VERSION 5.8 ;
BUSBITCHARS "[]" ;
DIVIDERCHAR "/" ;
UNITS
    DATABASE MICRONS 1000 ;
END UNITS

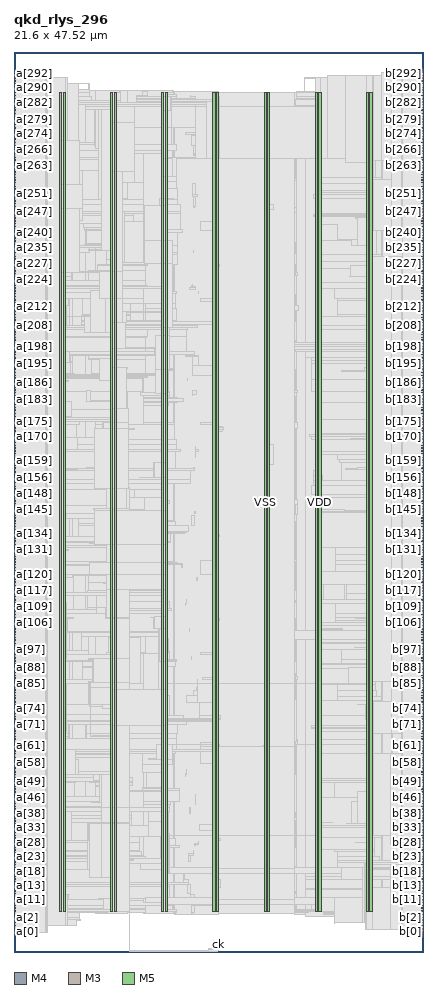
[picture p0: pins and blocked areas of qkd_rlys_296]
MACRO qkd_rlys_296
  FOREIGN qkd_rlys_296 0 0 ;
  CLASS BLOCK ;
  SIZE 21.6 BY 47.52 ;
  PIN a[0]
    DIRECTION INPUT ;
    USE SIGNAL ;
    PORT
      LAYER M4 ;
        RECT  0 1.056 0.084 1.08 ;
    END
  END a[0]
  PIN a[100]
    DIRECTION INPUT ;
    USE SIGNAL ;
    PORT
      LAYER M4 ;
        RECT  0 16.464 0.084 16.488 ;
    END
  END a[100]
  PIN a[101]
    DIRECTION INPUT ;
    USE SIGNAL ;
    PORT
      LAYER M4 ;
        RECT  0 16.608 0.084 16.632 ;
    END
  END a[101]
  PIN a[102]
    DIRECTION INPUT ;
    USE SIGNAL ;
    PORT
      LAYER M4 ;
        RECT  0 16.752 0.084 16.776 ;
    END
  END a[102]
  PIN a[103]
    DIRECTION INPUT ;
    USE SIGNAL ;
    PORT
      LAYER M4 ;
        RECT  0 16.896 0.084 16.92 ;
    END
  END a[103]
  PIN a[104]
    DIRECTION INPUT ;
    USE SIGNAL ;
    PORT
      LAYER M4 ;
        RECT  0 17.04 0.084 17.064 ;
    END
  END a[104]
  PIN a[105]
    DIRECTION INPUT ;
    USE SIGNAL ;
    PORT
      LAYER M4 ;
        RECT  0 17.232 0.084 17.256 ;
    END
  END a[105]
  PIN a[106]
    DIRECTION INPUT ;
    USE SIGNAL ;
    PORT
      LAYER M4 ;
        RECT  0 17.376 0.084 17.4 ;
    END
  END a[106]
  PIN a[107]
    DIRECTION INPUT ;
    USE SIGNAL ;
    PORT
      LAYER M4 ;
        RECT  0 17.52 0.084 17.544 ;
    END
  END a[107]
  PIN a[108]
    DIRECTION INPUT ;
    USE SIGNAL ;
    PORT
      LAYER M4 ;
        RECT  0 17.664 0.084 17.688 ;
    END
  END a[108]
  PIN a[109]
    DIRECTION INPUT ;
    USE SIGNAL ;
    PORT
      LAYER M4 ;
        RECT  0 17.808 0.084 17.832 ;
    END
  END a[109]
  PIN a[10]
    DIRECTION INPUT ;
    USE SIGNAL ;
    PORT
      LAYER M4 ;
        RECT  0 2.592 0.084 2.616 ;
    END
  END a[10]
  PIN a[110]
    DIRECTION INPUT ;
    USE SIGNAL ;
    PORT
      LAYER M4 ;
        RECT  0 18 0.084 18.024 ;
    END
  END a[110]
  PIN a[111]
    DIRECTION INPUT ;
    USE SIGNAL ;
    PORT
      LAYER M4 ;
        RECT  0 18.144 0.084 18.168 ;
    END
  END a[111]
  PIN a[112]
    DIRECTION INPUT ;
    USE SIGNAL ;
    PORT
      LAYER M4 ;
        RECT  0 18.288 0.084 18.312 ;
    END
  END a[112]
  PIN a[113]
    DIRECTION INPUT ;
    USE SIGNAL ;
    PORT
      LAYER M4 ;
        RECT  0 18.432 0.084 18.456 ;
    END
  END a[113]
  PIN a[114]
    DIRECTION INPUT ;
    USE SIGNAL ;
    PORT
      LAYER M4 ;
        RECT  0 18.576 0.084 18.6 ;
    END
  END a[114]
  PIN a[115]
    DIRECTION INPUT ;
    USE SIGNAL ;
    PORT
      LAYER M4 ;
        RECT  0 18.768 0.084 18.792 ;
    END
  END a[115]
  PIN a[116]
    DIRECTION INPUT ;
    USE SIGNAL ;
    PORT
      LAYER M4 ;
        RECT  0 18.912 0.084 18.936 ;
    END
  END a[116]
  PIN a[117]
    DIRECTION INPUT ;
    USE SIGNAL ;
    PORT
      LAYER M4 ;
        RECT  0 19.056 0.084 19.08 ;
    END
  END a[117]
  PIN a[118]
    DIRECTION INPUT ;
    USE SIGNAL ;
    PORT
      LAYER M4 ;
        RECT  0 19.2 0.084 19.224 ;
    END
  END a[118]
  PIN a[119]
    DIRECTION INPUT ;
    USE SIGNAL ;
    PORT
      LAYER M4 ;
        RECT  0 19.344 0.084 19.368 ;
    END
  END a[119]
  PIN a[11]
    DIRECTION INPUT ;
    USE SIGNAL ;
    PORT
      LAYER M4 ;
        RECT  0 2.736 0.084 2.76 ;
    END
  END a[11]
  PIN a[120]
    DIRECTION INPUT ;
    USE SIGNAL ;
    PORT
      LAYER M4 ;
        RECT  0 19.536 0.084 19.56 ;
    END
  END a[120]
  PIN a[121]
    DIRECTION INPUT ;
    USE SIGNAL ;
    PORT
      LAYER M4 ;
        RECT  0 19.68 0.084 19.704 ;
    END
  END a[121]
  PIN a[122]
    DIRECTION INPUT ;
    USE SIGNAL ;
    PORT
      LAYER M4 ;
        RECT  0 19.824 0.084 19.848 ;
    END
  END a[122]
  PIN a[123]
    DIRECTION INPUT ;
    USE SIGNAL ;
    PORT
      LAYER M4 ;
        RECT  0 19.968 0.084 19.992 ;
    END
  END a[123]
  PIN a[124]
    DIRECTION INPUT ;
    USE SIGNAL ;
    PORT
      LAYER M4 ;
        RECT  0 20.112 0.084 20.136 ;
    END
  END a[124]
  PIN a[125]
    DIRECTION INPUT ;
    USE SIGNAL ;
    PORT
      LAYER M4 ;
        RECT  0 20.304 0.084 20.328 ;
    END
  END a[125]
  PIN a[126]
    DIRECTION INPUT ;
    USE SIGNAL ;
    PORT
      LAYER M4 ;
        RECT  0 20.448 0.084 20.472 ;
    END
  END a[126]
  PIN a[127]
    DIRECTION INPUT ;
    USE SIGNAL ;
    PORT
      LAYER M4 ;
        RECT  0 20.592 0.084 20.616 ;
    END
  END a[127]
  PIN a[128]
    DIRECTION INPUT ;
    USE SIGNAL ;
    PORT
      LAYER M4 ;
        RECT  0 20.736 0.084 20.76 ;
    END
  END a[128]
  PIN a[129]
    DIRECTION INPUT ;
    USE SIGNAL ;
    PORT
      LAYER M4 ;
        RECT  0 20.88 0.084 20.904 ;
    END
  END a[129]
  PIN a[12]
    DIRECTION INPUT ;
    USE SIGNAL ;
    PORT
      LAYER M4 ;
        RECT  0 2.928 0.084 2.952 ;
    END
  END a[12]
  PIN a[130]
    DIRECTION INPUT ;
    USE SIGNAL ;
    PORT
      LAYER M4 ;
        RECT  0 21.072 0.084 21.096 ;
    END
  END a[130]
  PIN a[131]
    DIRECTION INPUT ;
    USE SIGNAL ;
    PORT
      LAYER M4 ;
        RECT  0 21.216 0.084 21.24 ;
    END
  END a[131]
  PIN a[132]
    DIRECTION INPUT ;
    USE SIGNAL ;
    PORT
      LAYER M4 ;
        RECT  0 21.36 0.084 21.384 ;
    END
  END a[132]
  PIN a[133]
    DIRECTION INPUT ;
    USE SIGNAL ;
    PORT
      LAYER M4 ;
        RECT  0 21.504 0.084 21.528 ;
    END
  END a[133]
  PIN a[134]
    DIRECTION INPUT ;
    USE SIGNAL ;
    PORT
      LAYER M4 ;
        RECT  0 21.696 0.084 21.72 ;
    END
  END a[134]
  PIN a[135]
    DIRECTION INPUT ;
    USE SIGNAL ;
    PORT
      LAYER M4 ;
        RECT  0 21.84 0.084 21.864 ;
    END
  END a[135]
  PIN a[136]
    DIRECTION INPUT ;
    USE SIGNAL ;
    PORT
      LAYER M4 ;
        RECT  0 21.984 0.084 22.008 ;
    END
  END a[136]
  PIN a[137]
    DIRECTION INPUT ;
    USE SIGNAL ;
    PORT
      LAYER M4 ;
        RECT  0 22.128 0.084 22.152 ;
    END
  END a[137]
  PIN a[138]
    DIRECTION INPUT ;
    USE SIGNAL ;
    PORT
      LAYER M4 ;
        RECT  0 22.272 0.084 22.296 ;
    END
  END a[138]
  PIN a[139]
    DIRECTION INPUT ;
    USE SIGNAL ;
    PORT
      LAYER M4 ;
        RECT  0 22.464 0.084 22.488 ;
    END
  END a[139]
  PIN a[13]
    DIRECTION INPUT ;
    USE SIGNAL ;
    PORT
      LAYER M4 ;
        RECT  0 3.072 0.084 3.096 ;
    END
  END a[13]
  PIN a[140]
    DIRECTION INPUT ;
    USE SIGNAL ;
    PORT
      LAYER M4 ;
        RECT  0 22.608 0.084 22.632 ;
    END
  END a[140]
  PIN a[141]
    DIRECTION INPUT ;
    USE SIGNAL ;
    PORT
      LAYER M4 ;
        RECT  0 22.752 0.084 22.776 ;
    END
  END a[141]
  PIN a[142]
    DIRECTION INPUT ;
    USE SIGNAL ;
    PORT
      LAYER M4 ;
        RECT  0 22.896 0.084 22.92 ;
    END
  END a[142]
  PIN a[143]
    DIRECTION INPUT ;
    USE SIGNAL ;
    PORT
      LAYER M4 ;
        RECT  0 23.04 0.084 23.064 ;
    END
  END a[143]
  PIN a[144]
    DIRECTION INPUT ;
    USE SIGNAL ;
    PORT
      LAYER M4 ;
        RECT  0 23.232 0.084 23.256 ;
    END
  END a[144]
  PIN a[145]
    DIRECTION INPUT ;
    USE SIGNAL ;
    PORT
      LAYER M4 ;
        RECT  0 23.376 0.084 23.4 ;
    END
  END a[145]
  PIN a[146]
    DIRECTION INPUT ;
    USE SIGNAL ;
    PORT
      LAYER M4 ;
        RECT  0 23.52 0.084 23.544 ;
    END
  END a[146]
  PIN a[147]
    DIRECTION INPUT ;
    USE SIGNAL ;
    PORT
      LAYER M4 ;
        RECT  0 23.664 0.084 23.688 ;
    END
  END a[147]
  PIN a[148]
    DIRECTION INPUT ;
    USE SIGNAL ;
    PORT
      LAYER M4 ;
        RECT  0 23.808 0.084 23.832 ;
    END
  END a[148]
  PIN a[149]
    DIRECTION INPUT ;
    USE SIGNAL ;
    PORT
      LAYER M4 ;
        RECT  0 24 0.084 24.024 ;
    END
  END a[149]
  PIN a[14]
    DIRECTION INPUT ;
    USE SIGNAL ;
    PORT
      LAYER M4 ;
        RECT  0 3.216 0.084 3.24 ;
    END
  END a[14]
  PIN a[150]
    DIRECTION INPUT ;
    USE SIGNAL ;
    PORT
      LAYER M4 ;
        RECT  0 24.144 0.084 24.168 ;
    END
  END a[150]
  PIN a[151]
    DIRECTION INPUT ;
    USE SIGNAL ;
    PORT
      LAYER M4 ;
        RECT  0 24.288 0.084 24.312 ;
    END
  END a[151]
  PIN a[152]
    DIRECTION INPUT ;
    USE SIGNAL ;
    PORT
      LAYER M4 ;
        RECT  0 24.432 0.084 24.456 ;
    END
  END a[152]
  PIN a[153]
    DIRECTION INPUT ;
    USE SIGNAL ;
    PORT
      LAYER M4 ;
        RECT  0 24.576 0.084 24.6 ;
    END
  END a[153]
  PIN a[154]
    DIRECTION INPUT ;
    USE SIGNAL ;
    PORT
      LAYER M4 ;
        RECT  0 24.768 0.084 24.792 ;
    END
  END a[154]
  PIN a[155]
    DIRECTION INPUT ;
    USE SIGNAL ;
    PORT
      LAYER M4 ;
        RECT  0 24.912 0.084 24.936 ;
    END
  END a[155]
  PIN a[156]
    DIRECTION INPUT ;
    USE SIGNAL ;
    PORT
      LAYER M4 ;
        RECT  0 25.056 0.084 25.08 ;
    END
  END a[156]
  PIN a[157]
    DIRECTION INPUT ;
    USE SIGNAL ;
    PORT
      LAYER M4 ;
        RECT  0 25.2 0.084 25.224 ;
    END
  END a[157]
  PIN a[158]
    DIRECTION INPUT ;
    USE SIGNAL ;
    PORT
      LAYER M4 ;
        RECT  0 25.344 0.084 25.368 ;
    END
  END a[158]
  PIN a[159]
    DIRECTION INPUT ;
    USE SIGNAL ;
    PORT
      LAYER M4 ;
        RECT  0 25.536 0.084 25.56 ;
    END
  END a[159]
  PIN a[15]
    DIRECTION INPUT ;
    USE SIGNAL ;
    PORT
      LAYER M4 ;
        RECT  0 3.36 0.084 3.384 ;
    END
  END a[15]
  PIN a[160]
    DIRECTION INPUT ;
    USE SIGNAL ;
    PORT
      LAYER M4 ;
        RECT  0 25.68 0.084 25.704 ;
    END
  END a[160]
  PIN a[161]
    DIRECTION INPUT ;
    USE SIGNAL ;
    PORT
      LAYER M4 ;
        RECT  0 25.824 0.084 25.848 ;
    END
  END a[161]
  PIN a[162]
    DIRECTION INPUT ;
    USE SIGNAL ;
    PORT
      LAYER M4 ;
        RECT  0 25.968 0.084 25.992 ;
    END
  END a[162]
  PIN a[163]
    DIRECTION INPUT ;
    USE SIGNAL ;
    PORT
      LAYER M4 ;
        RECT  0 26.112 0.084 26.136 ;
    END
  END a[163]
  PIN a[164]
    DIRECTION INPUT ;
    USE SIGNAL ;
    PORT
      LAYER M4 ;
        RECT  0 26.304 0.084 26.328 ;
    END
  END a[164]
  PIN a[165]
    DIRECTION INPUT ;
    USE SIGNAL ;
    PORT
      LAYER M4 ;
        RECT  0 26.448 0.084 26.472 ;
    END
  END a[165]
  PIN a[166]
    DIRECTION INPUT ;
    USE SIGNAL ;
    PORT
      LAYER M4 ;
        RECT  0 26.592 0.084 26.616 ;
    END
  END a[166]
  PIN a[167]
    DIRECTION INPUT ;
    USE SIGNAL ;
    PORT
      LAYER M4 ;
        RECT  0 26.736 0.084 26.76 ;
    END
  END a[167]
  PIN a[168]
    DIRECTION INPUT ;
    USE SIGNAL ;
    PORT
      LAYER M4 ;
        RECT  0 26.88 0.084 26.904 ;
    END
  END a[168]
  PIN a[169]
    DIRECTION INPUT ;
    USE SIGNAL ;
    PORT
      LAYER M4 ;
        RECT  0 27.072 0.084 27.096 ;
    END
  END a[169]
  PIN a[16]
    DIRECTION INPUT ;
    USE SIGNAL ;
    PORT
      LAYER M4 ;
        RECT  0 3.504 0.084 3.528 ;
    END
  END a[16]
  PIN a[170]
    DIRECTION INPUT ;
    USE SIGNAL ;
    PORT
      LAYER M4 ;
        RECT  0 27.216 0.084 27.24 ;
    END
  END a[170]
  PIN a[171]
    DIRECTION INPUT ;
    USE SIGNAL ;
    PORT
      LAYER M4 ;
        RECT  0 27.36 0.084 27.384 ;
    END
  END a[171]
  PIN a[172]
    DIRECTION INPUT ;
    USE SIGNAL ;
    PORT
      LAYER M4 ;
        RECT  0 27.504 0.084 27.528 ;
    END
  END a[172]
  PIN a[173]
    DIRECTION INPUT ;
    USE SIGNAL ;
    PORT
      LAYER M4 ;
        RECT  0 27.648 0.084 27.672 ;
    END
  END a[173]
  PIN a[174]
    DIRECTION INPUT ;
    USE SIGNAL ;
    PORT
      LAYER M4 ;
        RECT  0 27.84 0.084 27.864 ;
    END
  END a[174]
  PIN a[175]
    DIRECTION INPUT ;
    USE SIGNAL ;
    PORT
      LAYER M4 ;
        RECT  0 27.984 0.084 28.008 ;
    END
  END a[175]
  PIN a[176]
    DIRECTION INPUT ;
    USE SIGNAL ;
    PORT
      LAYER M4 ;
        RECT  0 28.128 0.084 28.152 ;
    END
  END a[176]
  PIN a[177]
    DIRECTION INPUT ;
    USE SIGNAL ;
    PORT
      LAYER M4 ;
        RECT  0 28.272 0.084 28.296 ;
    END
  END a[177]
  PIN a[178]
    DIRECTION INPUT ;
    USE SIGNAL ;
    PORT
      LAYER M4 ;
        RECT  0 28.416 0.084 28.44 ;
    END
  END a[178]
  PIN a[179]
    DIRECTION INPUT ;
    USE SIGNAL ;
    PORT
      LAYER M4 ;
        RECT  0 28.608 0.084 28.632 ;
    END
  END a[179]
  PIN a[17]
    DIRECTION INPUT ;
    USE SIGNAL ;
    PORT
      LAYER M4 ;
        RECT  0 3.696 0.084 3.72 ;
    END
  END a[17]
  PIN a[180]
    DIRECTION INPUT ;
    USE SIGNAL ;
    PORT
      LAYER M4 ;
        RECT  0 28.752 0.084 28.776 ;
    END
  END a[180]
  PIN a[181]
    DIRECTION INPUT ;
    USE SIGNAL ;
    PORT
      LAYER M4 ;
        RECT  0 28.896 0.084 28.92 ;
    END
  END a[181]
  PIN a[182]
    DIRECTION INPUT ;
    USE SIGNAL ;
    PORT
      LAYER M4 ;
        RECT  0 29.04 0.084 29.064 ;
    END
  END a[182]
  PIN a[183]
    DIRECTION INPUT ;
    USE SIGNAL ;
    PORT
      LAYER M4 ;
        RECT  0 29.184 0.084 29.208 ;
    END
  END a[183]
  PIN a[184]
    DIRECTION INPUT ;
    USE SIGNAL ;
    PORT
      LAYER M4 ;
        RECT  0 29.376 0.084 29.4 ;
    END
  END a[184]
  PIN a[185]
    DIRECTION INPUT ;
    USE SIGNAL ;
    PORT
      LAYER M4 ;
        RECT  0 29.52 0.084 29.544 ;
    END
  END a[185]
  PIN a[186]
    DIRECTION INPUT ;
    USE SIGNAL ;
    PORT
      LAYER M4 ;
        RECT  0 29.664 0.084 29.688 ;
    END
  END a[186]
  PIN a[187]
    DIRECTION INPUT ;
    USE SIGNAL ;
    PORT
      LAYER M4 ;
        RECT  0 29.808 0.084 29.832 ;
    END
  END a[187]
  PIN a[188]
    DIRECTION INPUT ;
    USE SIGNAL ;
    PORT
      LAYER M4 ;
        RECT  0 30 0.084 30.024 ;
    END
  END a[188]
  PIN a[189]
    DIRECTION INPUT ;
    USE SIGNAL ;
    PORT
      LAYER M4 ;
        RECT  0 30.144 0.084 30.168 ;
    END
  END a[189]
  PIN a[18]
    DIRECTION INPUT ;
    USE SIGNAL ;
    PORT
      LAYER M4 ;
        RECT  0 3.84 0.084 3.864 ;
    END
  END a[18]
  PIN a[190]
    DIRECTION INPUT ;
    USE SIGNAL ;
    PORT
      LAYER M4 ;
        RECT  0 30.288 0.084 30.312 ;
    END
  END a[190]
  PIN a[191]
    DIRECTION INPUT ;
    USE SIGNAL ;
    PORT
      LAYER M4 ;
        RECT  0 30.432 0.084 30.456 ;
    END
  END a[191]
  PIN a[192]
    DIRECTION INPUT ;
    USE SIGNAL ;
    PORT
      LAYER M4 ;
        RECT  0 30.576 0.084 30.6 ;
    END
  END a[192]
  PIN a[193]
    DIRECTION INPUT ;
    USE SIGNAL ;
    PORT
      LAYER M4 ;
        RECT  0 30.768 0.084 30.792 ;
    END
  END a[193]
  PIN a[194]
    DIRECTION INPUT ;
    USE SIGNAL ;
    PORT
      LAYER M4 ;
        RECT  0 30.912 0.084 30.936 ;
    END
  END a[194]
  PIN a[195]
    DIRECTION INPUT ;
    USE SIGNAL ;
    PORT
      LAYER M4 ;
        RECT  0 31.056 0.084 31.08 ;
    END
  END a[195]
  PIN a[196]
    DIRECTION INPUT ;
    USE SIGNAL ;
    PORT
      LAYER M4 ;
        RECT  0 31.2 0.084 31.224 ;
    END
  END a[196]
  PIN a[197]
    DIRECTION INPUT ;
    USE SIGNAL ;
    PORT
      LAYER M4 ;
        RECT  0 31.344 0.084 31.368 ;
    END
  END a[197]
  PIN a[198]
    DIRECTION INPUT ;
    USE SIGNAL ;
    PORT
      LAYER M4 ;
        RECT  0 31.536 0.084 31.56 ;
    END
  END a[198]
  PIN a[199]
    DIRECTION INPUT ;
    USE SIGNAL ;
    PORT
      LAYER M4 ;
        RECT  0 31.68 0.084 31.704 ;
    END
  END a[199]
  PIN a[19]
    DIRECTION INPUT ;
    USE SIGNAL ;
    PORT
      LAYER M4 ;
        RECT  0 3.984 0.084 4.008 ;
    END
  END a[19]
  PIN a[1]
    DIRECTION INPUT ;
    USE SIGNAL ;
    PORT
      LAYER M4 ;
        RECT  0 1.2 0.084 1.224 ;
    END
  END a[1]
  PIN a[200]
    DIRECTION INPUT ;
    USE SIGNAL ;
    PORT
      LAYER M4 ;
        RECT  0 31.824 0.084 31.848 ;
    END
  END a[200]
  PIN a[201]
    DIRECTION INPUT ;
    USE SIGNAL ;
    PORT
      LAYER M4 ;
        RECT  0 31.968 0.084 31.992 ;
    END
  END a[201]
  PIN a[202]
    DIRECTION INPUT ;
    USE SIGNAL ;
    PORT
      LAYER M4 ;
        RECT  0 32.112 0.084 32.136 ;
    END
  END a[202]
  PIN a[203]
    DIRECTION INPUT ;
    USE SIGNAL ;
    PORT
      LAYER M4 ;
        RECT  0 32.304 0.084 32.328 ;
    END
  END a[203]
  PIN a[204]
    DIRECTION INPUT ;
    USE SIGNAL ;
    PORT
      LAYER M4 ;
        RECT  0 32.448 0.084 32.472 ;
    END
  END a[204]
  PIN a[205]
    DIRECTION INPUT ;
    USE SIGNAL ;
    PORT
      LAYER M4 ;
        RECT  0 32.592 0.084 32.616 ;
    END
  END a[205]
  PIN a[206]
    DIRECTION INPUT ;
    USE SIGNAL ;
    PORT
      LAYER M4 ;
        RECT  0 32.736 0.084 32.76 ;
    END
  END a[206]
  PIN a[207]
    DIRECTION INPUT ;
    USE SIGNAL ;
    PORT
      LAYER M4 ;
        RECT  0 32.88 0.084 32.904 ;
    END
  END a[207]
  PIN a[208]
    DIRECTION INPUT ;
    USE SIGNAL ;
    PORT
      LAYER M4 ;
        RECT  0 33.072 0.084 33.096 ;
    END
  END a[208]
  PIN a[209]
    DIRECTION INPUT ;
    USE SIGNAL ;
    PORT
      LAYER M4 ;
        RECT  0 33.216 0.084 33.24 ;
    END
  END a[209]
  PIN a[20]
    DIRECTION INPUT ;
    USE SIGNAL ;
    PORT
      LAYER M4 ;
        RECT  0 4.128 0.084 4.152 ;
    END
  END a[20]
  PIN a[210]
    DIRECTION INPUT ;
    USE SIGNAL ;
    PORT
      LAYER M4 ;
        RECT  0 33.36 0.084 33.384 ;
    END
  END a[210]
  PIN a[211]
    DIRECTION INPUT ;
    USE SIGNAL ;
    PORT
      LAYER M4 ;
        RECT  0 33.504 0.084 33.528 ;
    END
  END a[211]
  PIN a[212]
    DIRECTION INPUT ;
    USE SIGNAL ;
    PORT
      LAYER M4 ;
        RECT  0 33.648 0.084 33.672 ;
    END
  END a[212]
  PIN a[213]
    DIRECTION INPUT ;
    USE SIGNAL ;
    PORT
      LAYER M4 ;
        RECT  0 33.84 0.084 33.864 ;
    END
  END a[213]
  PIN a[214]
    DIRECTION INPUT ;
    USE SIGNAL ;
    PORT
      LAYER M4 ;
        RECT  0 33.984 0.084 34.008 ;
    END
  END a[214]
  PIN a[215]
    DIRECTION INPUT ;
    USE SIGNAL ;
    PORT
      LAYER M4 ;
        RECT  0 34.128 0.084 34.152 ;
    END
  END a[215]
  PIN a[216]
    DIRECTION INPUT ;
    USE SIGNAL ;
    PORT
      LAYER M4 ;
        RECT  0 34.272 0.084 34.296 ;
    END
  END a[216]
  PIN a[217]
    DIRECTION INPUT ;
    USE SIGNAL ;
    PORT
      LAYER M4 ;
        RECT  0 34.416 0.084 34.44 ;
    END
  END a[217]
  PIN a[218]
    DIRECTION INPUT ;
    USE SIGNAL ;
    PORT
      LAYER M4 ;
        RECT  0 34.608 0.084 34.632 ;
    END
  END a[218]
  PIN a[219]
    DIRECTION INPUT ;
    USE SIGNAL ;
    PORT
      LAYER M4 ;
        RECT  0 34.752 0.084 34.776 ;
    END
  END a[219]
  PIN a[21]
    DIRECTION INPUT ;
    USE SIGNAL ;
    PORT
      LAYER M4 ;
        RECT  0 4.272 0.084 4.296 ;
    END
  END a[21]
  PIN a[220]
    DIRECTION INPUT ;
    USE SIGNAL ;
    PORT
      LAYER M4 ;
        RECT  0 34.896 0.084 34.92 ;
    END
  END a[220]
  PIN a[221]
    DIRECTION INPUT ;
    USE SIGNAL ;
    PORT
      LAYER M4 ;
        RECT  0 35.04 0.084 35.064 ;
    END
  END a[221]
  PIN a[222]
    DIRECTION INPUT ;
    USE SIGNAL ;
    PORT
      LAYER M4 ;
        RECT  0 35.184 0.084 35.208 ;
    END
  END a[222]
  PIN a[223]
    DIRECTION INPUT ;
    USE SIGNAL ;
    PORT
      LAYER M4 ;
        RECT  0 35.376 0.084 35.4 ;
    END
  END a[223]
  PIN a[224]
    DIRECTION INPUT ;
    USE SIGNAL ;
    PORT
      LAYER M4 ;
        RECT  0 35.52 0.084 35.544 ;
    END
  END a[224]
  PIN a[225]
    DIRECTION INPUT ;
    USE SIGNAL ;
    PORT
      LAYER M4 ;
        RECT  0 35.664 0.084 35.688 ;
    END
  END a[225]
  PIN a[226]
    DIRECTION INPUT ;
    USE SIGNAL ;
    PORT
      LAYER M4 ;
        RECT  0 35.808 0.084 35.832 ;
    END
  END a[226]
  PIN a[227]
    DIRECTION INPUT ;
    USE SIGNAL ;
    PORT
      LAYER M4 ;
        RECT  0 35.952 0.084 35.976 ;
    END
  END a[227]
  PIN a[228]
    DIRECTION INPUT ;
    USE SIGNAL ;
    PORT
      LAYER M4 ;
        RECT  0 36.144 0.084 36.168 ;
    END
  END a[228]
  PIN a[229]
    DIRECTION INPUT ;
    USE SIGNAL ;
    PORT
      LAYER M4 ;
        RECT  0 36.288 0.084 36.312 ;
    END
  END a[229]
  PIN a[22]
    DIRECTION INPUT ;
    USE SIGNAL ;
    PORT
      LAYER M4 ;
        RECT  0 4.464 0.084 4.488 ;
    END
  END a[22]
  PIN a[230]
    DIRECTION INPUT ;
    USE SIGNAL ;
    PORT
      LAYER M4 ;
        RECT  0 36.432 0.084 36.456 ;
    END
  END a[230]
  PIN a[231]
    DIRECTION INPUT ;
    USE SIGNAL ;
    PORT
      LAYER M4 ;
        RECT  0 36.576 0.084 36.6 ;
    END
  END a[231]
  PIN a[232]
    DIRECTION INPUT ;
    USE SIGNAL ;
    PORT
      LAYER M4 ;
        RECT  0 36.72 0.084 36.744 ;
    END
  END a[232]
  PIN a[233]
    DIRECTION INPUT ;
    USE SIGNAL ;
    PORT
      LAYER M4 ;
        RECT  0 36.912 0.084 36.936 ;
    END
  END a[233]
  PIN a[234]
    DIRECTION INPUT ;
    USE SIGNAL ;
    PORT
      LAYER M4 ;
        RECT  0 37.056 0.084 37.08 ;
    END
  END a[234]
  PIN a[235]
    DIRECTION INPUT ;
    USE SIGNAL ;
    PORT
      LAYER M4 ;
        RECT  0 37.2 0.084 37.224 ;
    END
  END a[235]
  PIN a[236]
    DIRECTION INPUT ;
    USE SIGNAL ;
    PORT
      LAYER M4 ;
        RECT  0 37.344 0.084 37.368 ;
    END
  END a[236]
  PIN a[237]
    DIRECTION INPUT ;
    USE SIGNAL ;
    PORT
      LAYER M4 ;
        RECT  0 37.536 0.084 37.56 ;
    END
  END a[237]
  PIN a[238]
    DIRECTION INPUT ;
    USE SIGNAL ;
    PORT
      LAYER M4 ;
        RECT  0 37.68 0.084 37.704 ;
    END
  END a[238]
  PIN a[239]
    DIRECTION INPUT ;
    USE SIGNAL ;
    PORT
      LAYER M4 ;
        RECT  0 37.824 0.084 37.848 ;
    END
  END a[239]
  PIN a[23]
    DIRECTION INPUT ;
    USE SIGNAL ;
    PORT
      LAYER M4 ;
        RECT  0 4.608 0.084 4.632 ;
    END
  END a[23]
  PIN a[240]
    DIRECTION INPUT ;
    USE SIGNAL ;
    PORT
      LAYER M4 ;
        RECT  0 37.968 0.084 37.992 ;
    END
  END a[240]
  PIN a[241]
    DIRECTION INPUT ;
    USE SIGNAL ;
    PORT
      LAYER M4 ;
        RECT  0 38.112 0.084 38.136 ;
    END
  END a[241]
  PIN a[242]
    DIRECTION INPUT ;
    USE SIGNAL ;
    PORT
      LAYER M4 ;
        RECT  0 38.304 0.084 38.328 ;
    END
  END a[242]
  PIN a[243]
    DIRECTION INPUT ;
    USE SIGNAL ;
    PORT
      LAYER M4 ;
        RECT  0 38.448 0.084 38.472 ;
    END
  END a[243]
  PIN a[244]
    DIRECTION INPUT ;
    USE SIGNAL ;
    PORT
      LAYER M4 ;
        RECT  0 38.592 0.084 38.616 ;
    END
  END a[244]
  PIN a[245]
    DIRECTION INPUT ;
    USE SIGNAL ;
    PORT
      LAYER M4 ;
        RECT  0 38.736 0.084 38.76 ;
    END
  END a[245]
  PIN a[246]
    DIRECTION INPUT ;
    USE SIGNAL ;
    PORT
      LAYER M4 ;
        RECT  0 38.88 0.084 38.904 ;
    END
  END a[246]
  PIN a[247]
    DIRECTION INPUT ;
    USE SIGNAL ;
    PORT
      LAYER M4 ;
        RECT  0 39.072 0.084 39.096 ;
    END
  END a[247]
  PIN a[248]
    DIRECTION INPUT ;
    USE SIGNAL ;
    PORT
      LAYER M4 ;
        RECT  0 39.216 0.084 39.24 ;
    END
  END a[248]
  PIN a[249]
    DIRECTION INPUT ;
    USE SIGNAL ;
    PORT
      LAYER M4 ;
        RECT  0 39.36 0.084 39.384 ;
    END
  END a[249]
  PIN a[24]
    DIRECTION INPUT ;
    USE SIGNAL ;
    PORT
      LAYER M4 ;
        RECT  0 4.752 0.084 4.776 ;
    END
  END a[24]
  PIN a[250]
    DIRECTION INPUT ;
    USE SIGNAL ;
    PORT
      LAYER M4 ;
        RECT  0 39.504 0.084 39.528 ;
    END
  END a[250]
  PIN a[251]
    DIRECTION INPUT ;
    USE SIGNAL ;
    PORT
      LAYER M4 ;
        RECT  0 39.648 0.084 39.672 ;
    END
  END a[251]
  PIN a[252]
    DIRECTION INPUT ;
    USE SIGNAL ;
    PORT
      LAYER M4 ;
        RECT  0 39.84 0.084 39.864 ;
    END
  END a[252]
  PIN a[253]
    DIRECTION INPUT ;
    USE SIGNAL ;
    PORT
      LAYER M4 ;
        RECT  0 39.984 0.084 40.008 ;
    END
  END a[253]
  PIN a[254]
    DIRECTION INPUT ;
    USE SIGNAL ;
    PORT
      LAYER M4 ;
        RECT  0 40.128 0.084 40.152 ;
    END
  END a[254]
  PIN a[255]
    DIRECTION INPUT ;
    USE SIGNAL ;
    PORT
      LAYER M4 ;
        RECT  0 40.272 0.084 40.296 ;
    END
  END a[255]
  PIN a[256]
    DIRECTION INPUT ;
    USE SIGNAL ;
    PORT
      LAYER M4 ;
        RECT  0 40.416 0.084 40.44 ;
    END
  END a[256]
  PIN a[257]
    DIRECTION INPUT ;
    USE SIGNAL ;
    PORT
      LAYER M4 ;
        RECT  0 40.608 0.084 40.632 ;
    END
  END a[257]
  PIN a[258]
    DIRECTION INPUT ;
    USE SIGNAL ;
    PORT
      LAYER M4 ;
        RECT  0 40.752 0.084 40.776 ;
    END
  END a[258]
  PIN a[259]
    DIRECTION INPUT ;
    USE SIGNAL ;
    PORT
      LAYER M4 ;
        RECT  0 40.896 0.084 40.92 ;
    END
  END a[259]
  PIN a[25]
    DIRECTION INPUT ;
    USE SIGNAL ;
    PORT
      LAYER M4 ;
        RECT  0 4.896 0.084 4.92 ;
    END
  END a[25]
  PIN a[260]
    DIRECTION INPUT ;
    USE SIGNAL ;
    PORT
      LAYER M4 ;
        RECT  0 41.04 0.084 41.064 ;
    END
  END a[260]
  PIN a[261]
    DIRECTION INPUT ;
    USE SIGNAL ;
    PORT
      LAYER M4 ;
        RECT  0 41.184 0.084 41.208 ;
    END
  END a[261]
  PIN a[262]
    DIRECTION INPUT ;
    USE SIGNAL ;
    PORT
      LAYER M4 ;
        RECT  0 41.376 0.084 41.4 ;
    END
  END a[262]
  PIN a[263]
    DIRECTION INPUT ;
    USE SIGNAL ;
    PORT
      LAYER M4 ;
        RECT  0 41.52 0.084 41.544 ;
    END
  END a[263]
  PIN a[264]
    DIRECTION INPUT ;
    USE SIGNAL ;
    PORT
      LAYER M4 ;
        RECT  0 41.664 0.084 41.688 ;
    END
  END a[264]
  PIN a[265]
    DIRECTION INPUT ;
    USE SIGNAL ;
    PORT
      LAYER M4 ;
        RECT  0 41.808 0.084 41.832 ;
    END
  END a[265]
  PIN a[266]
    DIRECTION INPUT ;
    USE SIGNAL ;
    PORT
      LAYER M4 ;
        RECT  0 41.952 0.084 41.976 ;
    END
  END a[266]
  PIN a[267]
    DIRECTION INPUT ;
    USE SIGNAL ;
    PORT
      LAYER M4 ;
        RECT  0 42.144 0.084 42.168 ;
    END
  END a[267]
  PIN a[268]
    DIRECTION INPUT ;
    USE SIGNAL ;
    PORT
      LAYER M4 ;
        RECT  0 42.288 0.084 42.312 ;
    END
  END a[268]
  PIN a[269]
    DIRECTION INPUT ;
    USE SIGNAL ;
    PORT
      LAYER M4 ;
        RECT  0 42.432 0.084 42.456 ;
    END
  END a[269]
  PIN a[26]
    DIRECTION INPUT ;
    USE SIGNAL ;
    PORT
      LAYER M4 ;
        RECT  0 5.04 0.084 5.064 ;
    END
  END a[26]
  PIN a[270]
    DIRECTION INPUT ;
    USE SIGNAL ;
    PORT
      LAYER M4 ;
        RECT  0 42.576 0.084 42.6 ;
    END
  END a[270]
  PIN a[271]
    DIRECTION INPUT ;
    USE SIGNAL ;
    PORT
      LAYER M4 ;
        RECT  0 42.72 0.084 42.744 ;
    END
  END a[271]
  PIN a[272]
    DIRECTION INPUT ;
    USE SIGNAL ;
    PORT
      LAYER M4 ;
        RECT  0 42.912 0.084 42.936 ;
    END
  END a[272]
  PIN a[273]
    DIRECTION INPUT ;
    USE SIGNAL ;
    PORT
      LAYER M4 ;
        RECT  0 43.056 0.084 43.08 ;
    END
  END a[273]
  PIN a[274]
    DIRECTION INPUT ;
    USE SIGNAL ;
    PORT
      LAYER M4 ;
        RECT  0 43.2 0.084 43.224 ;
    END
  END a[274]
  PIN a[275]
    DIRECTION INPUT ;
    USE SIGNAL ;
    PORT
      LAYER M4 ;
        RECT  0 43.344 0.084 43.368 ;
    END
  END a[275]
  PIN a[276]
    DIRECTION INPUT ;
    USE SIGNAL ;
    PORT
      LAYER M4 ;
        RECT  0 43.488 0.084 43.512 ;
    END
  END a[276]
  PIN a[277]
    DIRECTION INPUT ;
    USE SIGNAL ;
    PORT
      LAYER M4 ;
        RECT  0 43.68 0.084 43.704 ;
    END
  END a[277]
  PIN a[278]
    DIRECTION INPUT ;
    USE SIGNAL ;
    PORT
      LAYER M4 ;
        RECT  0 43.824 0.084 43.848 ;
    END
  END a[278]
  PIN a[279]
    DIRECTION INPUT ;
    USE SIGNAL ;
    PORT
      LAYER M4 ;
        RECT  0 43.968 0.084 43.992 ;
    END
  END a[279]
  PIN a[27]
    DIRECTION INPUT ;
    USE SIGNAL ;
    PORT
      LAYER M4 ;
        RECT  0 5.232 0.084 5.256 ;
    END
  END a[27]
  PIN a[280]
    DIRECTION INPUT ;
    USE SIGNAL ;
    PORT
      LAYER M4 ;
        RECT  0 44.112 0.084 44.136 ;
    END
  END a[280]
  PIN a[281]
    DIRECTION INPUT ;
    USE SIGNAL ;
    PORT
      LAYER M4 ;
        RECT  0 44.256 0.084 44.28 ;
    END
  END a[281]
  PIN a[282]
    DIRECTION INPUT ;
    USE SIGNAL ;
    PORT
      LAYER M4 ;
        RECT  0 44.448 0.084 44.472 ;
    END
  END a[282]
  PIN a[283]
    DIRECTION INPUT ;
    USE SIGNAL ;
    PORT
      LAYER M4 ;
        RECT  0 44.592 0.084 44.616 ;
    END
  END a[283]
  PIN a[284]
    DIRECTION INPUT ;
    USE SIGNAL ;
    PORT
      LAYER M4 ;
        RECT  0 44.736 0.084 44.76 ;
    END
  END a[284]
  PIN a[285]
    DIRECTION INPUT ;
    USE SIGNAL ;
    PORT
      LAYER M4 ;
        RECT  0 44.88 0.084 44.904 ;
    END
  END a[285]
  PIN a[286]
    DIRECTION INPUT ;
    USE SIGNAL ;
    PORT
      LAYER M4 ;
        RECT  0 45.024 0.084 45.048 ;
    END
  END a[286]
  PIN a[287]
    DIRECTION INPUT ;
    USE SIGNAL ;
    PORT
      LAYER M4 ;
        RECT  0 45.216 0.084 45.24 ;
    END
  END a[287]
  PIN a[288]
    DIRECTION INPUT ;
    USE SIGNAL ;
    PORT
      LAYER M4 ;
        RECT  0 45.36 0.084 45.384 ;
    END
  END a[288]
  PIN a[289]
    DIRECTION INPUT ;
    USE SIGNAL ;
    PORT
      LAYER M4 ;
        RECT  0 45.504 0.084 45.528 ;
    END
  END a[289]
  PIN a[28]
    DIRECTION INPUT ;
    USE SIGNAL ;
    PORT
      LAYER M4 ;
        RECT  0 5.376 0.084 5.4 ;
    END
  END a[28]
  PIN a[290]
    DIRECTION INPUT ;
    USE SIGNAL ;
    PORT
      LAYER M4 ;
        RECT  0 45.648 0.084 45.672 ;
    END
  END a[290]
  PIN a[291]
    DIRECTION INPUT ;
    USE SIGNAL ;
    PORT
      LAYER M4 ;
        RECT  0 45.84 0.084 45.864 ;
    END
  END a[291]
  PIN a[292]
    DIRECTION INPUT ;
    USE SIGNAL ;
    PORT
      LAYER M4 ;
        RECT  0 45.984 0.084 46.008 ;
    END
  END a[292]
  PIN a[293]
    DIRECTION INPUT ;
    USE SIGNAL ;
    PORT
      LAYER M4 ;
        RECT  0 46.128 0.084 46.152 ;
    END
  END a[293]
  PIN a[294]
    DIRECTION INPUT ;
    USE SIGNAL ;
    PORT
      LAYER M4 ;
        RECT  0 46.272 0.084 46.296 ;
    END
  END a[294]
  PIN a[295]
    DIRECTION INPUT ;
    USE SIGNAL ;
    PORT
      LAYER M4 ;
        RECT  0 46.416 0.084 46.44 ;
    END
  END a[295]
  PIN a[29]
    DIRECTION INPUT ;
    USE SIGNAL ;
    PORT
      LAYER M4 ;
        RECT  0 5.52 0.084 5.544 ;
    END
  END a[29]
  PIN a[2]
    DIRECTION INPUT ;
    USE SIGNAL ;
    PORT
      LAYER M4 ;
        RECT  0 1.392 0.084 1.416 ;
    END
  END a[2]
  PIN a[30]
    DIRECTION INPUT ;
    USE SIGNAL ;
    PORT
      LAYER M4 ;
        RECT  0 5.664 0.084 5.688 ;
    END
  END a[30]
  PIN a[31]
    DIRECTION INPUT ;
    USE SIGNAL ;
    PORT
      LAYER M4 ;
        RECT  0 5.856 0.084 5.88 ;
    END
  END a[31]
  PIN a[32]
    DIRECTION INPUT ;
    USE SIGNAL ;
    PORT
      LAYER M4 ;
        RECT  0 6 0.084 6.024 ;
    END
  END a[32]
  PIN a[33]
    DIRECTION INPUT ;
    USE SIGNAL ;
    PORT
      LAYER M4 ;
        RECT  0 6.144 0.084 6.168 ;
    END
  END a[33]
  PIN a[34]
    DIRECTION INPUT ;
    USE SIGNAL ;
    PORT
      LAYER M4 ;
        RECT  0 6.288 0.084 6.312 ;
    END
  END a[34]
  PIN a[35]
    DIRECTION INPUT ;
    USE SIGNAL ;
    PORT
      LAYER M4 ;
        RECT  0 6.432 0.084 6.456 ;
    END
  END a[35]
  PIN a[36]
    DIRECTION INPUT ;
    USE SIGNAL ;
    PORT
      LAYER M4 ;
        RECT  0 6.624 0.084 6.648 ;
    END
  END a[36]
  PIN a[37]
    DIRECTION INPUT ;
    USE SIGNAL ;
    PORT
      LAYER M4 ;
        RECT  0 6.768 0.084 6.792 ;
    END
  END a[37]
  PIN a[38]
    DIRECTION INPUT ;
    USE SIGNAL ;
    PORT
      LAYER M4 ;
        RECT  0 6.912 0.084 6.936 ;
    END
  END a[38]
  PIN a[39]
    DIRECTION INPUT ;
    USE SIGNAL ;
    PORT
      LAYER M4 ;
        RECT  0 7.056 0.084 7.08 ;
    END
  END a[39]
  PIN a[3]
    DIRECTION INPUT ;
    USE SIGNAL ;
    PORT
      LAYER M4 ;
        RECT  0 1.536 0.084 1.56 ;
    END
  END a[3]
  PIN a[40]
    DIRECTION INPUT ;
    USE SIGNAL ;
    PORT
      LAYER M4 ;
        RECT  0 7.2 0.084 7.224 ;
    END
  END a[40]
  PIN a[41]
    DIRECTION INPUT ;
    USE SIGNAL ;
    PORT
      LAYER M4 ;
        RECT  0 7.392 0.084 7.416 ;
    END
  END a[41]
  PIN a[42]
    DIRECTION INPUT ;
    USE SIGNAL ;
    PORT
      LAYER M4 ;
        RECT  0 7.536 0.084 7.56 ;
    END
  END a[42]
  PIN a[43]
    DIRECTION INPUT ;
    USE SIGNAL ;
    PORT
      LAYER M4 ;
        RECT  0 7.68 0.084 7.704 ;
    END
  END a[43]
  PIN a[44]
    DIRECTION INPUT ;
    USE SIGNAL ;
    PORT
      LAYER M4 ;
        RECT  0 7.824 0.084 7.848 ;
    END
  END a[44]
  PIN a[45]
    DIRECTION INPUT ;
    USE SIGNAL ;
    PORT
      LAYER M4 ;
        RECT  0 7.968 0.084 7.992 ;
    END
  END a[45]
  PIN a[46]
    DIRECTION INPUT ;
    USE SIGNAL ;
    PORT
      LAYER M4 ;
        RECT  0 8.16 0.084 8.184 ;
    END
  END a[46]
  PIN a[47]
    DIRECTION INPUT ;
    USE SIGNAL ;
    PORT
      LAYER M4 ;
        RECT  0 8.304 0.084 8.328 ;
    END
  END a[47]
  PIN a[48]
    DIRECTION INPUT ;
    USE SIGNAL ;
    PORT
      LAYER M4 ;
        RECT  0 8.448 0.084 8.472 ;
    END
  END a[48]
  PIN a[49]
    DIRECTION INPUT ;
    USE SIGNAL ;
    PORT
      LAYER M4 ;
        RECT  0 8.592 0.084 8.616 ;
    END
  END a[49]
  PIN a[4]
    DIRECTION INPUT ;
    USE SIGNAL ;
    PORT
      LAYER M4 ;
        RECT  0 1.68 0.084 1.704 ;
    END
  END a[4]
  PIN a[50]
    DIRECTION INPUT ;
    USE SIGNAL ;
    PORT
      LAYER M4 ;
        RECT  0 8.736 0.084 8.76 ;
    END
  END a[50]
  PIN a[51]
    DIRECTION INPUT ;
    USE SIGNAL ;
    PORT
      LAYER M4 ;
        RECT  0 8.928 0.084 8.952 ;
    END
  END a[51]
  PIN a[52]
    DIRECTION INPUT ;
    USE SIGNAL ;
    PORT
      LAYER M4 ;
        RECT  0 9.072 0.084 9.096 ;
    END
  END a[52]
  PIN a[53]
    DIRECTION INPUT ;
    USE SIGNAL ;
    PORT
      LAYER M4 ;
        RECT  0 9.216 0.084 9.24 ;
    END
  END a[53]
  PIN a[54]
    DIRECTION INPUT ;
    USE SIGNAL ;
    PORT
      LAYER M4 ;
        RECT  0 9.36 0.084 9.384 ;
    END
  END a[54]
  PIN a[55]
    DIRECTION INPUT ;
    USE SIGNAL ;
    PORT
      LAYER M4 ;
        RECT  0 9.504 0.084 9.528 ;
    END
  END a[55]
  PIN a[56]
    DIRECTION INPUT ;
    USE SIGNAL ;
    PORT
      LAYER M4 ;
        RECT  0 9.696 0.084 9.72 ;
    END
  END a[56]
  PIN a[57]
    DIRECTION INPUT ;
    USE SIGNAL ;
    PORT
      LAYER M4 ;
        RECT  0 9.84 0.084 9.864 ;
    END
  END a[57]
  PIN a[58]
    DIRECTION INPUT ;
    USE SIGNAL ;
    PORT
      LAYER M4 ;
        RECT  0 9.984 0.084 10.008 ;
    END
  END a[58]
  PIN a[59]
    DIRECTION INPUT ;
    USE SIGNAL ;
    PORT
      LAYER M4 ;
        RECT  0 10.128 0.084 10.152 ;
    END
  END a[59]
  PIN a[5]
    DIRECTION INPUT ;
    USE SIGNAL ;
    PORT
      LAYER M4 ;
        RECT  0 1.824 0.084 1.848 ;
    END
  END a[5]
  PIN a[60]
    DIRECTION INPUT ;
    USE SIGNAL ;
    PORT
      LAYER M4 ;
        RECT  0 10.272 0.084 10.296 ;
    END
  END a[60]
  PIN a[61]
    DIRECTION INPUT ;
    USE SIGNAL ;
    PORT
      LAYER M4 ;
        RECT  0 10.464 0.084 10.488 ;
    END
  END a[61]
  PIN a[62]
    DIRECTION INPUT ;
    USE SIGNAL ;
    PORT
      LAYER M4 ;
        RECT  0 10.608 0.084 10.632 ;
    END
  END a[62]
  PIN a[63]
    DIRECTION INPUT ;
    USE SIGNAL ;
    PORT
      LAYER M4 ;
        RECT  0 10.752 0.084 10.776 ;
    END
  END a[63]
  PIN a[64]
    DIRECTION INPUT ;
    USE SIGNAL ;
    PORT
      LAYER M4 ;
        RECT  0 10.896 0.084 10.92 ;
    END
  END a[64]
  PIN a[65]
    DIRECTION INPUT ;
    USE SIGNAL ;
    PORT
      LAYER M4 ;
        RECT  0 11.04 0.084 11.064 ;
    END
  END a[65]
  PIN a[66]
    DIRECTION INPUT ;
    USE SIGNAL ;
    PORT
      LAYER M4 ;
        RECT  0 11.232 0.084 11.256 ;
    END
  END a[66]
  PIN a[67]
    DIRECTION INPUT ;
    USE SIGNAL ;
    PORT
      LAYER M4 ;
        RECT  0 11.376 0.084 11.4 ;
    END
  END a[67]
  PIN a[68]
    DIRECTION INPUT ;
    USE SIGNAL ;
    PORT
      LAYER M4 ;
        RECT  0 11.52 0.084 11.544 ;
    END
  END a[68]
  PIN a[69]
    DIRECTION INPUT ;
    USE SIGNAL ;
    PORT
      LAYER M4 ;
        RECT  0 11.664 0.084 11.688 ;
    END
  END a[69]
  PIN a[6]
    DIRECTION INPUT ;
    USE SIGNAL ;
    PORT
      LAYER M4 ;
        RECT  0 1.968 0.084 1.992 ;
    END
  END a[6]
  PIN a[70]
    DIRECTION INPUT ;
    USE SIGNAL ;
    PORT
      LAYER M4 ;
        RECT  0 11.808 0.084 11.832 ;
    END
  END a[70]
  PIN a[71]
    DIRECTION INPUT ;
    USE SIGNAL ;
    PORT
      LAYER M4 ;
        RECT  0 12 0.084 12.024 ;
    END
  END a[71]
  PIN a[72]
    DIRECTION INPUT ;
    USE SIGNAL ;
    PORT
      LAYER M4 ;
        RECT  0 12.144 0.084 12.168 ;
    END
  END a[72]
  PIN a[73]
    DIRECTION INPUT ;
    USE SIGNAL ;
    PORT
      LAYER M4 ;
        RECT  0 12.288 0.084 12.312 ;
    END
  END a[73]
  PIN a[74]
    DIRECTION INPUT ;
    USE SIGNAL ;
    PORT
      LAYER M4 ;
        RECT  0 12.432 0.084 12.456 ;
    END
  END a[74]
  PIN a[75]
    DIRECTION INPUT ;
    USE SIGNAL ;
    PORT
      LAYER M4 ;
        RECT  0 12.576 0.084 12.6 ;
    END
  END a[75]
  PIN a[76]
    DIRECTION INPUT ;
    USE SIGNAL ;
    PORT
      LAYER M4 ;
        RECT  0 12.768 0.084 12.792 ;
    END
  END a[76]
  PIN a[77]
    DIRECTION INPUT ;
    USE SIGNAL ;
    PORT
      LAYER M4 ;
        RECT  0 12.912 0.084 12.936 ;
    END
  END a[77]
  PIN a[78]
    DIRECTION INPUT ;
    USE SIGNAL ;
    PORT
      LAYER M4 ;
        RECT  0 13.056 0.084 13.08 ;
    END
  END a[78]
  PIN a[79]
    DIRECTION INPUT ;
    USE SIGNAL ;
    PORT
      LAYER M4 ;
        RECT  0 13.2 0.084 13.224 ;
    END
  END a[79]
  PIN a[7]
    DIRECTION INPUT ;
    USE SIGNAL ;
    PORT
      LAYER M4 ;
        RECT  0 2.16 0.084 2.184 ;
    END
  END a[7]
  PIN a[80]
    DIRECTION INPUT ;
    USE SIGNAL ;
    PORT
      LAYER M4 ;
        RECT  0 13.392 0.084 13.416 ;
    END
  END a[80]
  PIN a[81]
    DIRECTION INPUT ;
    USE SIGNAL ;
    PORT
      LAYER M4 ;
        RECT  0 13.536 0.084 13.56 ;
    END
  END a[81]
  PIN a[82]
    DIRECTION INPUT ;
    USE SIGNAL ;
    PORT
      LAYER M4 ;
        RECT  0 13.68 0.084 13.704 ;
    END
  END a[82]
  PIN a[83]
    DIRECTION INPUT ;
    USE SIGNAL ;
    PORT
      LAYER M4 ;
        RECT  0 13.824 0.084 13.848 ;
    END
  END a[83]
  PIN a[84]
    DIRECTION INPUT ;
    USE SIGNAL ;
    PORT
      LAYER M4 ;
        RECT  0 13.968 0.084 13.992 ;
    END
  END a[84]
  PIN a[85]
    DIRECTION INPUT ;
    USE SIGNAL ;
    PORT
      LAYER M4 ;
        RECT  0 14.16 0.084 14.184 ;
    END
  END a[85]
  PIN a[86]
    DIRECTION INPUT ;
    USE SIGNAL ;
    PORT
      LAYER M4 ;
        RECT  0 14.304 0.084 14.328 ;
    END
  END a[86]
  PIN a[87]
    DIRECTION INPUT ;
    USE SIGNAL ;
    PORT
      LAYER M4 ;
        RECT  0 14.448 0.084 14.472 ;
    END
  END a[87]
  PIN a[88]
    DIRECTION INPUT ;
    USE SIGNAL ;
    PORT
      LAYER M4 ;
        RECT  0 14.592 0.084 14.616 ;
    END
  END a[88]
  PIN a[89]
    DIRECTION INPUT ;
    USE SIGNAL ;
    PORT
      LAYER M4 ;
        RECT  0 14.736 0.084 14.76 ;
    END
  END a[89]
  PIN a[8]
    DIRECTION INPUT ;
    USE SIGNAL ;
    PORT
      LAYER M4 ;
        RECT  0 2.304 0.084 2.328 ;
    END
  END a[8]
  PIN a[90]
    DIRECTION INPUT ;
    USE SIGNAL ;
    PORT
      LAYER M4 ;
        RECT  0 14.928 0.084 14.952 ;
    END
  END a[90]
  PIN a[91]
    DIRECTION INPUT ;
    USE SIGNAL ;
    PORT
      LAYER M4 ;
        RECT  0 15.072 0.084 15.096 ;
    END
  END a[91]
  PIN a[92]
    DIRECTION INPUT ;
    USE SIGNAL ;
    PORT
      LAYER M4 ;
        RECT  0 15.216 0.084 15.24 ;
    END
  END a[92]
  PIN a[93]
    DIRECTION INPUT ;
    USE SIGNAL ;
    PORT
      LAYER M4 ;
        RECT  0 15.36 0.084 15.384 ;
    END
  END a[93]
  PIN a[94]
    DIRECTION INPUT ;
    USE SIGNAL ;
    PORT
      LAYER M4 ;
        RECT  0 15.504 0.084 15.528 ;
    END
  END a[94]
  PIN a[95]
    DIRECTION INPUT ;
    USE SIGNAL ;
    PORT
      LAYER M4 ;
        RECT  0 15.696 0.084 15.72 ;
    END
  END a[95]
  PIN a[96]
    DIRECTION INPUT ;
    USE SIGNAL ;
    PORT
      LAYER M4 ;
        RECT  0 15.84 0.084 15.864 ;
    END
  END a[96]
  PIN a[97]
    DIRECTION INPUT ;
    USE SIGNAL ;
    PORT
      LAYER M4 ;
        RECT  0 15.984 0.084 16.008 ;
    END
  END a[97]
  PIN a[98]
    DIRECTION INPUT ;
    USE SIGNAL ;
    PORT
      LAYER M4 ;
        RECT  0 16.128 0.084 16.152 ;
    END
  END a[98]
  PIN a[99]
    DIRECTION INPUT ;
    USE SIGNAL ;
    PORT
      LAYER M4 ;
        RECT  0 16.272 0.084 16.296 ;
    END
  END a[99]
  PIN a[9]
    DIRECTION INPUT ;
    USE SIGNAL ;
    PORT
      LAYER M4 ;
        RECT  0 2.448 0.084 2.472 ;
    END
  END a[9]
  PIN b[0]
    DIRECTION OUTPUT ;
    USE SIGNAL ;
    PORT
      LAYER M4 ;
        RECT  21.516 1.056 21.6 1.08 ;
    END
  END b[0]
  PIN b[100]
    DIRECTION OUTPUT ;
    USE SIGNAL ;
    PORT
      LAYER M4 ;
        RECT  21.516 16.464 21.6 16.488 ;
    END
  END b[100]
  PIN b[101]
    DIRECTION OUTPUT ;
    USE SIGNAL ;
    PORT
      LAYER M4 ;
        RECT  21.516 16.608 21.6 16.632 ;
    END
  END b[101]
  PIN b[102]
    DIRECTION OUTPUT ;
    USE SIGNAL ;
    PORT
      LAYER M4 ;
        RECT  21.516 16.752 21.6 16.776 ;
    END
  END b[102]
  PIN b[103]
    DIRECTION OUTPUT ;
    USE SIGNAL ;
    PORT
      LAYER M4 ;
        RECT  21.516 16.896 21.6 16.92 ;
    END
  END b[103]
  PIN b[104]
    DIRECTION OUTPUT ;
    USE SIGNAL ;
    PORT
      LAYER M4 ;
        RECT  21.516 17.04 21.6 17.064 ;
    END
  END b[104]
  PIN b[105]
    DIRECTION OUTPUT ;
    USE SIGNAL ;
    PORT
      LAYER M4 ;
        RECT  21.516 17.232 21.6 17.256 ;
    END
  END b[105]
  PIN b[106]
    DIRECTION OUTPUT ;
    USE SIGNAL ;
    PORT
      LAYER M4 ;
        RECT  21.516 17.376 21.6 17.4 ;
    END
  END b[106]
  PIN b[107]
    DIRECTION OUTPUT ;
    USE SIGNAL ;
    PORT
      LAYER M4 ;
        RECT  21.516 17.52 21.6 17.544 ;
    END
  END b[107]
  PIN b[108]
    DIRECTION OUTPUT ;
    USE SIGNAL ;
    PORT
      LAYER M4 ;
        RECT  21.516 17.664 21.6 17.688 ;
    END
  END b[108]
  PIN b[109]
    DIRECTION OUTPUT ;
    USE SIGNAL ;
    PORT
      LAYER M4 ;
        RECT  21.516 17.808 21.6 17.832 ;
    END
  END b[109]
  PIN b[10]
    DIRECTION OUTPUT ;
    USE SIGNAL ;
    PORT
      LAYER M4 ;
        RECT  21.516 2.592 21.6 2.616 ;
    END
  END b[10]
  PIN b[110]
    DIRECTION OUTPUT ;
    USE SIGNAL ;
    PORT
      LAYER M4 ;
        RECT  21.516 18 21.6 18.024 ;
    END
  END b[110]
  PIN b[111]
    DIRECTION OUTPUT ;
    USE SIGNAL ;
    PORT
      LAYER M4 ;
        RECT  21.516 18.144 21.6 18.168 ;
    END
  END b[111]
  PIN b[112]
    DIRECTION OUTPUT ;
    USE SIGNAL ;
    PORT
      LAYER M4 ;
        RECT  21.516 18.288 21.6 18.312 ;
    END
  END b[112]
  PIN b[113]
    DIRECTION OUTPUT ;
    USE SIGNAL ;
    PORT
      LAYER M4 ;
        RECT  21.516 18.432 21.6 18.456 ;
    END
  END b[113]
  PIN b[114]
    DIRECTION OUTPUT ;
    USE SIGNAL ;
    PORT
      LAYER M4 ;
        RECT  21.516 18.576 21.6 18.6 ;
    END
  END b[114]
  PIN b[115]
    DIRECTION OUTPUT ;
    USE SIGNAL ;
    PORT
      LAYER M4 ;
        RECT  21.516 18.768 21.6 18.792 ;
    END
  END b[115]
  PIN b[116]
    DIRECTION OUTPUT ;
    USE SIGNAL ;
    PORT
      LAYER M4 ;
        RECT  21.516 18.912 21.6 18.936 ;
    END
  END b[116]
  PIN b[117]
    DIRECTION OUTPUT ;
    USE SIGNAL ;
    PORT
      LAYER M4 ;
        RECT  21.516 19.056 21.6 19.08 ;
    END
  END b[117]
  PIN b[118]
    DIRECTION OUTPUT ;
    USE SIGNAL ;
    PORT
      LAYER M4 ;
        RECT  21.516 19.2 21.6 19.224 ;
    END
  END b[118]
  PIN b[119]
    DIRECTION OUTPUT ;
    USE SIGNAL ;
    PORT
      LAYER M4 ;
        RECT  21.516 19.344 21.6 19.368 ;
    END
  END b[119]
  PIN b[11]
    DIRECTION OUTPUT ;
    USE SIGNAL ;
    PORT
      LAYER M4 ;
        RECT  21.516 2.736 21.6 2.76 ;
    END
  END b[11]
  PIN b[120]
    DIRECTION OUTPUT ;
    USE SIGNAL ;
    PORT
      LAYER M4 ;
        RECT  21.516 19.536 21.6 19.56 ;
    END
  END b[120]
  PIN b[121]
    DIRECTION OUTPUT ;
    USE SIGNAL ;
    PORT
      LAYER M4 ;
        RECT  21.516 19.68 21.6 19.704 ;
    END
  END b[121]
  PIN b[122]
    DIRECTION OUTPUT ;
    USE SIGNAL ;
    PORT
      LAYER M4 ;
        RECT  21.516 19.824 21.6 19.848 ;
    END
  END b[122]
  PIN b[123]
    DIRECTION OUTPUT ;
    USE SIGNAL ;
    PORT
      LAYER M4 ;
        RECT  21.516 19.968 21.6 19.992 ;
    END
  END b[123]
  PIN b[124]
    DIRECTION OUTPUT ;
    USE SIGNAL ;
    PORT
      LAYER M4 ;
        RECT  21.516 20.112 21.6 20.136 ;
    END
  END b[124]
  PIN b[125]
    DIRECTION OUTPUT ;
    USE SIGNAL ;
    PORT
      LAYER M4 ;
        RECT  21.516 20.304 21.6 20.328 ;
    END
  END b[125]
  PIN b[126]
    DIRECTION OUTPUT ;
    USE SIGNAL ;
    PORT
      LAYER M4 ;
        RECT  21.516 20.448 21.6 20.472 ;
    END
  END b[126]
  PIN b[127]
    DIRECTION OUTPUT ;
    USE SIGNAL ;
    PORT
      LAYER M4 ;
        RECT  21.516 20.592 21.6 20.616 ;
    END
  END b[127]
  PIN b[128]
    DIRECTION OUTPUT ;
    USE SIGNAL ;
    PORT
      LAYER M4 ;
        RECT  21.516 20.736 21.6 20.76 ;
    END
  END b[128]
  PIN b[129]
    DIRECTION OUTPUT ;
    USE SIGNAL ;
    PORT
      LAYER M4 ;
        RECT  21.516 20.88 21.6 20.904 ;
    END
  END b[129]
  PIN b[12]
    DIRECTION OUTPUT ;
    USE SIGNAL ;
    PORT
      LAYER M4 ;
        RECT  21.516 2.928 21.6 2.952 ;
    END
  END b[12]
  PIN b[130]
    DIRECTION OUTPUT ;
    USE SIGNAL ;
    PORT
      LAYER M4 ;
        RECT  21.516 21.072 21.6 21.096 ;
    END
  END b[130]
  PIN b[131]
    DIRECTION OUTPUT ;
    USE SIGNAL ;
    PORT
      LAYER M4 ;
        RECT  21.516 21.216 21.6 21.24 ;
    END
  END b[131]
  PIN b[132]
    DIRECTION OUTPUT ;
    USE SIGNAL ;
    PORT
      LAYER M4 ;
        RECT  21.516 21.36 21.6 21.384 ;
    END
  END b[132]
  PIN b[133]
    DIRECTION OUTPUT ;
    USE SIGNAL ;
    PORT
      LAYER M4 ;
        RECT  21.516 21.504 21.6 21.528 ;
    END
  END b[133]
  PIN b[134]
    DIRECTION OUTPUT ;
    USE SIGNAL ;
    PORT
      LAYER M4 ;
        RECT  21.516 21.696 21.6 21.72 ;
    END
  END b[134]
  PIN b[135]
    DIRECTION OUTPUT ;
    USE SIGNAL ;
    PORT
      LAYER M4 ;
        RECT  21.516 21.84 21.6 21.864 ;
    END
  END b[135]
  PIN b[136]
    DIRECTION OUTPUT ;
    USE SIGNAL ;
    PORT
      LAYER M4 ;
        RECT  21.516 21.984 21.6 22.008 ;
    END
  END b[136]
  PIN b[137]
    DIRECTION OUTPUT ;
    USE SIGNAL ;
    PORT
      LAYER M4 ;
        RECT  21.516 22.128 21.6 22.152 ;
    END
  END b[137]
  PIN b[138]
    DIRECTION OUTPUT ;
    USE SIGNAL ;
    PORT
      LAYER M4 ;
        RECT  21.516 22.272 21.6 22.296 ;
    END
  END b[138]
  PIN b[139]
    DIRECTION OUTPUT ;
    USE SIGNAL ;
    PORT
      LAYER M4 ;
        RECT  21.516 22.464 21.6 22.488 ;
    END
  END b[139]
  PIN b[13]
    DIRECTION OUTPUT ;
    USE SIGNAL ;
    PORT
      LAYER M4 ;
        RECT  21.516 3.072 21.6 3.096 ;
    END
  END b[13]
  PIN b[140]
    DIRECTION OUTPUT ;
    USE SIGNAL ;
    PORT
      LAYER M4 ;
        RECT  21.516 22.608 21.6 22.632 ;
    END
  END b[140]
  PIN b[141]
    DIRECTION OUTPUT ;
    USE SIGNAL ;
    PORT
      LAYER M4 ;
        RECT  21.516 22.752 21.6 22.776 ;
    END
  END b[141]
  PIN b[142]
    DIRECTION OUTPUT ;
    USE SIGNAL ;
    PORT
      LAYER M4 ;
        RECT  21.516 22.896 21.6 22.92 ;
    END
  END b[142]
  PIN b[143]
    DIRECTION OUTPUT ;
    USE SIGNAL ;
    PORT
      LAYER M4 ;
        RECT  21.516 23.04 21.6 23.064 ;
    END
  END b[143]
  PIN b[144]
    DIRECTION OUTPUT ;
    USE SIGNAL ;
    PORT
      LAYER M4 ;
        RECT  21.516 23.232 21.6 23.256 ;
    END
  END b[144]
  PIN b[145]
    DIRECTION OUTPUT ;
    USE SIGNAL ;
    PORT
      LAYER M4 ;
        RECT  21.516 23.376 21.6 23.4 ;
    END
  END b[145]
  PIN b[146]
    DIRECTION OUTPUT ;
    USE SIGNAL ;
    PORT
      LAYER M4 ;
        RECT  21.516 23.52 21.6 23.544 ;
    END
  END b[146]
  PIN b[147]
    DIRECTION OUTPUT ;
    USE SIGNAL ;
    PORT
      LAYER M4 ;
        RECT  21.516 23.664 21.6 23.688 ;
    END
  END b[147]
  PIN b[148]
    DIRECTION OUTPUT ;
    USE SIGNAL ;
    PORT
      LAYER M4 ;
        RECT  21.516 23.808 21.6 23.832 ;
    END
  END b[148]
  PIN b[149]
    DIRECTION OUTPUT ;
    USE SIGNAL ;
    PORT
      LAYER M4 ;
        RECT  21.516 24 21.6 24.024 ;
    END
  END b[149]
  PIN b[14]
    DIRECTION OUTPUT ;
    USE SIGNAL ;
    PORT
      LAYER M4 ;
        RECT  21.516 3.216 21.6 3.24 ;
    END
  END b[14]
  PIN b[150]
    DIRECTION OUTPUT ;
    USE SIGNAL ;
    PORT
      LAYER M4 ;
        RECT  21.516 24.144 21.6 24.168 ;
    END
  END b[150]
  PIN b[151]
    DIRECTION OUTPUT ;
    USE SIGNAL ;
    PORT
      LAYER M4 ;
        RECT  21.516 24.288 21.6 24.312 ;
    END
  END b[151]
  PIN b[152]
    DIRECTION OUTPUT ;
    USE SIGNAL ;
    PORT
      LAYER M4 ;
        RECT  21.516 24.432 21.6 24.456 ;
    END
  END b[152]
  PIN b[153]
    DIRECTION OUTPUT ;
    USE SIGNAL ;
    PORT
      LAYER M4 ;
        RECT  21.516 24.576 21.6 24.6 ;
    END
  END b[153]
  PIN b[154]
    DIRECTION OUTPUT ;
    USE SIGNAL ;
    PORT
      LAYER M4 ;
        RECT  21.516 24.768 21.6 24.792 ;
    END
  END b[154]
  PIN b[155]
    DIRECTION OUTPUT ;
    USE SIGNAL ;
    PORT
      LAYER M4 ;
        RECT  21.516 24.912 21.6 24.936 ;
    END
  END b[155]
  PIN b[156]
    DIRECTION OUTPUT ;
    USE SIGNAL ;
    PORT
      LAYER M4 ;
        RECT  21.516 25.056 21.6 25.08 ;
    END
  END b[156]
  PIN b[157]
    DIRECTION OUTPUT ;
    USE SIGNAL ;
    PORT
      LAYER M4 ;
        RECT  21.516 25.2 21.6 25.224 ;
    END
  END b[157]
  PIN b[158]
    DIRECTION OUTPUT ;
    USE SIGNAL ;
    PORT
      LAYER M4 ;
        RECT  21.516 25.344 21.6 25.368 ;
    END
  END b[158]
  PIN b[159]
    DIRECTION OUTPUT ;
    USE SIGNAL ;
    PORT
      LAYER M4 ;
        RECT  21.516 25.536 21.6 25.56 ;
    END
  END b[159]
  PIN b[15]
    DIRECTION OUTPUT ;
    USE SIGNAL ;
    PORT
      LAYER M4 ;
        RECT  21.516 3.36 21.6 3.384 ;
    END
  END b[15]
  PIN b[160]
    DIRECTION OUTPUT ;
    USE SIGNAL ;
    PORT
      LAYER M4 ;
        RECT  21.516 25.68 21.6 25.704 ;
    END
  END b[160]
  PIN b[161]
    DIRECTION OUTPUT ;
    USE SIGNAL ;
    PORT
      LAYER M4 ;
        RECT  21.516 25.824 21.6 25.848 ;
    END
  END b[161]
  PIN b[162]
    DIRECTION OUTPUT ;
    USE SIGNAL ;
    PORT
      LAYER M4 ;
        RECT  21.516 25.968 21.6 25.992 ;
    END
  END b[162]
  PIN b[163]
    DIRECTION OUTPUT ;
    USE SIGNAL ;
    PORT
      LAYER M4 ;
        RECT  21.516 26.112 21.6 26.136 ;
    END
  END b[163]
  PIN b[164]
    DIRECTION OUTPUT ;
    USE SIGNAL ;
    PORT
      LAYER M4 ;
        RECT  21.516 26.304 21.6 26.328 ;
    END
  END b[164]
  PIN b[165]
    DIRECTION OUTPUT ;
    USE SIGNAL ;
    PORT
      LAYER M4 ;
        RECT  21.516 26.448 21.6 26.472 ;
    END
  END b[165]
  PIN b[166]
    DIRECTION OUTPUT ;
    USE SIGNAL ;
    PORT
      LAYER M4 ;
        RECT  21.516 26.592 21.6 26.616 ;
    END
  END b[166]
  PIN b[167]
    DIRECTION OUTPUT ;
    USE SIGNAL ;
    PORT
      LAYER M4 ;
        RECT  21.516 26.736 21.6 26.76 ;
    END
  END b[167]
  PIN b[168]
    DIRECTION OUTPUT ;
    USE SIGNAL ;
    PORT
      LAYER M4 ;
        RECT  21.516 26.88 21.6 26.904 ;
    END
  END b[168]
  PIN b[169]
    DIRECTION OUTPUT ;
    USE SIGNAL ;
    PORT
      LAYER M4 ;
        RECT  21.516 27.072 21.6 27.096 ;
    END
  END b[169]
  PIN b[16]
    DIRECTION OUTPUT ;
    USE SIGNAL ;
    PORT
      LAYER M4 ;
        RECT  21.516 3.504 21.6 3.528 ;
    END
  END b[16]
  PIN b[170]
    DIRECTION OUTPUT ;
    USE SIGNAL ;
    PORT
      LAYER M4 ;
        RECT  21.516 27.216 21.6 27.24 ;
    END
  END b[170]
  PIN b[171]
    DIRECTION OUTPUT ;
    USE SIGNAL ;
    PORT
      LAYER M4 ;
        RECT  21.516 27.36 21.6 27.384 ;
    END
  END b[171]
  PIN b[172]
    DIRECTION OUTPUT ;
    USE SIGNAL ;
    PORT
      LAYER M4 ;
        RECT  21.516 27.504 21.6 27.528 ;
    END
  END b[172]
  PIN b[173]
    DIRECTION OUTPUT ;
    USE SIGNAL ;
    PORT
      LAYER M4 ;
        RECT  21.516 27.648 21.6 27.672 ;
    END
  END b[173]
  PIN b[174]
    DIRECTION OUTPUT ;
    USE SIGNAL ;
    PORT
      LAYER M4 ;
        RECT  21.516 27.84 21.6 27.864 ;
    END
  END b[174]
  PIN b[175]
    DIRECTION OUTPUT ;
    USE SIGNAL ;
    PORT
      LAYER M4 ;
        RECT  21.516 27.984 21.6 28.008 ;
    END
  END b[175]
  PIN b[176]
    DIRECTION OUTPUT ;
    USE SIGNAL ;
    PORT
      LAYER M4 ;
        RECT  21.516 28.128 21.6 28.152 ;
    END
  END b[176]
  PIN b[177]
    DIRECTION OUTPUT ;
    USE SIGNAL ;
    PORT
      LAYER M4 ;
        RECT  21.516 28.272 21.6 28.296 ;
    END
  END b[177]
  PIN b[178]
    DIRECTION OUTPUT ;
    USE SIGNAL ;
    PORT
      LAYER M4 ;
        RECT  21.516 28.416 21.6 28.44 ;
    END
  END b[178]
  PIN b[179]
    DIRECTION OUTPUT ;
    USE SIGNAL ;
    PORT
      LAYER M4 ;
        RECT  21.516 28.608 21.6 28.632 ;
    END
  END b[179]
  PIN b[17]
    DIRECTION OUTPUT ;
    USE SIGNAL ;
    PORT
      LAYER M4 ;
        RECT  21.516 3.696 21.6 3.72 ;
    END
  END b[17]
  PIN b[180]
    DIRECTION OUTPUT ;
    USE SIGNAL ;
    PORT
      LAYER M4 ;
        RECT  21.516 28.752 21.6 28.776 ;
    END
  END b[180]
  PIN b[181]
    DIRECTION OUTPUT ;
    USE SIGNAL ;
    PORT
      LAYER M4 ;
        RECT  21.516 28.896 21.6 28.92 ;
    END
  END b[181]
  PIN b[182]
    DIRECTION OUTPUT ;
    USE SIGNAL ;
    PORT
      LAYER M4 ;
        RECT  21.516 29.04 21.6 29.064 ;
    END
  END b[182]
  PIN b[183]
    DIRECTION OUTPUT ;
    USE SIGNAL ;
    PORT
      LAYER M4 ;
        RECT  21.516 29.184 21.6 29.208 ;
    END
  END b[183]
  PIN b[184]
    DIRECTION OUTPUT ;
    USE SIGNAL ;
    PORT
      LAYER M4 ;
        RECT  21.516 29.376 21.6 29.4 ;
    END
  END b[184]
  PIN b[185]
    DIRECTION OUTPUT ;
    USE SIGNAL ;
    PORT
      LAYER M4 ;
        RECT  21.516 29.52 21.6 29.544 ;
    END
  END b[185]
  PIN b[186]
    DIRECTION OUTPUT ;
    USE SIGNAL ;
    PORT
      LAYER M4 ;
        RECT  21.516 29.664 21.6 29.688 ;
    END
  END b[186]
  PIN b[187]
    DIRECTION OUTPUT ;
    USE SIGNAL ;
    PORT
      LAYER M4 ;
        RECT  21.516 29.808 21.6 29.832 ;
    END
  END b[187]
  PIN b[188]
    DIRECTION OUTPUT ;
    USE SIGNAL ;
    PORT
      LAYER M4 ;
        RECT  21.516 30 21.6 30.024 ;
    END
  END b[188]
  PIN b[189]
    DIRECTION OUTPUT ;
    USE SIGNAL ;
    PORT
      LAYER M4 ;
        RECT  21.516 30.144 21.6 30.168 ;
    END
  END b[189]
  PIN b[18]
    DIRECTION OUTPUT ;
    USE SIGNAL ;
    PORT
      LAYER M4 ;
        RECT  21.516 3.84 21.6 3.864 ;
    END
  END b[18]
  PIN b[190]
    DIRECTION OUTPUT ;
    USE SIGNAL ;
    PORT
      LAYER M4 ;
        RECT  21.516 30.288 21.6 30.312 ;
    END
  END b[190]
  PIN b[191]
    DIRECTION OUTPUT ;
    USE SIGNAL ;
    PORT
      LAYER M4 ;
        RECT  21.516 30.432 21.6 30.456 ;
    END
  END b[191]
  PIN b[192]
    DIRECTION OUTPUT ;
    USE SIGNAL ;
    PORT
      LAYER M4 ;
        RECT  21.516 30.576 21.6 30.6 ;
    END
  END b[192]
  PIN b[193]
    DIRECTION OUTPUT ;
    USE SIGNAL ;
    PORT
      LAYER M4 ;
        RECT  21.516 30.768 21.6 30.792 ;
    END
  END b[193]
  PIN b[194]
    DIRECTION OUTPUT ;
    USE SIGNAL ;
    PORT
      LAYER M4 ;
        RECT  21.516 30.912 21.6 30.936 ;
    END
  END b[194]
  PIN b[195]
    DIRECTION OUTPUT ;
    USE SIGNAL ;
    PORT
      LAYER M4 ;
        RECT  21.516 31.056 21.6 31.08 ;
    END
  END b[195]
  PIN b[196]
    DIRECTION OUTPUT ;
    USE SIGNAL ;
    PORT
      LAYER M4 ;
        RECT  21.516 31.2 21.6 31.224 ;
    END
  END b[196]
  PIN b[197]
    DIRECTION OUTPUT ;
    USE SIGNAL ;
    PORT
      LAYER M4 ;
        RECT  21.516 31.344 21.6 31.368 ;
    END
  END b[197]
  PIN b[198]
    DIRECTION OUTPUT ;
    USE SIGNAL ;
    PORT
      LAYER M4 ;
        RECT  21.516 31.536 21.6 31.56 ;
    END
  END b[198]
  PIN b[199]
    DIRECTION OUTPUT ;
    USE SIGNAL ;
    PORT
      LAYER M4 ;
        RECT  21.516 31.68 21.6 31.704 ;
    END
  END b[199]
  PIN b[19]
    DIRECTION OUTPUT ;
    USE SIGNAL ;
    PORT
      LAYER M4 ;
        RECT  21.516 3.984 21.6 4.008 ;
    END
  END b[19]
  PIN b[1]
    DIRECTION OUTPUT ;
    USE SIGNAL ;
    PORT
      LAYER M4 ;
        RECT  21.516 1.2 21.6 1.224 ;
    END
  END b[1]
  PIN b[200]
    DIRECTION OUTPUT ;
    USE SIGNAL ;
    PORT
      LAYER M4 ;
        RECT  21.516 31.824 21.6 31.848 ;
    END
  END b[200]
  PIN b[201]
    DIRECTION OUTPUT ;
    USE SIGNAL ;
    PORT
      LAYER M4 ;
        RECT  21.516 31.968 21.6 31.992 ;
    END
  END b[201]
  PIN b[202]
    DIRECTION OUTPUT ;
    USE SIGNAL ;
    PORT
      LAYER M4 ;
        RECT  21.516 32.112 21.6 32.136 ;
    END
  END b[202]
  PIN b[203]
    DIRECTION OUTPUT ;
    USE SIGNAL ;
    PORT
      LAYER M4 ;
        RECT  21.516 32.304 21.6 32.328 ;
    END
  END b[203]
  PIN b[204]
    DIRECTION OUTPUT ;
    USE SIGNAL ;
    PORT
      LAYER M4 ;
        RECT  21.516 32.448 21.6 32.472 ;
    END
  END b[204]
  PIN b[205]
    DIRECTION OUTPUT ;
    USE SIGNAL ;
    PORT
      LAYER M4 ;
        RECT  21.516 32.592 21.6 32.616 ;
    END
  END b[205]
  PIN b[206]
    DIRECTION OUTPUT ;
    USE SIGNAL ;
    PORT
      LAYER M4 ;
        RECT  21.516 32.736 21.6 32.76 ;
    END
  END b[206]
  PIN b[207]
    DIRECTION OUTPUT ;
    USE SIGNAL ;
    PORT
      LAYER M4 ;
        RECT  21.516 32.88 21.6 32.904 ;
    END
  END b[207]
  PIN b[208]
    DIRECTION OUTPUT ;
    USE SIGNAL ;
    PORT
      LAYER M4 ;
        RECT  21.516 33.072 21.6 33.096 ;
    END
  END b[208]
  PIN b[209]
    DIRECTION OUTPUT ;
    USE SIGNAL ;
    PORT
      LAYER M4 ;
        RECT  21.516 33.216 21.6 33.24 ;
    END
  END b[209]
  PIN b[20]
    DIRECTION OUTPUT ;
    USE SIGNAL ;
    PORT
      LAYER M4 ;
        RECT  21.516 4.128 21.6 4.152 ;
    END
  END b[20]
  PIN b[210]
    DIRECTION OUTPUT ;
    USE SIGNAL ;
    PORT
      LAYER M4 ;
        RECT  21.516 33.36 21.6 33.384 ;
    END
  END b[210]
  PIN b[211]
    DIRECTION OUTPUT ;
    USE SIGNAL ;
    PORT
      LAYER M4 ;
        RECT  21.516 33.504 21.6 33.528 ;
    END
  END b[211]
  PIN b[212]
    DIRECTION OUTPUT ;
    USE SIGNAL ;
    PORT
      LAYER M4 ;
        RECT  21.516 33.648 21.6 33.672 ;
    END
  END b[212]
  PIN b[213]
    DIRECTION OUTPUT ;
    USE SIGNAL ;
    PORT
      LAYER M4 ;
        RECT  21.516 33.84 21.6 33.864 ;
    END
  END b[213]
  PIN b[214]
    DIRECTION OUTPUT ;
    USE SIGNAL ;
    PORT
      LAYER M4 ;
        RECT  21.516 33.984 21.6 34.008 ;
    END
  END b[214]
  PIN b[215]
    DIRECTION OUTPUT ;
    USE SIGNAL ;
    PORT
      LAYER M4 ;
        RECT  21.516 34.128 21.6 34.152 ;
    END
  END b[215]
  PIN b[216]
    DIRECTION OUTPUT ;
    USE SIGNAL ;
    PORT
      LAYER M4 ;
        RECT  21.516 34.272 21.6 34.296 ;
    END
  END b[216]
  PIN b[217]
    DIRECTION OUTPUT ;
    USE SIGNAL ;
    PORT
      LAYER M4 ;
        RECT  21.516 34.416 21.6 34.44 ;
    END
  END b[217]
  PIN b[218]
    DIRECTION OUTPUT ;
    USE SIGNAL ;
    PORT
      LAYER M4 ;
        RECT  21.516 34.608 21.6 34.632 ;
    END
  END b[218]
  PIN b[219]
    DIRECTION OUTPUT ;
    USE SIGNAL ;
    PORT
      LAYER M4 ;
        RECT  21.516 34.752 21.6 34.776 ;
    END
  END b[219]
  PIN b[21]
    DIRECTION OUTPUT ;
    USE SIGNAL ;
    PORT
      LAYER M4 ;
        RECT  21.516 4.272 21.6 4.296 ;
    END
  END b[21]
  PIN b[220]
    DIRECTION OUTPUT ;
    USE SIGNAL ;
    PORT
      LAYER M4 ;
        RECT  21.516 34.896 21.6 34.92 ;
    END
  END b[220]
  PIN b[221]
    DIRECTION OUTPUT ;
    USE SIGNAL ;
    PORT
      LAYER M4 ;
        RECT  21.516 35.04 21.6 35.064 ;
    END
  END b[221]
  PIN b[222]
    DIRECTION OUTPUT ;
    USE SIGNAL ;
    PORT
      LAYER M4 ;
        RECT  21.516 35.184 21.6 35.208 ;
    END
  END b[222]
  PIN b[223]
    DIRECTION OUTPUT ;
    USE SIGNAL ;
    PORT
      LAYER M4 ;
        RECT  21.516 35.376 21.6 35.4 ;
    END
  END b[223]
  PIN b[224]
    DIRECTION OUTPUT ;
    USE SIGNAL ;
    PORT
      LAYER M4 ;
        RECT  21.516 35.52 21.6 35.544 ;
    END
  END b[224]
  PIN b[225]
    DIRECTION OUTPUT ;
    USE SIGNAL ;
    PORT
      LAYER M4 ;
        RECT  21.516 35.664 21.6 35.688 ;
    END
  END b[225]
  PIN b[226]
    DIRECTION OUTPUT ;
    USE SIGNAL ;
    PORT
      LAYER M4 ;
        RECT  21.516 35.808 21.6 35.832 ;
    END
  END b[226]
  PIN b[227]
    DIRECTION OUTPUT ;
    USE SIGNAL ;
    PORT
      LAYER M4 ;
        RECT  21.516 35.952 21.6 35.976 ;
    END
  END b[227]
  PIN b[228]
    DIRECTION OUTPUT ;
    USE SIGNAL ;
    PORT
      LAYER M4 ;
        RECT  21.516 36.144 21.6 36.168 ;
    END
  END b[228]
  PIN b[229]
    DIRECTION OUTPUT ;
    USE SIGNAL ;
    PORT
      LAYER M4 ;
        RECT  21.516 36.288 21.6 36.312 ;
    END
  END b[229]
  PIN b[22]
    DIRECTION OUTPUT ;
    USE SIGNAL ;
    PORT
      LAYER M4 ;
        RECT  21.516 4.464 21.6 4.488 ;
    END
  END b[22]
  PIN b[230]
    DIRECTION OUTPUT ;
    USE SIGNAL ;
    PORT
      LAYER M4 ;
        RECT  21.516 36.432 21.6 36.456 ;
    END
  END b[230]
  PIN b[231]
    DIRECTION OUTPUT ;
    USE SIGNAL ;
    PORT
      LAYER M4 ;
        RECT  21.516 36.576 21.6 36.6 ;
    END
  END b[231]
  PIN b[232]
    DIRECTION OUTPUT ;
    USE SIGNAL ;
    PORT
      LAYER M4 ;
        RECT  21.516 36.72 21.6 36.744 ;
    END
  END b[232]
  PIN b[233]
    DIRECTION OUTPUT ;
    USE SIGNAL ;
    PORT
      LAYER M4 ;
        RECT  21.516 36.912 21.6 36.936 ;
    END
  END b[233]
  PIN b[234]
    DIRECTION OUTPUT ;
    USE SIGNAL ;
    PORT
      LAYER M4 ;
        RECT  21.516 37.056 21.6 37.08 ;
    END
  END b[234]
  PIN b[235]
    DIRECTION OUTPUT ;
    USE SIGNAL ;
    PORT
      LAYER M4 ;
        RECT  21.516 37.2 21.6 37.224 ;
    END
  END b[235]
  PIN b[236]
    DIRECTION OUTPUT ;
    USE SIGNAL ;
    PORT
      LAYER M4 ;
        RECT  21.516 37.344 21.6 37.368 ;
    END
  END b[236]
  PIN b[237]
    DIRECTION OUTPUT ;
    USE SIGNAL ;
    PORT
      LAYER M4 ;
        RECT  21.516 37.536 21.6 37.56 ;
    END
  END b[237]
  PIN b[238]
    DIRECTION OUTPUT ;
    USE SIGNAL ;
    PORT
      LAYER M4 ;
        RECT  21.516 37.68 21.6 37.704 ;
    END
  END b[238]
  PIN b[239]
    DIRECTION OUTPUT ;
    USE SIGNAL ;
    PORT
      LAYER M4 ;
        RECT  21.516 37.824 21.6 37.848 ;
    END
  END b[239]
  PIN b[23]
    DIRECTION OUTPUT ;
    USE SIGNAL ;
    PORT
      LAYER M4 ;
        RECT  21.516 4.608 21.6 4.632 ;
    END
  END b[23]
  PIN b[240]
    DIRECTION OUTPUT ;
    USE SIGNAL ;
    PORT
      LAYER M4 ;
        RECT  21.516 37.968 21.6 37.992 ;
    END
  END b[240]
  PIN b[241]
    DIRECTION OUTPUT ;
    USE SIGNAL ;
    PORT
      LAYER M4 ;
        RECT  21.516 38.112 21.6 38.136 ;
    END
  END b[241]
  PIN b[242]
    DIRECTION OUTPUT ;
    USE SIGNAL ;
    PORT
      LAYER M4 ;
        RECT  21.516 38.304 21.6 38.328 ;
    END
  END b[242]
  PIN b[243]
    DIRECTION OUTPUT ;
    USE SIGNAL ;
    PORT
      LAYER M4 ;
        RECT  21.516 38.448 21.6 38.472 ;
    END
  END b[243]
  PIN b[244]
    DIRECTION OUTPUT ;
    USE SIGNAL ;
    PORT
      LAYER M4 ;
        RECT  21.516 38.592 21.6 38.616 ;
    END
  END b[244]
  PIN b[245]
    DIRECTION OUTPUT ;
    USE SIGNAL ;
    PORT
      LAYER M4 ;
        RECT  21.516 38.736 21.6 38.76 ;
    END
  END b[245]
  PIN b[246]
    DIRECTION OUTPUT ;
    USE SIGNAL ;
    PORT
      LAYER M4 ;
        RECT  21.516 38.88 21.6 38.904 ;
    END
  END b[246]
  PIN b[247]
    DIRECTION OUTPUT ;
    USE SIGNAL ;
    PORT
      LAYER M4 ;
        RECT  21.516 39.072 21.6 39.096 ;
    END
  END b[247]
  PIN b[248]
    DIRECTION OUTPUT ;
    USE SIGNAL ;
    PORT
      LAYER M4 ;
        RECT  21.516 39.216 21.6 39.24 ;
    END
  END b[248]
  PIN b[249]
    DIRECTION OUTPUT ;
    USE SIGNAL ;
    PORT
      LAYER M4 ;
        RECT  21.516 39.36 21.6 39.384 ;
    END
  END b[249]
  PIN b[24]
    DIRECTION OUTPUT ;
    USE SIGNAL ;
    PORT
      LAYER M4 ;
        RECT  21.516 4.752 21.6 4.776 ;
    END
  END b[24]
  PIN b[250]
    DIRECTION OUTPUT ;
    USE SIGNAL ;
    PORT
      LAYER M4 ;
        RECT  21.516 39.504 21.6 39.528 ;
    END
  END b[250]
  PIN b[251]
    DIRECTION OUTPUT ;
    USE SIGNAL ;
    PORT
      LAYER M4 ;
        RECT  21.516 39.648 21.6 39.672 ;
    END
  END b[251]
  PIN b[252]
    DIRECTION OUTPUT ;
    USE SIGNAL ;
    PORT
      LAYER M4 ;
        RECT  21.516 39.84 21.6 39.864 ;
    END
  END b[252]
  PIN b[253]
    DIRECTION OUTPUT ;
    USE SIGNAL ;
    PORT
      LAYER M4 ;
        RECT  21.516 39.984 21.6 40.008 ;
    END
  END b[253]
  PIN b[254]
    DIRECTION OUTPUT ;
    USE SIGNAL ;
    PORT
      LAYER M4 ;
        RECT  21.516 40.128 21.6 40.152 ;
    END
  END b[254]
  PIN b[255]
    DIRECTION OUTPUT ;
    USE SIGNAL ;
    PORT
      LAYER M4 ;
        RECT  21.516 40.272 21.6 40.296 ;
    END
  END b[255]
  PIN b[256]
    DIRECTION OUTPUT ;
    USE SIGNAL ;
    PORT
      LAYER M4 ;
        RECT  21.516 40.416 21.6 40.44 ;
    END
  END b[256]
  PIN b[257]
    DIRECTION OUTPUT ;
    USE SIGNAL ;
    PORT
      LAYER M4 ;
        RECT  21.516 40.608 21.6 40.632 ;
    END
  END b[257]
  PIN b[258]
    DIRECTION OUTPUT ;
    USE SIGNAL ;
    PORT
      LAYER M4 ;
        RECT  21.516 40.752 21.6 40.776 ;
    END
  END b[258]
  PIN b[259]
    DIRECTION OUTPUT ;
    USE SIGNAL ;
    PORT
      LAYER M4 ;
        RECT  21.516 40.896 21.6 40.92 ;
    END
  END b[259]
  PIN b[25]
    DIRECTION OUTPUT ;
    USE SIGNAL ;
    PORT
      LAYER M4 ;
        RECT  21.516 4.896 21.6 4.92 ;
    END
  END b[25]
  PIN b[260]
    DIRECTION OUTPUT ;
    USE SIGNAL ;
    PORT
      LAYER M4 ;
        RECT  21.516 41.04 21.6 41.064 ;
    END
  END b[260]
  PIN b[261]
    DIRECTION OUTPUT ;
    USE SIGNAL ;
    PORT
      LAYER M4 ;
        RECT  21.516 41.184 21.6 41.208 ;
    END
  END b[261]
  PIN b[262]
    DIRECTION OUTPUT ;
    USE SIGNAL ;
    PORT
      LAYER M4 ;
        RECT  21.516 41.376 21.6 41.4 ;
    END
  END b[262]
  PIN b[263]
    DIRECTION OUTPUT ;
    USE SIGNAL ;
    PORT
      LAYER M4 ;
        RECT  21.516 41.52 21.6 41.544 ;
    END
  END b[263]
  PIN b[264]
    DIRECTION OUTPUT ;
    USE SIGNAL ;
    PORT
      LAYER M4 ;
        RECT  21.516 41.664 21.6 41.688 ;
    END
  END b[264]
  PIN b[265]
    DIRECTION OUTPUT ;
    USE SIGNAL ;
    PORT
      LAYER M4 ;
        RECT  21.516 41.808 21.6 41.832 ;
    END
  END b[265]
  PIN b[266]
    DIRECTION OUTPUT ;
    USE SIGNAL ;
    PORT
      LAYER M4 ;
        RECT  21.516 41.952 21.6 41.976 ;
    END
  END b[266]
  PIN b[267]
    DIRECTION OUTPUT ;
    USE SIGNAL ;
    PORT
      LAYER M4 ;
        RECT  21.516 42.144 21.6 42.168 ;
    END
  END b[267]
  PIN b[268]
    DIRECTION OUTPUT ;
    USE SIGNAL ;
    PORT
      LAYER M4 ;
        RECT  21.516 42.288 21.6 42.312 ;
    END
  END b[268]
  PIN b[269]
    DIRECTION OUTPUT ;
    USE SIGNAL ;
    PORT
      LAYER M4 ;
        RECT  21.516 42.432 21.6 42.456 ;
    END
  END b[269]
  PIN b[26]
    DIRECTION OUTPUT ;
    USE SIGNAL ;
    PORT
      LAYER M4 ;
        RECT  21.516 5.04 21.6 5.064 ;
    END
  END b[26]
  PIN b[270]
    DIRECTION OUTPUT ;
    USE SIGNAL ;
    PORT
      LAYER M4 ;
        RECT  21.516 42.576 21.6 42.6 ;
    END
  END b[270]
  PIN b[271]
    DIRECTION OUTPUT ;
    USE SIGNAL ;
    PORT
      LAYER M4 ;
        RECT  21.516 42.72 21.6 42.744 ;
    END
  END b[271]
  PIN b[272]
    DIRECTION OUTPUT ;
    USE SIGNAL ;
    PORT
      LAYER M4 ;
        RECT  21.516 42.912 21.6 42.936 ;
    END
  END b[272]
  PIN b[273]
    DIRECTION OUTPUT ;
    USE SIGNAL ;
    PORT
      LAYER M4 ;
        RECT  21.516 43.056 21.6 43.08 ;
    END
  END b[273]
  PIN b[274]
    DIRECTION OUTPUT ;
    USE SIGNAL ;
    PORT
      LAYER M4 ;
        RECT  21.516 43.2 21.6 43.224 ;
    END
  END b[274]
  PIN b[275]
    DIRECTION OUTPUT ;
    USE SIGNAL ;
    PORT
      LAYER M4 ;
        RECT  21.516 43.344 21.6 43.368 ;
    END
  END b[275]
  PIN b[276]
    DIRECTION OUTPUT ;
    USE SIGNAL ;
    PORT
      LAYER M4 ;
        RECT  21.516 43.488 21.6 43.512 ;
    END
  END b[276]
  PIN b[277]
    DIRECTION OUTPUT ;
    USE SIGNAL ;
    PORT
      LAYER M4 ;
        RECT  21.516 43.68 21.6 43.704 ;
    END
  END b[277]
  PIN b[278]
    DIRECTION OUTPUT ;
    USE SIGNAL ;
    PORT
      LAYER M4 ;
        RECT  21.516 43.824 21.6 43.848 ;
    END
  END b[278]
  PIN b[279]
    DIRECTION OUTPUT ;
    USE SIGNAL ;
    PORT
      LAYER M4 ;
        RECT  21.516 43.968 21.6 43.992 ;
    END
  END b[279]
  PIN b[27]
    DIRECTION OUTPUT ;
    USE SIGNAL ;
    PORT
      LAYER M4 ;
        RECT  21.516 5.232 21.6 5.256 ;
    END
  END b[27]
  PIN b[280]
    DIRECTION OUTPUT ;
    USE SIGNAL ;
    PORT
      LAYER M4 ;
        RECT  21.516 44.112 21.6 44.136 ;
    END
  END b[280]
  PIN b[281]
    DIRECTION OUTPUT ;
    USE SIGNAL ;
    PORT
      LAYER M4 ;
        RECT  21.516 44.256 21.6 44.28 ;
    END
  END b[281]
  PIN b[282]
    DIRECTION OUTPUT ;
    USE SIGNAL ;
    PORT
      LAYER M4 ;
        RECT  21.516 44.448 21.6 44.472 ;
    END
  END b[282]
  PIN b[283]
    DIRECTION OUTPUT ;
    USE SIGNAL ;
    PORT
      LAYER M4 ;
        RECT  21.516 44.592 21.6 44.616 ;
    END
  END b[283]
  PIN b[284]
    DIRECTION OUTPUT ;
    USE SIGNAL ;
    PORT
      LAYER M4 ;
        RECT  21.516 44.736 21.6 44.76 ;
    END
  END b[284]
  PIN b[285]
    DIRECTION OUTPUT ;
    USE SIGNAL ;
    PORT
      LAYER M4 ;
        RECT  21.516 44.88 21.6 44.904 ;
    END
  END b[285]
  PIN b[286]
    DIRECTION OUTPUT ;
    USE SIGNAL ;
    PORT
      LAYER M4 ;
        RECT  21.516 45.024 21.6 45.048 ;
    END
  END b[286]
  PIN b[287]
    DIRECTION OUTPUT ;
    USE SIGNAL ;
    PORT
      LAYER M4 ;
        RECT  21.516 45.216 21.6 45.24 ;
    END
  END b[287]
  PIN b[288]
    DIRECTION OUTPUT ;
    USE SIGNAL ;
    PORT
      LAYER M4 ;
        RECT  21.516 45.36 21.6 45.384 ;
    END
  END b[288]
  PIN b[289]
    DIRECTION OUTPUT ;
    USE SIGNAL ;
    PORT
      LAYER M4 ;
        RECT  21.516 45.504 21.6 45.528 ;
    END
  END b[289]
  PIN b[28]
    DIRECTION OUTPUT ;
    USE SIGNAL ;
    PORT
      LAYER M4 ;
        RECT  21.516 5.376 21.6 5.4 ;
    END
  END b[28]
  PIN b[290]
    DIRECTION OUTPUT ;
    USE SIGNAL ;
    PORT
      LAYER M4 ;
        RECT  21.516 45.648 21.6 45.672 ;
    END
  END b[290]
  PIN b[291]
    DIRECTION OUTPUT ;
    USE SIGNAL ;
    PORT
      LAYER M4 ;
        RECT  21.516 45.84 21.6 45.864 ;
    END
  END b[291]
  PIN b[292]
    DIRECTION OUTPUT ;
    USE SIGNAL ;
    PORT
      LAYER M4 ;
        RECT  21.516 45.984 21.6 46.008 ;
    END
  END b[292]
  PIN b[293]
    DIRECTION OUTPUT ;
    USE SIGNAL ;
    PORT
      LAYER M4 ;
        RECT  21.516 46.128 21.6 46.152 ;
    END
  END b[293]
  PIN b[294]
    DIRECTION OUTPUT ;
    USE SIGNAL ;
    PORT
      LAYER M4 ;
        RECT  21.516 46.272 21.6 46.296 ;
    END
  END b[294]
  PIN b[295]
    DIRECTION OUTPUT ;
    USE SIGNAL ;
    PORT
      LAYER M4 ;
        RECT  21.516 46.416 21.6 46.44 ;
    END
  END b[295]
  PIN b[29]
    DIRECTION OUTPUT ;
    USE SIGNAL ;
    PORT
      LAYER M4 ;
        RECT  21.516 5.52 21.6 5.544 ;
    END
  END b[29]
  PIN b[2]
    DIRECTION OUTPUT ;
    USE SIGNAL ;
    PORT
      LAYER M4 ;
        RECT  21.516 1.392 21.6 1.416 ;
    END
  END b[2]
  PIN b[30]
    DIRECTION OUTPUT ;
    USE SIGNAL ;
    PORT
      LAYER M4 ;
        RECT  21.516 5.664 21.6 5.688 ;
    END
  END b[30]
  PIN b[31]
    DIRECTION OUTPUT ;
    USE SIGNAL ;
    PORT
      LAYER M4 ;
        RECT  21.516 5.856 21.6 5.88 ;
    END
  END b[31]
  PIN b[32]
    DIRECTION OUTPUT ;
    USE SIGNAL ;
    PORT
      LAYER M4 ;
        RECT  21.516 6 21.6 6.024 ;
    END
  END b[32]
  PIN b[33]
    DIRECTION OUTPUT ;
    USE SIGNAL ;
    PORT
      LAYER M4 ;
        RECT  21.516 6.144 21.6 6.168 ;
    END
  END b[33]
  PIN b[34]
    DIRECTION OUTPUT ;
    USE SIGNAL ;
    PORT
      LAYER M4 ;
        RECT  21.516 6.288 21.6 6.312 ;
    END
  END b[34]
  PIN b[35]
    DIRECTION OUTPUT ;
    USE SIGNAL ;
    PORT
      LAYER M4 ;
        RECT  21.516 6.432 21.6 6.456 ;
    END
  END b[35]
  PIN b[36]
    DIRECTION OUTPUT ;
    USE SIGNAL ;
    PORT
      LAYER M4 ;
        RECT  21.516 6.624 21.6 6.648 ;
    END
  END b[36]
  PIN b[37]
    DIRECTION OUTPUT ;
    USE SIGNAL ;
    PORT
      LAYER M4 ;
        RECT  21.516 6.768 21.6 6.792 ;
    END
  END b[37]
  PIN b[38]
    DIRECTION OUTPUT ;
    USE SIGNAL ;
    PORT
      LAYER M4 ;
        RECT  21.516 6.912 21.6 6.936 ;
    END
  END b[38]
  PIN b[39]
    DIRECTION OUTPUT ;
    USE SIGNAL ;
    PORT
      LAYER M4 ;
        RECT  21.516 7.056 21.6 7.08 ;
    END
  END b[39]
  PIN b[3]
    DIRECTION OUTPUT ;
    USE SIGNAL ;
    PORT
      LAYER M4 ;
        RECT  21.516 1.536 21.6 1.56 ;
    END
  END b[3]
  PIN b[40]
    DIRECTION OUTPUT ;
    USE SIGNAL ;
    PORT
      LAYER M4 ;
        RECT  21.516 7.2 21.6 7.224 ;
    END
  END b[40]
  PIN b[41]
    DIRECTION OUTPUT ;
    USE SIGNAL ;
    PORT
      LAYER M4 ;
        RECT  21.516 7.392 21.6 7.416 ;
    END
  END b[41]
  PIN b[42]
    DIRECTION OUTPUT ;
    USE SIGNAL ;
    PORT
      LAYER M4 ;
        RECT  21.516 7.536 21.6 7.56 ;
    END
  END b[42]
  PIN b[43]
    DIRECTION OUTPUT ;
    USE SIGNAL ;
    PORT
      LAYER M4 ;
        RECT  21.516 7.68 21.6 7.704 ;
    END
  END b[43]
  PIN b[44]
    DIRECTION OUTPUT ;
    USE SIGNAL ;
    PORT
      LAYER M4 ;
        RECT  21.516 7.824 21.6 7.848 ;
    END
  END b[44]
  PIN b[45]
    DIRECTION OUTPUT ;
    USE SIGNAL ;
    PORT
      LAYER M4 ;
        RECT  21.516 7.968 21.6 7.992 ;
    END
  END b[45]
  PIN b[46]
    DIRECTION OUTPUT ;
    USE SIGNAL ;
    PORT
      LAYER M4 ;
        RECT  21.516 8.16 21.6 8.184 ;
    END
  END b[46]
  PIN b[47]
    DIRECTION OUTPUT ;
    USE SIGNAL ;
    PORT
      LAYER M4 ;
        RECT  21.516 8.304 21.6 8.328 ;
    END
  END b[47]
  PIN b[48]
    DIRECTION OUTPUT ;
    USE SIGNAL ;
    PORT
      LAYER M4 ;
        RECT  21.516 8.448 21.6 8.472 ;
    END
  END b[48]
  PIN b[49]
    DIRECTION OUTPUT ;
    USE SIGNAL ;
    PORT
      LAYER M4 ;
        RECT  21.516 8.592 21.6 8.616 ;
    END
  END b[49]
  PIN b[4]
    DIRECTION OUTPUT ;
    USE SIGNAL ;
    PORT
      LAYER M4 ;
        RECT  21.516 1.68 21.6 1.704 ;
    END
  END b[4]
  PIN b[50]
    DIRECTION OUTPUT ;
    USE SIGNAL ;
    PORT
      LAYER M4 ;
        RECT  21.516 8.736 21.6 8.76 ;
    END
  END b[50]
  PIN b[51]
    DIRECTION OUTPUT ;
    USE SIGNAL ;
    PORT
      LAYER M4 ;
        RECT  21.516 8.928 21.6 8.952 ;
    END
  END b[51]
  PIN b[52]
    DIRECTION OUTPUT ;
    USE SIGNAL ;
    PORT
      LAYER M4 ;
        RECT  21.516 9.072 21.6 9.096 ;
    END
  END b[52]
  PIN b[53]
    DIRECTION OUTPUT ;
    USE SIGNAL ;
    PORT
      LAYER M4 ;
        RECT  21.516 9.216 21.6 9.24 ;
    END
  END b[53]
  PIN b[54]
    DIRECTION OUTPUT ;
    USE SIGNAL ;
    PORT
      LAYER M4 ;
        RECT  21.516 9.36 21.6 9.384 ;
    END
  END b[54]
  PIN b[55]
    DIRECTION OUTPUT ;
    USE SIGNAL ;
    PORT
      LAYER M4 ;
        RECT  21.516 9.504 21.6 9.528 ;
    END
  END b[55]
  PIN b[56]
    DIRECTION OUTPUT ;
    USE SIGNAL ;
    PORT
      LAYER M4 ;
        RECT  21.516 9.696 21.6 9.72 ;
    END
  END b[56]
  PIN b[57]
    DIRECTION OUTPUT ;
    USE SIGNAL ;
    PORT
      LAYER M4 ;
        RECT  21.516 9.84 21.6 9.864 ;
    END
  END b[57]
  PIN b[58]
    DIRECTION OUTPUT ;
    USE SIGNAL ;
    PORT
      LAYER M4 ;
        RECT  21.516 9.984 21.6 10.008 ;
    END
  END b[58]
  PIN b[59]
    DIRECTION OUTPUT ;
    USE SIGNAL ;
    PORT
      LAYER M4 ;
        RECT  21.516 10.128 21.6 10.152 ;
    END
  END b[59]
  PIN b[5]
    DIRECTION OUTPUT ;
    USE SIGNAL ;
    PORT
      LAYER M4 ;
        RECT  21.516 1.824 21.6 1.848 ;
    END
  END b[5]
  PIN b[60]
    DIRECTION OUTPUT ;
    USE SIGNAL ;
    PORT
      LAYER M4 ;
        RECT  21.516 10.272 21.6 10.296 ;
    END
  END b[60]
  PIN b[61]
    DIRECTION OUTPUT ;
    USE SIGNAL ;
    PORT
      LAYER M4 ;
        RECT  21.516 10.464 21.6 10.488 ;
    END
  END b[61]
  PIN b[62]
    DIRECTION OUTPUT ;
    USE SIGNAL ;
    PORT
      LAYER M4 ;
        RECT  21.516 10.608 21.6 10.632 ;
    END
  END b[62]
  PIN b[63]
    DIRECTION OUTPUT ;
    USE SIGNAL ;
    PORT
      LAYER M4 ;
        RECT  21.516 10.752 21.6 10.776 ;
    END
  END b[63]
  PIN b[64]
    DIRECTION OUTPUT ;
    USE SIGNAL ;
    PORT
      LAYER M4 ;
        RECT  21.516 10.896 21.6 10.92 ;
    END
  END b[64]
  PIN b[65]
    DIRECTION OUTPUT ;
    USE SIGNAL ;
    PORT
      LAYER M4 ;
        RECT  21.516 11.04 21.6 11.064 ;
    END
  END b[65]
  PIN b[66]
    DIRECTION OUTPUT ;
    USE SIGNAL ;
    PORT
      LAYER M4 ;
        RECT  21.516 11.232 21.6 11.256 ;
    END
  END b[66]
  PIN b[67]
    DIRECTION OUTPUT ;
    USE SIGNAL ;
    PORT
      LAYER M4 ;
        RECT  21.516 11.376 21.6 11.4 ;
    END
  END b[67]
  PIN b[68]
    DIRECTION OUTPUT ;
    USE SIGNAL ;
    PORT
      LAYER M4 ;
        RECT  21.516 11.52 21.6 11.544 ;
    END
  END b[68]
  PIN b[69]
    DIRECTION OUTPUT ;
    USE SIGNAL ;
    PORT
      LAYER M4 ;
        RECT  21.516 11.664 21.6 11.688 ;
    END
  END b[69]
  PIN b[6]
    DIRECTION OUTPUT ;
    USE SIGNAL ;
    PORT
      LAYER M4 ;
        RECT  21.516 1.968 21.6 1.992 ;
    END
  END b[6]
  PIN b[70]
    DIRECTION OUTPUT ;
    USE SIGNAL ;
    PORT
      LAYER M4 ;
        RECT  21.516 11.808 21.6 11.832 ;
    END
  END b[70]
  PIN b[71]
    DIRECTION OUTPUT ;
    USE SIGNAL ;
    PORT
      LAYER M4 ;
        RECT  21.516 12 21.6 12.024 ;
    END
  END b[71]
  PIN b[72]
    DIRECTION OUTPUT ;
    USE SIGNAL ;
    PORT
      LAYER M4 ;
        RECT  21.516 12.144 21.6 12.168 ;
    END
  END b[72]
  PIN b[73]
    DIRECTION OUTPUT ;
    USE SIGNAL ;
    PORT
      LAYER M4 ;
        RECT  21.516 12.288 21.6 12.312 ;
    END
  END b[73]
  PIN b[74]
    DIRECTION OUTPUT ;
    USE SIGNAL ;
    PORT
      LAYER M4 ;
        RECT  21.516 12.432 21.6 12.456 ;
    END
  END b[74]
  PIN b[75]
    DIRECTION OUTPUT ;
    USE SIGNAL ;
    PORT
      LAYER M4 ;
        RECT  21.516 12.576 21.6 12.6 ;
    END
  END b[75]
  PIN b[76]
    DIRECTION OUTPUT ;
    USE SIGNAL ;
    PORT
      LAYER M4 ;
        RECT  21.516 12.768 21.6 12.792 ;
    END
  END b[76]
  PIN b[77]
    DIRECTION OUTPUT ;
    USE SIGNAL ;
    PORT
      LAYER M4 ;
        RECT  21.516 12.912 21.6 12.936 ;
    END
  END b[77]
  PIN b[78]
    DIRECTION OUTPUT ;
    USE SIGNAL ;
    PORT
      LAYER M4 ;
        RECT  21.516 13.056 21.6 13.08 ;
    END
  END b[78]
  PIN b[79]
    DIRECTION OUTPUT ;
    USE SIGNAL ;
    PORT
      LAYER M4 ;
        RECT  21.516 13.2 21.6 13.224 ;
    END
  END b[79]
  PIN b[7]
    DIRECTION OUTPUT ;
    USE SIGNAL ;
    PORT
      LAYER M4 ;
        RECT  21.516 2.16 21.6 2.184 ;
    END
  END b[7]
  PIN b[80]
    DIRECTION OUTPUT ;
    USE SIGNAL ;
    PORT
      LAYER M4 ;
        RECT  21.516 13.392 21.6 13.416 ;
    END
  END b[80]
  PIN b[81]
    DIRECTION OUTPUT ;
    USE SIGNAL ;
    PORT
      LAYER M4 ;
        RECT  21.516 13.536 21.6 13.56 ;
    END
  END b[81]
  PIN b[82]
    DIRECTION OUTPUT ;
    USE SIGNAL ;
    PORT
      LAYER M4 ;
        RECT  21.516 13.68 21.6 13.704 ;
    END
  END b[82]
  PIN b[83]
    DIRECTION OUTPUT ;
    USE SIGNAL ;
    PORT
      LAYER M4 ;
        RECT  21.516 13.824 21.6 13.848 ;
    END
  END b[83]
  PIN b[84]
    DIRECTION OUTPUT ;
    USE SIGNAL ;
    PORT
      LAYER M4 ;
        RECT  21.516 13.968 21.6 13.992 ;
    END
  END b[84]
  PIN b[85]
    DIRECTION OUTPUT ;
    USE SIGNAL ;
    PORT
      LAYER M4 ;
        RECT  21.516 14.16 21.6 14.184 ;
    END
  END b[85]
  PIN b[86]
    DIRECTION OUTPUT ;
    USE SIGNAL ;
    PORT
      LAYER M4 ;
        RECT  21.516 14.304 21.6 14.328 ;
    END
  END b[86]
  PIN b[87]
    DIRECTION OUTPUT ;
    USE SIGNAL ;
    PORT
      LAYER M4 ;
        RECT  21.516 14.448 21.6 14.472 ;
    END
  END b[87]
  PIN b[88]
    DIRECTION OUTPUT ;
    USE SIGNAL ;
    PORT
      LAYER M4 ;
        RECT  21.516 14.592 21.6 14.616 ;
    END
  END b[88]
  PIN b[89]
    DIRECTION OUTPUT ;
    USE SIGNAL ;
    PORT
      LAYER M4 ;
        RECT  21.516 14.736 21.6 14.76 ;
    END
  END b[89]
  PIN b[8]
    DIRECTION OUTPUT ;
    USE SIGNAL ;
    PORT
      LAYER M4 ;
        RECT  21.516 2.304 21.6 2.328 ;
    END
  END b[8]
  PIN b[90]
    DIRECTION OUTPUT ;
    USE SIGNAL ;
    PORT
      LAYER M4 ;
        RECT  21.516 14.928 21.6 14.952 ;
    END
  END b[90]
  PIN b[91]
    DIRECTION OUTPUT ;
    USE SIGNAL ;
    PORT
      LAYER M4 ;
        RECT  21.516 15.072 21.6 15.096 ;
    END
  END b[91]
  PIN b[92]
    DIRECTION OUTPUT ;
    USE SIGNAL ;
    PORT
      LAYER M4 ;
        RECT  21.516 15.216 21.6 15.24 ;
    END
  END b[92]
  PIN b[93]
    DIRECTION OUTPUT ;
    USE SIGNAL ;
    PORT
      LAYER M4 ;
        RECT  21.516 15.36 21.6 15.384 ;
    END
  END b[93]
  PIN b[94]
    DIRECTION OUTPUT ;
    USE SIGNAL ;
    PORT
      LAYER M4 ;
        RECT  21.516 15.504 21.6 15.528 ;
    END
  END b[94]
  PIN b[95]
    DIRECTION OUTPUT ;
    USE SIGNAL ;
    PORT
      LAYER M4 ;
        RECT  21.516 15.696 21.6 15.72 ;
    END
  END b[95]
  PIN b[96]
    DIRECTION OUTPUT ;
    USE SIGNAL ;
    PORT
      LAYER M4 ;
        RECT  21.516 15.84 21.6 15.864 ;
    END
  END b[96]
  PIN b[97]
    DIRECTION OUTPUT ;
    USE SIGNAL ;
    PORT
      LAYER M4 ;
        RECT  21.516 15.984 21.6 16.008 ;
    END
  END b[97]
  PIN b[98]
    DIRECTION OUTPUT ;
    USE SIGNAL ;
    PORT
      LAYER M4 ;
        RECT  21.516 16.128 21.6 16.152 ;
    END
  END b[98]
  PIN b[99]
    DIRECTION OUTPUT ;
    USE SIGNAL ;
    PORT
      LAYER M4 ;
        RECT  21.516 16.272 21.6 16.296 ;
    END
  END b[99]
  PIN b[9]
    DIRECTION OUTPUT ;
    USE SIGNAL ;
    PORT
      LAYER M4 ;
        RECT  21.516 2.448 21.6 2.472 ;
    END
  END b[9]
  PIN ck
    DIRECTION INPUT ;
    USE SIGNAL ;
    PORT
      LAYER M3 ;
        RECT  10.8 0 10.818 0.038 ;
    END
  END ck
  PIN VDD
    DIRECTION INOUT ;
    USE POWER ;
    PORT
      LAYER M5 ;
        RECT  18.792 2.151 18.912 45.369 ;
        RECT  16.092 2.151 16.212 45.369 ;
        RECT  13.392 2.151 13.512 45.369 ;
        RECT  10.692 2.151 10.812 45.369 ;
        RECT  7.992 2.151 8.112 45.369 ;
        RECT  5.292 2.151 5.412 45.369 ;
        RECT  2.592 2.151 2.712 45.369 ;
    END
  END VDD
  PIN VSS
    DIRECTION INOUT ;
    USE GROUND ;
    PORT
      LAYER M5 ;
        RECT  18.6 2.137 18.72 45.383 ;
        RECT  15.9 2.137 16.02 45.383 ;
        RECT  13.2 2.137 13.32 45.383 ;
        RECT  10.5 2.137 10.62 45.383 ;
        RECT  7.8 2.137 7.92 45.383 ;
        RECT  5.1 2.137 5.22 45.383 ;
        RECT  2.4 2.137 2.52 45.383 ;
    END
  END VSS
  OBS
    LAYER RVTN ;
     RECT  2.16 2.16 19.44 2.295 ;
     RECT  2.16 2.565 19.44 2.835 ;
     RECT  2.16 3.105 19.44 3.375 ;
     RECT  2.16 3.645 19.44 3.915 ;
     RECT  2.16 4.185 19.44 4.455 ;
     RECT  2.16 4.725 19.44 4.995 ;
     RECT  2.16 5.265 19.44 5.535 ;
     RECT  2.16 5.805 19.44 6.075 ;
     RECT  2.16 6.345 19.44 6.615 ;
     RECT  2.16 6.885 19.44 7.155 ;
     RECT  2.16 7.425 19.44 7.695 ;
     RECT  2.16 7.965 19.44 8.235 ;
     RECT  2.16 8.505 19.44 8.775 ;
     RECT  2.16 9.045 19.44 9.315 ;
     RECT  2.16 9.585 19.44 9.855 ;
     RECT  2.16 10.125 19.44 10.395 ;
     RECT  2.16 10.665 19.44 10.935 ;
     RECT  2.16 11.205 19.44 11.475 ;
     RECT  2.16 11.745 19.44 12.015 ;
     RECT  2.16 12.285 19.44 12.555 ;
     RECT  2.16 12.825 19.44 13.095 ;
     RECT  2.16 13.365 19.44 13.635 ;
     RECT  2.16 13.905 19.44 14.175 ;
     RECT  2.16 14.445 19.44 14.715 ;
     RECT  2.16 14.985 19.44 15.255 ;
     RECT  2.16 15.525 19.44 15.795 ;
     RECT  2.16 16.065 19.44 16.335 ;
     RECT  2.16 16.605 19.44 16.875 ;
     RECT  2.16 17.145 19.44 17.415 ;
     RECT  2.16 17.685 19.44 17.955 ;
     RECT  2.16 18.225 19.44 18.495 ;
     RECT  2.16 18.765 19.44 19.035 ;
     RECT  2.16 19.305 19.44 19.575 ;
     RECT  2.16 19.845 19.44 20.115 ;
     RECT  2.16 20.385 19.44 20.655 ;
     RECT  2.16 20.925 19.44 21.195 ;
     RECT  2.16 21.465 19.44 21.735 ;
     RECT  2.16 22.005 19.44 22.275 ;
     RECT  2.16 22.545 19.44 22.815 ;
     RECT  2.16 23.085 19.44 23.355 ;
     RECT  2.16 23.625 19.44 23.895 ;
     RECT  2.16 24.165 19.44 24.435 ;
     RECT  2.16 24.705 19.44 24.975 ;
     RECT  2.16 25.245 19.44 25.515 ;
     RECT  2.16 25.785 19.44 26.055 ;
     RECT  2.16 26.325 19.44 26.595 ;
     RECT  2.16 26.865 19.44 27.135 ;
     RECT  2.16 27.405 19.44 27.675 ;
     RECT  2.16 27.945 19.44 28.215 ;
     RECT  2.16 28.485 19.44 28.755 ;
     RECT  2.16 29.025 19.44 29.295 ;
     RECT  2.16 29.565 19.44 29.835 ;
     RECT  2.16 30.105 19.44 30.375 ;
     RECT  2.16 30.645 19.44 30.915 ;
     RECT  2.16 31.185 19.44 31.455 ;
     RECT  2.16 31.725 19.44 31.995 ;
     RECT  2.16 32.265 19.44 32.535 ;
     RECT  2.16 32.805 19.44 33.075 ;
     RECT  2.16 33.345 19.44 33.615 ;
     RECT  2.16 33.885 19.44 34.155 ;
     RECT  2.16 34.425 19.44 34.695 ;
     RECT  2.16 34.965 19.44 35.235 ;
     RECT  2.16 35.505 19.44 35.775 ;
     RECT  2.16 36.045 19.44 36.315 ;
     RECT  2.16 36.585 19.44 36.855 ;
     RECT  2.16 37.125 19.44 37.395 ;
     RECT  2.16 37.665 19.44 37.935 ;
     RECT  2.16 38.205 19.44 38.475 ;
     RECT  2.16 38.745 19.44 39.015 ;
     RECT  2.16 39.285 19.44 39.555 ;
     RECT  2.16 39.825 19.44 40.095 ;
     RECT  2.16 40.365 19.44 40.635 ;
     RECT  2.16 40.905 19.44 41.175 ;
     RECT  2.16 41.445 19.44 41.715 ;
     RECT  2.16 41.985 19.44 42.255 ;
     RECT  2.16 42.525 19.44 42.795 ;
     RECT  2.16 43.065 19.44 43.335 ;
     RECT  2.16 43.605 19.44 43.875 ;
     RECT  2.16 44.145 19.44 44.415 ;
     RECT  2.16 44.685 19.44 44.955 ;
     RECT  2.16 45.225 19.44 45.36 ;
    LAYER RVTP ;
     RECT  2.16 2.295 19.44 2.565 ;
     RECT  2.16 2.835 19.44 3.105 ;
     RECT  2.16 3.375 19.44 3.645 ;
     RECT  2.16 3.915 19.44 4.185 ;
     RECT  2.16 4.455 19.44 4.725 ;
     RECT  2.16 4.995 19.44 5.265 ;
     RECT  2.16 5.535 19.44 5.805 ;
     RECT  2.16 6.075 19.44 6.345 ;
     RECT  2.16 6.615 19.44 6.885 ;
     RECT  2.16 7.155 19.44 7.425 ;
     RECT  2.16 7.695 19.44 7.965 ;
     RECT  2.16 8.235 19.44 8.505 ;
     RECT  2.16 8.775 19.44 9.045 ;
     RECT  2.16 9.315 19.44 9.585 ;
     RECT  2.16 9.855 19.44 10.125 ;
     RECT  2.16 10.395 19.44 10.665 ;
     RECT  2.16 10.935 19.44 11.205 ;
     RECT  2.16 11.475 19.44 11.745 ;
     RECT  2.16 12.015 19.44 12.285 ;
     RECT  2.16 12.555 19.44 12.825 ;
     RECT  2.16 13.095 19.44 13.365 ;
     RECT  2.16 13.635 19.44 13.905 ;
     RECT  2.16 14.175 19.44 14.445 ;
     RECT  2.16 14.715 19.44 14.985 ;
     RECT  2.16 15.255 19.44 15.525 ;
     RECT  2.16 15.795 19.44 16.065 ;
     RECT  2.16 16.335 19.44 16.605 ;
     RECT  2.16 16.875 19.44 17.145 ;
     RECT  2.16 17.415 19.44 17.685 ;
     RECT  2.16 17.955 19.44 18.225 ;
     RECT  2.16 18.495 19.44 18.765 ;
     RECT  2.16 19.035 19.44 19.305 ;
     RECT  2.16 19.575 19.44 19.845 ;
     RECT  2.16 20.115 19.44 20.385 ;
     RECT  2.16 20.655 19.44 20.925 ;
     RECT  2.16 21.195 19.44 21.465 ;
     RECT  2.16 21.735 19.44 22.005 ;
     RECT  2.16 22.275 19.44 22.545 ;
     RECT  2.16 22.815 19.44 23.085 ;
     RECT  2.16 23.355 19.44 23.625 ;
     RECT  2.16 23.895 19.44 24.165 ;
     RECT  2.16 24.435 19.44 24.705 ;
     RECT  2.16 24.975 19.44 25.245 ;
     RECT  2.16 25.515 19.44 25.785 ;
     RECT  2.16 26.055 19.44 26.325 ;
     RECT  2.16 26.595 19.44 26.865 ;
     RECT  2.16 27.135 19.44 27.405 ;
     RECT  2.16 27.675 19.44 27.945 ;
     RECT  2.16 28.215 19.44 28.485 ;
     RECT  2.16 28.755 19.44 29.025 ;
     RECT  2.16 29.295 19.44 29.565 ;
     RECT  2.16 29.835 19.44 30.105 ;
     RECT  2.16 30.375 19.44 30.645 ;
     RECT  2.16 30.915 19.44 31.185 ;
     RECT  2.16 31.455 19.44 31.725 ;
     RECT  2.16 31.995 19.44 32.265 ;
     RECT  2.16 32.535 19.44 32.805 ;
     RECT  2.16 33.075 19.44 33.345 ;
     RECT  2.16 33.615 19.44 33.885 ;
     RECT  2.16 34.155 19.44 34.425 ;
     RECT  2.16 34.695 19.44 34.965 ;
     RECT  2.16 35.235 19.44 35.505 ;
     RECT  2.16 35.775 19.44 36.045 ;
     RECT  2.16 36.315 19.44 36.585 ;
     RECT  2.16 36.855 19.44 37.125 ;
     RECT  2.16 37.395 19.44 37.665 ;
     RECT  2.16 37.935 19.44 38.205 ;
     RECT  2.16 38.475 19.44 38.745 ;
     RECT  2.16 39.015 19.44 39.285 ;
     RECT  2.16 39.555 19.44 39.825 ;
     RECT  2.16 40.095 19.44 40.365 ;
     RECT  2.16 40.635 19.44 40.905 ;
     RECT  2.16 41.175 19.44 41.445 ;
     RECT  2.16 41.715 19.44 41.985 ;
     RECT  2.16 42.255 19.44 42.525 ;
     RECT  2.16 42.795 19.44 43.065 ;
     RECT  2.16 43.335 19.44 43.605 ;
     RECT  2.16 43.875 19.44 44.145 ;
     RECT  2.16 44.415 19.44 44.685 ;
     RECT  2.16 44.955 19.44 45.225 ;
    LAYER M1 ;
     RECT  2.16 2.151 19.44 45.369 ;
    LAYER M2 ;
     RECT  1.651 44.658 1.687 44.676 ;
     RECT  1.723 2.232 1.759 2.25 ;
     RECT  1.759 2.232 2.16 2.286 ;
     RECT  0.103 11.952 2.16 11.97 ;
     RECT  0.103 27.342 2.16 27.36 ;
     RECT  0.535 42.03 2.16 42.048 ;
     RECT  1.687 44.658 2.16 44.946 ;
     RECT  2.16 2.151 2.947 45.369 ;
     RECT  2.947 2.151 3.091 45.414 ;
     RECT  3.091 2.151 3.775 45.486 ;
     RECT  3.775 2.106 4.315 45.486 ;
     RECT  4.315 2.034 5.999 45.486 ;
     RECT  5.999 2.106 6.835 45.486 ;
     RECT  6.835 2.034 8.411 45.486 ;
     RECT  8.411 2.034 8.491 45.414 ;
     RECT  8.491 1.962 10.823 45.414 ;
     RECT  10.823 2.034 14.827 45.369 ;
     RECT  14.827 1.998 14.899 45.369 ;
     RECT  14.899 1.998 15.367 45.414 ;
     RECT  15.367 1.881 17.447 45.414 ;
     RECT  17.447 1.962 18.851 45.414 ;
     RECT  18.851 1.962 19.427 45.369 ;
     RECT  19.427 2.07 19.44 45.369 ;
     RECT  19.44 8.856 19.931 31.824 ;
     RECT  19.931 8.856 19.967 27.774 ;
     RECT  19.931 29.466 19.967 31.716 ;
     RECT  19.44 7.668 20.471 7.884 ;
     RECT  19.44 2.07 20.507 6.804 ;
     RECT  19.967 8.856 20.507 17.478 ;
     RECT  19.967 18.27 20.507 27.774 ;
     RECT  19.931 28.566 20.507 28.674 ;
     RECT  19.967 29.466 20.507 31.518 ;
     RECT  19.44 32.706 20.507 45.144 ;
     RECT  20.507 3.69 20.543 6.444 ;
     RECT  20.507 8.856 20.543 11.574 ;
     RECT  20.507 12.636 20.543 14.814 ;
     RECT  20.507 29.844 20.543 31.518 ;
     RECT  20.507 36.666 20.543 44.442 ;
     RECT  20.543 43.686 20.579 44.442 ;
     RECT  20.543 29.844 20.615 31.482 ;
     RECT  20.543 40.986 20.615 42.282 ;
     RECT  20.543 3.69 21.443 6.138 ;
     RECT  20.543 8.856 21.443 11.304 ;
     RECT  20.507 35.55 21.443 35.838 ;
     RECT  20.507 2.07 21.479 2.322 ;
     RECT  21.443 3.924 21.479 5.328 ;
     RECT  21.443 6.084 21.479 6.138 ;
     RECT  20.471 7.668 21.479 7.794 ;
     RECT  21.443 8.856 21.479 11.268 ;
     RECT  20.543 13.914 21.479 14.814 ;
     RECT  20.507 15.606 21.479 17.478 ;
     RECT  20.507 24.516 21.479 25.884 ;
     RECT  20.507 26.64 21.479 27.774 ;
     RECT  20.507 32.886 21.479 34.524 ;
     RECT  21.443 35.55 21.479 35.604 ;
     RECT  20.543 36.666 21.479 39.924 ;
     RECT  21.479 2.07 21.515 2.088 ;
     RECT  21.479 3.924 21.515 4.284 ;
     RECT  21.479 5.238 21.515 5.256 ;
     RECT  21.479 6.084 21.515 6.102 ;
     RECT  21.479 7.668 21.515 7.686 ;
     RECT  21.479 8.856 21.515 8.874 ;
     RECT  21.479 9.864 21.515 10.962 ;
     RECT  20.543 12.636 21.515 12.654 ;
     RECT  21.479 13.914 21.515 13.932 ;
     RECT  21.479 14.796 21.515 14.814 ;
     RECT  21.479 16.074 21.515 17.478 ;
     RECT  20.507 18.27 21.515 18.864 ;
     RECT  20.507 19.62 21.515 22.374 ;
     RECT  20.507 23.4 21.515 23.418 ;
     RECT  21.479 24.516 21.515 24.534 ;
     RECT  21.479 25.29 21.515 25.884 ;
     RECT  21.479 26.64 21.515 27.702 ;
     RECT  20.507 28.566 21.515 28.584 ;
     RECT  20.615 29.844 21.515 31.248 ;
     RECT  21.479 32.886 21.515 32.904 ;
     RECT  21.479 34.164 21.515 34.524 ;
     RECT  21.479 35.586 21.515 35.604 ;
     RECT  21.479 36.666 21.515 38.736 ;
     RECT  21.479 39.6 21.515 39.618 ;
     RECT  20.615 40.986 21.515 41.544 ;
     RECT  20.579 44.424 21.515 44.442 ;
    LAYER M3 ;
     RECT  10.8 0.012 10.818 0.043 ;
     RECT  10.26 0.043 10.818 0.173 ;
     RECT  1.728 1.051 1.746 1.195 ;
     RECT  3.276 1.387 3.294 1.531 ;
     RECT  2.736 1.531 3.294 1.675 ;
     RECT  20.484 1.051 20.502 1.675 ;
     RECT  2.736 1.675 3.474 1.819 ;
     RECT  21.492 1.387 21.51 1.819 ;
     RECT  16.92 1.531 16.938 1.876 ;
     RECT  19.908 1.675 20.502 1.957 ;
     RECT  21.456 1.819 21.51 1.963 ;
     RECT  15.372 1.876 15.39 1.993 ;
     RECT  16.92 1.876 17.442 1.993 ;
     RECT  18.576 1.195 18.594 1.993 ;
     RECT  16.344 1.993 17.442 2.029 ;
     RECT  18.504 1.993 18.594 2.029 ;
     RECT  10.8 1.957 10.818 2.057 ;
     RECT  14.832 1.993 15.39 2.065 ;
     RECT  2.556 1.819 3.474 2.101 ;
     RECT  4.32 2.029 4.338 2.101 ;
     RECT  5.976 2.029 5.994 2.101 ;
     RECT  6.84 2.029 6.858 2.101 ;
     RECT  8.496 1.957 8.514 2.101 ;
     RECT  9.396 2.029 9.414 2.101 ;
     RECT  16.344 2.029 18.594 2.101 ;
     RECT  19.404 1.957 20.502 2.101 ;
     RECT  21.42 1.963 21.51 2.129 ;
     RECT  1.728 1.195 1.782 2.143 ;
     RECT  2.556 2.101 4.914 2.143 ;
     RECT  8.496 2.101 8.586 2.143 ;
     RECT  14.832 2.065 15.57 2.143 ;
     RECT  16.344 2.101 20.502 2.143 ;
     RECT  14.832 2.143 20.502 2.189 ;
     RECT  1.728 2.143 5.205 2.227 ;
     RECT  5.976 2.101 6.93 2.227 ;
     RECT  1.728 2.227 6.93 2.255 ;
     RECT  7.815 2.143 8.586 2.255 ;
     RECT  14.832 2.189 19.134 2.255 ;
     RECT  1.764 2.255 6.93 2.291 ;
     RECT  14.832 2.255 14.922 2.291 ;
     RECT  21.456 2.129 21.51 2.327 ;
     RECT  19.908 2.189 20.502 2.399 ;
     RECT  13.215 2.143 13.305 2.413 ;
     RECT  2.268 2.291 6.93 2.461 ;
     RECT  7.815 2.255 8.37 2.461 ;
     RECT  9.396 2.101 9.522 2.461 ;
     RECT  10.515 2.143 10.797 2.461 ;
     RECT  15.696 2.255 19.134 2.489 ;
     RECT  15.696 2.489 18.954 2.525 ;
     RECT  9.396 2.461 10.797 2.561 ;
     RECT  19.944 2.399 20.502 2.621 ;
     RECT  9.396 2.561 9.666 2.641 ;
     RECT  13.215 2.413 13.497 2.731 ;
     RECT  2.268 2.461 8.37 2.759 ;
     RECT  9.324 2.641 9.666 2.759 ;
     RECT  13.104 2.731 13.497 2.768 ;
     RECT  0.108 2.731 0.126 2.861 ;
     RECT  14.832 2.291 14.85 2.861 ;
     RECT  9.324 2.759 9.522 3.029 ;
     RECT  14.868 3.073 14.886 3.173 ;
     RECT  21.492 2.327 21.51 3.211 ;
     RECT  15.915 2.525 18.954 3.307 ;
     RECT  15.408 3.307 18.954 3.355 ;
     RECT  10.515 2.561 10.797 3.415 ;
     RECT  2.268 2.759 8.226 3.443 ;
     RECT  21.456 3.211 21.51 3.499 ;
     RECT  2.304 3.443 8.226 3.541 ;
     RECT  9.144 3.109 9.306 3.541 ;
     RECT  2.304 3.541 9.306 3.569 ;
     RECT  2.304 3.569 9.198 3.677 ;
     RECT  15.408 3.355 19.386 3.835 ;
     RECT  20.484 2.621 20.502 3.835 ;
     RECT  8.964 3.677 9.198 3.839 ;
     RECT  10.515 3.415 10.926 3.839 ;
     RECT  15.408 3.835 20.502 3.983 ;
     RECT  13.215 2.768 13.497 4.351 ;
     RECT  15.408 3.983 20.466 4.363 ;
     RECT  8.964 3.839 8.982 4.379 ;
     RECT  14.832 4.363 20.466 4.379 ;
     RECT  13.104 4.351 13.497 4.397 ;
     RECT  16.992 4.379 20.466 4.415 ;
     RECT  14.832 4.379 14.85 4.493 ;
     RECT  2.304 3.677 8.097 4.651 ;
     RECT  17.064 4.415 20.466 4.747 ;
     RECT  17.064 4.747 20.502 4.829 ;
     RECT  2.304 4.651 8.19 4.919 ;
     RECT  2.304 4.919 6.93 5.027 ;
     RECT  17.064 4.829 19.314 5.027 ;
     RECT  9.216 4.801 9.342 5.071 ;
     RECT  2.304 5.027 6.858 5.099 ;
     RECT  9.216 5.071 9.486 5.225 ;
     RECT  2.304 5.099 6.75 5.297 ;
     RECT  17.064 5.027 19.026 5.305 ;
     RECT  2.304 5.297 6.642 5.333 ;
     RECT  9.468 5.225 9.486 5.369 ;
     RECT  2.304 5.333 6.606 5.371 ;
     RECT  15.915 4.379 16.197 5.431 ;
     RECT  16.92 5.305 19.026 5.431 ;
     RECT  7.74 4.919 8.19 5.503 ;
     RECT  7.74 5.503 8.73 5.639 ;
     RECT  20.448 4.829 20.502 5.659 ;
     RECT  9.54 5.611 9.558 5.701 ;
     RECT  9.54 5.701 9.738 5.729 ;
     RECT  2.268 5.371 6.606 5.765 ;
     RECT  9.72 5.729 9.738 5.837 ;
     RECT  19.908 5.659 20.502 5.837 ;
     RECT  20.484 5.837 20.502 5.845 ;
     RECT  10.515 3.839 10.797 5.881 ;
     RECT  21.42 3.499 21.51 5.909 ;
     RECT  7.74 5.639 8.514 5.999 ;
     RECT  10.515 5.881 10.926 5.999 ;
     RECT  15.915 5.431 19.026 6.043 ;
     RECT  21.456 5.909 21.51 6.107 ;
     RECT  21.456 6.107 21.474 6.143 ;
     RECT  7.74 5.999 8.19 6.269 ;
     RECT  2.304 5.765 6.606 6.413 ;
     RECT  10.515 5.999 10.797 6.421 ;
     RECT  20.484 5.845 20.538 6.461 ;
     RECT  2.304 6.413 6.354 6.539 ;
     RECT  7.74 6.269 8.154 6.547 ;
     RECT  15.915 6.043 19.422 6.583 ;
     RECT  20.484 6.461 20.502 6.583 ;
     RECT  15.915 6.583 20.502 6.653 ;
     RECT  9.792 6.421 10.797 6.719 ;
     RECT  20.448 6.653 20.502 6.809 ;
     RECT  14.832 5.503 14.85 6.961 ;
     RECT  2.304 6.539 6.21 7.051 ;
     RECT  14.832 6.961 14.922 7.079 ;
     RECT  2.268 7.051 6.21 7.223 ;
     RECT  14.832 7.079 14.85 7.349 ;
     RECT  2.304 7.223 6.21 7.393 ;
     RECT  7.092 6.547 8.154 7.393 ;
     RECT  21.492 7.387 21.51 7.531 ;
     RECT  2.304 7.393 8.226 7.619 ;
     RECT  9.288 7.321 9.306 7.619 ;
     RECT  10.515 6.719 10.797 7.663 ;
     RECT  21.456 7.531 21.51 7.675 ;
     RECT  2.304 7.619 6.066 7.691 ;
     RECT  21.42 7.675 21.51 7.727 ;
     RECT  10.515 7.663 10.818 7.763 ;
     RECT  6.84 7.619 8.226 7.771 ;
     RECT  21.456 7.727 21.51 7.799 ;
     RECT  20.448 6.809 20.466 7.889 ;
     RECT  6.84 7.771 8.262 7.933 ;
     RECT  2.304 7.691 5.922 7.949 ;
     RECT  15.915 6.653 19.386 8.159 ;
     RECT  2.304 7.949 5.742 8.195 ;
     RECT  9.576 7.771 9.594 8.339 ;
     RECT  6.84 7.933 8.73 8.545 ;
     RECT  21.492 7.799 21.51 8.587 ;
     RECT  6.804 8.545 8.73 8.609 ;
     RECT  6.804 8.609 8.097 8.699 ;
     RECT  4.284 8.195 5.742 8.743 ;
     RECT  4.284 8.743 5.958 8.779 ;
     RECT  20.484 8.155 20.502 8.923 ;
     RECT  2.304 8.195 3.186 8.941 ;
     RECT  4.284 8.779 6.246 8.941 ;
     RECT  15.915 8.159 16.197 8.941 ;
     RECT  16.92 8.159 19.386 8.941 ;
     RECT  2.304 8.941 3.258 8.977 ;
     RECT  3.996 8.941 6.246 8.977 ;
     RECT  15.915 8.941 19.386 9.067 ;
     RECT  20.448 8.923 20.502 9.067 ;
     RECT  15.915 9.067 20.502 9.149 ;
     RECT  2.304 8.977 6.246 9.211 ;
     RECT  2.268 9.211 6.246 9.239 ;
     RECT  20.448 9.149 20.502 9.349 ;
     RECT  20.448 9.349 20.538 9.389 ;
     RECT  9.036 9.247 9.054 9.391 ;
     RECT  14.904 9.247 14.922 9.391 ;
     RECT  9.036 9.391 9.126 9.419 ;
     RECT  14.832 9.391 14.922 9.419 ;
     RECT  21.456 8.587 21.51 9.419 ;
     RECT  6.984 8.699 8.097 9.481 ;
     RECT  2.268 9.239 5.85 9.545 ;
     RECT  9.108 9.419 9.126 9.653 ;
     RECT  6.768 9.481 8.097 9.895 ;
     RECT  10.515 7.763 10.797 9.931 ;
     RECT  20.448 9.389 20.502 10.121 ;
     RECT  20.484 10.121 20.502 10.229 ;
     RECT  2.304 9.545 5.85 10.267 ;
     RECT  2.268 10.267 5.85 10.427 ;
     RECT  15.915 9.149 19.386 10.459 ;
     RECT  2.304 10.427 5.85 10.471 ;
     RECT  6.768 9.895 8.37 10.471 ;
     RECT  2.304 10.471 8.55 10.561 ;
     RECT  9.828 9.931 10.797 10.561 ;
     RECT  2.304 10.561 10.797 10.697 ;
     RECT  21.492 9.419 21.51 10.747 ;
     RECT  0.144 10.651 0.162 10.781 ;
     RECT  13.215 4.397 13.497 10.831 ;
     RECT  9.828 10.697 10.797 10.843 ;
     RECT  13.104 10.831 13.497 10.877 ;
     RECT  21.456 10.747 21.51 10.967 ;
     RECT  9.828 10.843 10.818 10.973 ;
     RECT  14.832 9.419 14.886 10.973 ;
     RECT  14.868 10.973 14.886 10.975 ;
     RECT  21.456 10.967 21.474 11.035 ;
     RECT  9.828 10.973 10.797 11.039 ;
     RECT  14.868 10.975 14.994 11.129 ;
     RECT  14.976 11.129 14.994 11.237 ;
     RECT  2.304 10.697 8.586 11.273 ;
     RECT  21.42 11.035 21.474 11.273 ;
     RECT  21.42 11.273 21.438 11.309 ;
     RECT  2.304 11.273 2.898 11.371 ;
     RECT  20.52 11.209 20.538 11.371 ;
     RECT  2.268 11.371 2.898 11.543 ;
     RECT  3.852 11.273 8.586 11.551 ;
     RECT  15.915 10.459 19.422 11.659 ;
     RECT  20.484 11.371 20.538 11.659 ;
     RECT  15.915 11.659 20.538 11.821 ;
     RECT  15.732 11.821 20.538 11.837 ;
     RECT  15.732 11.837 20.502 11.939 ;
     RECT  2.304 11.543 2.898 12.019 ;
     RECT  3.852 11.551 8.658 12.019 ;
     RECT  0.108 11.947 0.126 12.029 ;
     RECT  2.304 12.019 9.126 12.181 ;
     RECT  10.515 11.039 10.797 12.181 ;
     RECT  2.304 12.181 10.797 12.209 ;
     RECT  7.74 12.209 10.797 12.253 ;
     RECT  7.74 12.253 10.926 12.353 ;
     RECT  15.915 11.939 20.502 12.461 ;
     RECT  7.74 12.353 8.946 12.479 ;
     RECT  9.792 12.353 10.926 12.479 ;
     RECT  2.304 12.209 7.002 12.515 ;
     RECT  2.304 12.515 5.922 12.557 ;
     RECT  21.492 12.571 21.51 12.659 ;
     RECT  6.732 12.515 7.002 12.893 ;
     RECT  0.324 12.907 0.342 13.085 ;
     RECT  2.304 12.557 5.85 13.091 ;
     RECT  9.792 12.479 10.797 13.171 ;
     RECT  9.108 13.171 10.797 13.199 ;
     RECT  6.804 12.893 7.002 13.289 ;
     RECT  15.915 12.461 19.386 13.289 ;
     RECT  20.484 12.461 20.502 13.369 ;
     RECT  20.484 13.369 20.538 13.421 ;
     RECT  17.1 13.289 19.386 13.469 ;
     RECT  20.484 13.421 20.502 13.531 ;
     RECT  7.74 12.479 8.226 13.559 ;
     RECT  9.108 13.199 9.702 13.559 ;
     RECT  20.448 13.531 20.502 13.559 ;
     RECT  6.912 13.289 7.002 13.603 ;
     RECT  7.74 13.559 8.097 13.603 ;
     RECT  20.448 13.559 20.466 13.603 ;
     RECT  14.868 13.333 14.886 13.666 ;
     RECT  19.944 13.603 20.466 13.709 ;
     RECT  9.468 13.559 9.702 13.829 ;
     RECT  17.1 13.469 19.134 13.829 ;
     RECT  21.492 13.819 21.51 13.963 ;
     RECT  9.612 13.829 9.702 13.973 ;
     RECT  2.304 13.091 5.814 13.981 ;
     RECT  10.515 13.199 10.797 13.981 ;
     RECT  15.915 13.289 16.197 14.143 ;
     RECT  17.1 13.829 19.098 14.143 ;
     RECT  10.515 13.981 10.818 14.171 ;
     RECT  9.684 13.973 9.702 14.369 ;
     RECT  20.448 13.709 20.466 14.369 ;
     RECT  6.912 13.603 8.097 14.377 ;
     RECT  10.515 14.171 10.797 14.377 ;
     RECT  2.304 13.981 6.03 14.405 ;
     RECT  14.868 13.666 14.922 14.413 ;
     RECT  9.972 14.377 10.797 14.477 ;
     RECT  21.456 13.963 21.51 14.477 ;
     RECT  14.868 14.413 14.958 14.549 ;
     RECT  2.304 14.405 2.697 14.587 ;
     RECT  2.268 14.587 2.697 14.675 ;
     RECT  14.868 14.549 14.922 14.719 ;
     RECT  15.915 14.143 19.098 14.755 ;
     RECT  3.636 14.405 6.03 15.025 ;
     RECT  6.84 14.377 8.097 15.025 ;
     RECT  3.636 15.025 8.097 15.061 ;
     RECT  15.915 14.755 19.314 15.179 ;
     RECT  15.915 15.179 19.134 15.215 ;
     RECT  20.484 15.067 20.502 15.323 ;
     RECT  2.304 14.675 2.697 15.331 ;
     RECT  3.636 15.061 8.55 15.331 ;
     RECT  21.492 14.477 21.51 15.355 ;
     RECT  14.832 14.719 14.922 15.359 ;
     RECT  2.304 15.331 8.586 15.389 ;
     RECT  7.704 15.389 8.586 15.449 ;
     RECT  17.28 15.215 19.026 15.449 ;
     RECT  9.36 15.457 9.378 15.593 ;
     RECT  10.515 14.477 10.797 15.691 ;
     RECT  2.304 15.389 6.966 15.719 ;
     RECT  4.86 15.719 6.966 15.791 ;
     RECT  9.828 15.691 10.797 15.791 ;
     RECT  21.456 15.355 21.51 15.835 ;
     RECT  7.704 15.449 8.19 15.869 ;
     RECT  2.304 15.719 3.942 15.899 ;
     RECT  15.915 15.215 16.197 15.961 ;
     RECT  17.28 15.449 18.954 15.961 ;
     RECT  21.42 15.835 21.51 15.979 ;
     RECT  2.304 15.899 2.754 16.025 ;
     RECT  15.915 15.961 18.954 16.267 ;
     RECT  15.915 16.267 19.386 16.367 ;
     RECT  14.832 15.359 14.85 16.501 ;
     RECT  15.915 16.367 19.098 16.501 ;
     RECT  7.704 15.869 8.154 16.529 ;
     RECT  3.564 15.899 3.942 16.645 ;
     RECT  5.004 15.791 6.966 16.645 ;
     RECT  3.564 16.645 6.966 16.681 ;
     RECT  7.704 16.529 8.097 16.681 ;
     RECT  21.384 15.979 21.51 16.709 ;
     RECT  2.304 16.025 2.697 16.747 ;
     RECT  2.268 16.747 2.697 16.879 ;
     RECT  3.564 16.681 8.097 16.879 ;
     RECT  2.268 16.879 8.097 16.907 ;
     RECT  14.832 16.501 19.098 16.979 ;
     RECT  9.252 16.915 9.27 17.069 ;
     RECT  15.915 16.979 19.098 17.227 ;
     RECT  21.42 16.709 21.51 17.249 ;
     RECT  15.915 17.227 19.386 17.411 ;
     RECT  10.515 15.791 10.797 17.491 ;
     RECT  16.992 17.411 19.386 17.515 ;
     RECT  20.484 16.123 20.502 17.515 ;
     RECT  10.515 17.491 10.854 17.609 ;
     RECT  14.832 16.979 14.85 17.609 ;
     RECT  0.144 17.515 0.162 17.645 ;
     RECT  16.992 17.515 20.502 17.681 ;
     RECT  2.304 16.907 8.097 17.879 ;
     RECT  16.992 17.681 19.206 17.879 ;
     RECT  5.115 17.879 8.097 18.031 ;
     RECT  2.304 17.879 4.338 18.059 ;
     RECT  5.115 18.031 8.298 18.149 ;
     RECT  9.036 18.301 9.054 18.419 ;
     RECT  15.915 17.411 16.197 18.427 ;
     RECT  16.992 17.879 19.134 18.427 ;
     RECT  19.944 17.681 20.502 18.427 ;
     RECT  5.115 18.149 8.226 18.491 ;
     RECT  14.868 18.463 14.886 18.563 ;
     RECT  9.108 18.427 9.126 18.599 ;
     RECT  15.915 18.427 19.134 18.599 ;
     RECT  19.908 18.427 20.502 18.761 ;
     RECT  2.304 18.059 3.15 18.841 ;
     RECT  3.888 18.059 4.338 18.841 ;
     RECT  5.115 18.491 8.097 18.841 ;
     RECT  17.532 18.599 19.134 18.907 ;
     RECT  2.304 18.841 8.097 18.995 ;
     RECT  3.888 18.995 8.097 19.103 ;
     RECT  20.448 18.761 20.502 19.229 ;
     RECT  15.915 18.599 16.326 19.381 ;
     RECT  17.532 18.907 19.386 19.381 ;
     RECT  3.96 19.103 8.097 19.499 ;
     RECT  9.648 19.615 9.666 19.769 ;
     RECT  0.144 19.675 0.162 19.805 ;
     RECT  2.304 18.995 3.15 19.885 ;
     RECT  3.96 19.499 5.562 19.885 ;
     RECT  10.515 17.609 10.797 19.921 ;
     RECT  20.484 19.229 20.502 19.963 ;
     RECT  15.915 19.381 19.386 20.075 ;
     RECT  20.196 19.963 20.502 20.309 ;
     RECT  2.304 19.885 5.562 20.425 ;
     RECT  6.408 19.499 7.074 20.425 ;
     RECT  7.815 19.499 8.097 20.425 ;
     RECT  2.304 20.425 8.097 20.443 ;
     RECT  16.992 20.075 19.386 20.443 ;
     RECT  20.196 20.309 20.466 20.443 ;
     RECT  2.268 20.443 8.097 20.461 ;
     RECT  8.856 20.317 8.874 20.461 ;
     RECT  2.268 20.461 8.874 20.477 ;
     RECT  7.524 20.477 8.874 20.489 ;
     RECT  7.524 20.489 8.622 20.579 ;
     RECT  2.268 20.477 6.534 20.615 ;
     RECT  7.524 20.579 8.406 20.615 ;
     RECT  2.304 20.615 6.534 20.621 ;
     RECT  14.832 19.111 14.85 20.623 ;
     RECT  9.828 19.921 10.797 20.651 ;
     RECT  7.524 20.615 8.118 20.687 ;
     RECT  16.992 20.443 20.466 20.687 ;
     RECT  14.832 20.623 14.922 20.723 ;
     RECT  21.492 17.249 21.51 20.875 ;
     RECT  14.832 20.723 14.886 20.993 ;
     RECT  16.992 20.687 19.386 21.001 ;
     RECT  20.448 20.687 20.466 21.119 ;
     RECT  6.228 20.621 6.534 21.211 ;
     RECT  21.456 20.875 21.51 21.299 ;
     RECT  2.304 20.621 5.454 21.361 ;
     RECT  6.228 21.211 6.75 21.361 ;
     RECT  15.915 20.075 16.197 21.361 ;
     RECT  16.956 21.001 19.386 21.361 ;
     RECT  10.515 20.651 10.797 21.433 ;
     RECT  2.304 21.361 6.75 21.469 ;
     RECT  7.524 20.687 8.097 21.469 ;
     RECT  20.484 21.355 20.502 21.505 ;
     RECT  2.304 21.469 8.097 21.631 ;
     RECT  2.304 21.631 8.262 21.659 ;
     RECT  20.484 21.505 20.538 21.659 ;
     RECT  2.304 21.659 7.038 21.677 ;
     RECT  20.52 21.659 20.538 21.725 ;
     RECT  2.304 21.677 6.858 21.929 ;
     RECT  10.515 21.433 10.818 21.937 ;
     RECT  14.832 20.993 14.85 21.937 ;
     RECT  10.515 21.937 10.854 22.037 ;
     RECT  14.832 21.937 14.886 22.073 ;
     RECT  2.304 21.929 2.697 22.081 ;
     RECT  7.815 21.659 8.262 22.081 ;
     RECT  2.268 22.081 2.697 22.157 ;
     RECT  7.815 22.081 8.982 22.171 ;
     RECT  7.815 22.171 9.126 22.207 ;
     RECT  21.492 21.299 21.51 22.379 ;
     RECT  7.815 22.207 9.198 22.505 ;
     RECT  3.42 21.929 6.858 22.513 ;
     RECT  3.42 22.513 6.894 22.621 ;
     RECT  20.484 22.459 20.502 22.738 ;
     RECT  7.815 22.505 8.55 22.739 ;
     RECT  14.832 22.073 14.85 22.739 ;
     RECT  20.448 22.738 20.502 22.739 ;
     RECT  7.815 22.739 8.478 22.798 ;
     RECT  2.304 22.157 2.697 22.891 ;
     RECT  3.42 22.621 6.966 22.891 ;
     RECT  9.396 22.513 9.522 23.045 ;
     RECT  2.304 22.891 7.038 23.161 ;
     RECT  7.815 22.798 8.097 23.161 ;
     RECT  15.915 21.361 19.386 23.189 ;
     RECT  9.54 23.161 9.558 23.279 ;
     RECT  20.448 22.739 20.466 23.515 ;
     RECT  2.304 23.161 8.097 23.549 ;
     RECT  14.868 23.089 14.958 23.629 ;
     RECT  20.448 23.515 20.502 23.659 ;
     RECT  6.336 23.549 8.097 23.701 ;
     RECT  6.336 23.701 8.19 23.819 ;
     RECT  14.832 23.629 14.958 23.891 ;
     RECT  15.915 23.189 19.17 23.995 ;
     RECT  19.908 23.659 20.502 23.995 ;
     RECT  15.915 23.995 20.502 23.999 ;
     RECT  15.915 23.999 19.386 24.169 ;
     RECT  14.832 23.891 14.886 24.233 ;
     RECT  2.304 23.549 5.598 24.403 ;
     RECT  6.336 23.819 8.097 24.403 ;
     RECT  21.492 23.371 21.51 24.427 ;
     RECT  15.732 24.169 19.386 24.629 ;
     RECT  2.304 24.403 8.097 24.745 ;
     RECT  2.304 24.745 9.306 24.763 ;
     RECT  15.804 24.629 19.386 24.899 ;
     RECT  2.268 24.763 9.306 24.935 ;
     RECT  15.804 24.899 16.29 25.169 ;
     RECT  2.304 24.935 9.306 25.411 ;
     RECT  15.804 25.169 16.254 25.439 ;
     RECT  0.108 25.339 0.126 25.469 ;
     RECT  2.304 25.411 9.522 25.511 ;
     RECT  9.504 25.511 9.522 25.583 ;
     RECT  21.456 24.427 21.51 25.619 ;
     RECT  13.215 10.877 13.497 25.753 ;
     RECT  17.28 24.899 19.386 25.861 ;
     RECT  17.172 25.861 19.386 25.987 ;
     RECT  20.484 23.999 20.502 26.249 ;
     RECT  15.915 25.439 16.254 26.257 ;
     RECT  17.1 25.987 19.386 26.257 ;
     RECT  2.304 25.511 8.514 26.401 ;
     RECT  9.576 26.131 9.594 26.401 ;
     RECT  15.915 26.257 19.386 26.429 ;
     RECT  2.304 26.401 8.766 26.519 ;
     RECT  9.576 26.401 9.738 26.519 ;
     RECT  10.515 22.037 10.797 26.527 ;
     RECT  0.144 26.443 0.162 26.573 ;
     RECT  21.492 25.619 21.51 26.587 ;
     RECT  10.515 26.527 10.818 26.627 ;
     RECT  9.576 26.519 9.594 26.699 ;
     RECT  13.215 25.753 13.698 26.789 ;
     RECT  2.304 26.519 8.586 26.813 ;
     RECT  2.304 26.813 3.366 26.861 ;
     RECT  4.284 26.813 8.586 27.059 ;
     RECT  15.915 26.429 19.134 27.067 ;
     RECT  15.696 27.067 19.134 27.211 ;
     RECT  15.624 27.211 19.134 27.329 ;
     RECT  15.915 27.329 19.134 27.355 ;
     RECT  0.108 27.337 0.126 27.389 ;
     RECT  10.515 26.627 10.797 27.481 ;
     RECT  20.484 27.067 20.502 27.499 ;
     RECT  10.515 27.481 11.034 27.571 ;
     RECT  14.832 24.233 14.85 27.571 ;
     RECT  14.832 27.571 14.886 27.643 ;
     RECT  10.515 27.571 11.07 27.707 ;
     RECT  10.515 27.707 10.998 27.743 ;
     RECT  21.456 26.587 21.51 27.779 ;
     RECT  2.304 26.861 3.294 27.841 ;
     RECT  10.515 27.743 10.797 27.841 ;
     RECT  4.284 27.059 8.478 27.869 ;
     RECT  6.84 27.869 8.478 27.941 ;
     RECT  9.828 27.841 10.797 27.941 ;
     RECT  14.832 27.643 14.958 27.941 ;
     RECT  2.304 27.841 3.438 28.021 ;
     RECT  4.284 27.869 5.706 28.021 ;
     RECT  2.304 28.021 5.706 28.123 ;
     RECT  15.915 27.355 19.386 28.123 ;
     RECT  20.448 27.499 20.502 28.123 ;
     RECT  2.268 28.123 5.706 28.247 ;
     RECT  21.492 27.779 21.51 28.589 ;
     RECT  2.304 28.247 5.706 28.651 ;
     RECT  6.84 27.941 8.097 28.831 ;
     RECT  15.915 28.123 20.502 29.021 ;
     RECT  6.84 28.831 8.154 29.029 ;
     RECT  6.84 29.029 8.622 29.065 ;
     RECT  6.84 29.065 8.946 29.219 ;
     RECT  6.84 29.219 8.622 29.255 ;
     RECT  14.832 27.941 14.85 29.335 ;
     RECT  6.84 29.255 8.226 29.371 ;
     RECT  9.432 29.371 9.45 29.461 ;
     RECT  14.832 29.335 14.922 29.533 ;
     RECT  6.66 29.371 8.226 29.549 ;
     RECT  15.915 29.021 19.386 29.569 ;
     RECT  7.815 29.549 8.226 29.597 ;
     RECT  2.304 28.651 5.886 29.605 ;
     RECT  6.66 29.549 6.786 29.605 ;
     RECT  9.432 29.461 9.63 29.633 ;
     RECT  14.832 29.533 14.994 29.633 ;
     RECT  14.832 29.633 14.886 29.903 ;
     RECT  15.732 29.569 19.386 30.209 ;
     RECT  2.304 29.605 6.786 30.283 ;
     RECT  9.144 30.181 9.162 30.299 ;
     RECT  20.484 29.021 20.502 30.299 ;
     RECT  2.268 30.283 6.786 30.343 ;
     RECT  2.268 30.343 7.074 30.407 ;
     RECT  2.304 30.407 7.074 30.415 ;
     RECT  7.815 29.597 8.154 30.415 ;
     RECT  21.492 29.803 21.51 30.427 ;
     RECT  10.515 27.941 10.797 30.451 ;
     RECT  2.304 30.415 8.154 30.479 ;
     RECT  21.456 30.427 21.51 30.479 ;
     RECT  2.304 30.479 3.186 30.569 ;
     RECT  4.068 30.479 8.154 30.569 ;
     RECT  19.908 30.571 19.926 30.677 ;
     RECT  7.815 30.569 8.154 30.685 ;
     RECT  14.868 29.903 14.886 30.749 ;
     RECT  7.815 30.685 8.37 30.797 ;
     RECT  9.432 30.451 10.797 30.947 ;
     RECT  15.732 30.209 19.134 31.051 ;
     RECT  0.144 30.763 0.162 31.181 ;
     RECT  15.732 31.051 19.386 31.217 ;
     RECT  21.492 30.479 21.51 31.253 ;
     RECT  4.068 30.569 6.966 31.291 ;
     RECT  2.304 30.569 3.006 31.339 ;
     RECT  15.732 31.217 19.062 31.387 ;
     RECT  2.268 31.339 3.006 31.415 ;
     RECT  9.432 30.947 9.738 31.459 ;
     RECT  20.484 31.339 20.502 31.459 ;
     RECT  9.036 31.459 9.738 31.487 ;
     RECT  2.304 31.415 3.006 31.495 ;
     RECT  3.96 31.291 6.966 31.495 ;
     RECT  7.815 30.797 8.097 31.495 ;
     RECT  2.304 31.495 8.097 31.531 ;
     RECT  9.036 31.487 9.522 31.531 ;
     RECT  20.484 31.459 20.61 31.531 ;
     RECT  2.304 31.531 9.522 31.685 ;
     RECT  15.408 31.387 19.062 31.693 ;
     RECT  7.815 31.685 9.522 31.721 ;
     RECT  14.868 31.693 19.062 31.801 ;
     RECT  19.908 31.531 20.61 31.853 ;
     RECT  14.832 31.801 19.062 31.963 ;
     RECT  14.832 31.963 19.386 32.099 ;
     RECT  20.484 31.853 20.61 32.141 ;
     RECT  14.832 32.099 19.062 32.189 ;
     RECT  14.832 32.189 14.85 32.297 ;
     RECT  2.304 31.685 6.966 32.431 ;
     RECT  7.815 31.721 9.126 32.491 ;
     RECT  2.304 32.431 7.002 32.503 ;
     RECT  10.515 30.947 10.797 32.503 ;
     RECT  10.515 32.503 10.818 32.837 ;
     RECT  15.915 32.189 19.062 32.845 ;
     RECT  21.492 32.587 21.51 32.875 ;
     RECT  2.304 32.503 7.038 32.881 ;
     RECT  7.812 32.491 9.126 32.881 ;
     RECT  21.456 32.875 21.51 32.909 ;
     RECT  2.304 32.881 9.162 32.971 ;
     RECT  20.484 32.141 20.502 33.043 ;
     RECT  2.304 32.971 9.666 33.071 ;
     RECT  3.564 33.071 9.666 33.115 ;
     RECT  10.515 32.837 10.797 33.115 ;
     RECT  20.484 33.043 20.538 33.151 ;
     RECT  19.944 33.151 20.538 33.245 ;
     RECT  3.564 33.115 10.797 33.269 ;
     RECT  3.564 33.269 8.586 33.341 ;
     RECT  21.456 32.909 21.474 33.449 ;
     RECT  15.915 32.845 19.134 33.539 ;
     RECT  3.564 33.341 6.174 33.581 ;
     RECT  17.1 33.539 19.134 33.643 ;
     RECT  3.636 33.581 6.174 33.647 ;
     RECT  14.832 33.313 14.85 33.889 ;
     RECT  6.948 33.341 8.586 33.989 ;
     RECT  20.484 33.245 20.538 33.989 ;
     RECT  14.832 33.889 15.03 34.151 ;
     RECT  2.304 33.071 2.754 34.159 ;
     RECT  5.076 33.647 6.174 34.231 ;
     RECT  6.948 33.989 8.514 34.231 ;
     RECT  5.076 34.231 8.514 34.259 ;
     RECT  10.515 33.269 10.797 34.357 ;
     RECT  17.1 33.643 19.386 34.421 ;
     RECT  14.832 34.151 14.886 34.457 ;
     RECT  2.304 34.159 2.862 34.501 ;
     RECT  3.636 33.647 4.086 34.501 ;
     RECT  5.076 34.259 6.858 34.501 ;
     RECT  17.1 34.421 19.35 34.501 ;
     RECT  9.828 34.357 10.797 34.529 ;
     RECT  20.484 33.989 20.502 34.591 ;
     RECT  14.868 34.457 14.886 34.727 ;
     RECT  7.776 34.259 8.514 34.771 ;
     RECT  7.776 34.771 8.586 34.889 ;
     RECT  9.72 34.771 9.738 34.889 ;
     RECT  7.776 34.889 8.406 34.931 ;
     RECT  2.304 34.501 6.858 35.041 ;
     RECT  7.776 34.931 8.097 35.041 ;
     RECT  15.915 33.539 16.197 35.041 ;
     RECT  16.92 34.501 19.35 35.041 ;
     RECT  9.288 34.969 9.558 35.069 ;
     RECT  20.448 34.591 20.502 35.069 ;
     RECT  2.304 35.041 8.097 35.159 ;
     RECT  9.36 35.069 9.558 35.159 ;
     RECT  21.492 34.123 21.51 35.179 ;
     RECT  2.304 35.159 7.038 35.195 ;
     RECT  9.36 35.159 9.45 35.195 ;
     RECT  9.432 35.195 9.45 35.267 ;
     RECT  15.915 35.041 19.35 35.371 ;
     RECT  2.304 35.195 6.93 35.429 ;
     RECT  21.456 35.179 21.51 35.515 ;
     RECT  2.304 35.429 3.042 35.659 ;
     RECT  7.776 35.159 8.097 35.699 ;
     RECT  7.815 35.699 8.097 35.743 ;
     RECT  14.868 35.707 14.886 35.743 ;
     RECT  21.42 35.515 21.51 35.843 ;
     RECT  14.868 35.743 14.958 35.879 ;
     RECT  3.924 35.429 6.93 35.969 ;
     RECT  20.484 35.069 20.502 35.969 ;
     RECT  15.915 35.371 19.386 36.085 ;
     RECT  7.815 35.743 8.154 36.121 ;
     RECT  10.515 34.529 10.797 36.211 ;
     RECT  4.392 35.969 6.93 36.247 ;
     RECT  4.392 36.247 7.074 36.275 ;
     RECT  7.815 36.121 8.19 36.283 ;
     RECT  14.868 35.879 14.922 36.283 ;
     RECT  10.515 36.211 10.854 36.311 ;
     RECT  2.268 35.659 3.042 36.331 ;
     RECT  0.144 36.331 0.162 36.461 ;
     RECT  15.915 36.085 19.962 36.461 ;
     RECT  2.268 36.331 3.438 36.545 ;
     RECT  21.492 35.843 21.51 36.571 ;
     RECT  4.896 36.275 7.074 36.581 ;
     RECT  7.815 36.283 8.658 36.823 ;
     RECT  15.915 36.461 19.386 36.851 ;
     RECT  14.832 36.283 14.922 36.887 ;
     RECT  2.304 36.545 3.438 36.931 ;
     RECT  7.164 36.823 8.658 36.959 ;
     RECT  9.468 36.931 9.486 37.049 ;
     RECT  2.304 36.931 3.978 37.201 ;
     RECT  4.896 36.581 6.282 37.201 ;
     RECT  2.304 37.201 6.282 37.319 ;
     RECT  7.164 36.959 8.622 37.319 ;
     RECT  3.744 37.319 6.282 37.355 ;
     RECT  3.816 37.355 6.282 37.435 ;
     RECT  7.02 37.399 7.038 37.435 ;
     RECT  14.832 36.887 14.85 37.463 ;
     RECT  20.52 37.399 20.538 37.565 ;
     RECT  21.456 36.571 21.51 37.675 ;
     RECT  10.515 36.311 10.797 37.741 ;
     RECT  2.304 37.319 2.862 37.819 ;
     RECT  10.515 37.741 10.818 37.859 ;
     RECT  20.484 37.819 20.502 37.859 ;
     RECT  2.268 37.819 2.862 38.003 ;
     RECT  7.776 37.319 8.622 38.011 ;
     RECT  21.42 37.675 21.51 38.039 ;
     RECT  3.816 37.435 7.038 38.101 ;
     RECT  10.515 37.859 10.797 38.101 ;
     RECT  3.708 38.101 7.038 38.137 ;
     RECT  7.776 38.011 8.874 38.137 ;
     RECT  3.708 38.137 8.874 38.141 ;
     RECT  7.092 38.141 8.874 38.165 ;
     RECT  2.304 38.003 2.862 38.209 ;
     RECT  3.708 38.141 6.318 38.245 ;
     RECT  19.944 38.245 19.962 38.299 ;
     RECT  2.304 38.209 2.934 38.479 ;
     RECT  3.672 38.245 6.318 38.479 ;
     RECT  9.828 38.101 10.797 38.579 ;
     RECT  19.908 38.299 19.962 38.621 ;
     RECT  15.915 36.851 19.134 38.821 ;
     RECT  2.304 38.479 6.318 38.875 ;
     RECT  15.804 38.821 19.134 38.875 ;
     RECT  15.804 38.875 19.386 38.939 ;
     RECT  15.915 38.939 19.386 39.011 ;
     RECT  2.268 38.875 6.318 39.019 ;
     RECT  7.092 38.165 8.766 39.019 ;
     RECT  14.904 38.983 14.922 39.055 ;
     RECT  2.268 39.019 8.766 39.083 ;
     RECT  13.215 26.789 13.497 39.217 ;
     RECT  20.484 39.208 20.502 39.245 ;
     RECT  14.832 39.055 14.922 39.317 ;
     RECT  9.504 39.325 9.522 39.361 ;
     RECT  2.304 39.083 8.766 39.479 ;
     RECT  13.215 39.217 13.698 39.479 ;
     RECT  0.324 39.355 0.342 39.499 ;
     RECT  0.108 39.499 0.342 39.533 ;
     RECT  21.456 38.039 21.51 39.623 ;
     RECT  21.456 39.623 21.474 39.643 ;
     RECT  2.304 39.479 8.622 39.749 ;
     RECT  0.108 39.533 0.126 39.773 ;
     RECT  2.304 39.749 5.994 39.785 ;
     RECT  15.915 39.011 19.134 39.793 ;
     RECT  21.42 39.643 21.474 39.821 ;
     RECT  9.504 39.361 9.558 39.865 ;
     RECT  9.504 39.865 9.702 39.901 ;
     RECT  21.456 39.821 21.474 39.929 ;
     RECT  9.432 39.901 9.702 40.019 ;
     RECT  15.84 39.793 19.134 40.019 ;
     RECT  19.908 39.979 19.926 40.099 ;
     RECT  15.915 40.019 19.134 40.123 ;
     RECT  19.908 40.099 20.538 40.123 ;
     RECT  15.915 40.123 20.538 40.199 ;
     RECT  6.84 39.749 8.622 40.289 ;
     RECT  2.304 39.785 5.742 40.297 ;
     RECT  9.432 40.019 9.558 40.559 ;
     RECT  9.432 40.559 9.45 40.595 ;
     RECT  6.84 40.289 8.586 40.675 ;
     RECT  14.832 40.711 14.922 40.829 ;
     RECT  21.492 40.411 21.51 40.891 ;
     RECT  14.868 40.829 14.922 40.901 ;
     RECT  15.915 40.199 19.386 40.901 ;
     RECT  6.624 40.675 8.586 40.973 ;
     RECT  20.52 40.199 20.538 41.069 ;
     RECT  2.268 40.297 5.742 41.107 ;
     RECT  6.624 40.973 8.097 41.107 ;
     RECT  21.456 40.891 21.51 41.279 ;
     RECT  21.492 41.279 21.51 41.549 ;
     RECT  14.868 40.901 14.886 41.791 ;
     RECT  2.268 41.107 8.097 41.851 ;
     RECT  10.515 38.579 10.797 41.917 ;
     RECT  14.868 41.791 14.922 41.917 ;
     RECT  2.268 41.851 8.37 41.945 ;
     RECT  9.828 41.917 10.797 41.947 ;
     RECT  15.915 40.901 19.062 41.953 ;
     RECT  15.915 41.953 19.206 41.989 ;
     RECT  19.944 41.071 20.502 41.989 ;
     RECT  13.215 39.479 13.497 42.043 ;
     RECT  14.832 41.917 14.922 42.053 ;
     RECT  9.828 41.947 10.818 42.061 ;
     RECT  9.468 42.061 10.818 42.077 ;
     RECT  14.868 42.053 14.922 42.077 ;
     RECT  9.468 42.077 10.797 42.089 ;
     RECT  13.104 42.043 13.497 42.089 ;
     RECT  9.468 42.089 9.666 42.179 ;
     RECT  15.915 41.989 20.502 42.259 ;
     RECT  2.304 41.945 8.37 42.331 ;
     RECT  9.468 42.179 9.594 42.601 ;
     RECT  2.304 42.331 8.586 42.629 ;
     RECT  13.215 42.089 13.497 42.727 ;
     RECT  0.54 42.025 0.558 42.749 ;
     RECT  15.084 42.691 15.102 42.871 ;
     RECT  15.915 42.259 20.61 43.069 ;
     RECT  15.84 43.069 20.61 43.085 ;
     RECT  9.36 42.601 9.594 43.105 ;
     RECT  9.36 43.105 9.63 43.141 ;
     RECT  9.072 43.141 9.63 43.259 ;
     RECT  14.616 42.871 15.102 43.259 ;
     RECT  14.76 43.259 15.102 43.303 ;
     RECT  15.84 43.085 20.574 43.303 ;
     RECT  9.576 43.259 9.63 43.331 ;
     RECT  10.515 42.089 10.797 43.339 ;
     RECT  10.515 43.339 10.854 43.529 ;
     RECT  2.304 42.629 8.298 43.681 ;
     RECT  13.215 42.727 13.698 43.709 ;
     RECT  14.76 43.303 20.574 43.709 ;
     RECT  20.484 43.709 20.574 43.997 ;
     RECT  0.144 43.963 0.162 44.093 ;
     RECT  9.576 43.331 9.594 44.149 ;
     RECT  2.304 43.681 8.622 44.221 ;
     RECT  9.504 44.149 9.594 44.221 ;
     RECT  14.76 43.709 19.422 44.419 ;
     RECT  20.484 43.997 20.538 44.443 ;
     RECT  14.58 44.419 19.422 44.609 ;
     RECT  2.304 44.221 9.594 44.653 ;
     RECT  10.515 43.529 10.797 44.689 ;
     RECT  14.868 44.609 19.422 44.689 ;
     RECT  20.376 44.443 20.538 44.689 ;
     RECT  1.656 44.653 9.594 44.725 ;
     RECT  10.476 44.689 10.797 44.725 ;
     RECT  1.656 44.725 10.797 44.875 ;
     RECT  1.656 44.875 10.818 44.879 ;
     RECT  6.444 44.879 10.818 44.887 ;
     RECT  1.656 44.879 5.598 44.951 ;
     RECT  6.444 44.887 10.854 45.023 ;
     RECT  14.868 44.689 20.538 45.023 ;
     RECT  14.904 45.023 20.538 45.053 ;
     RECT  6.444 45.023 9.594 45.059 ;
     RECT  13.215 43.709 13.497 45.107 ;
     RECT  1.656 44.951 4.086 45.149 ;
     RECT  9.324 45.059 9.594 45.149 ;
     RECT  10.515 45.023 10.854 45.149 ;
     RECT  20.484 45.053 20.538 45.149 ;
     RECT  6.444 45.059 8.586 45.185 ;
     RECT  14.904 45.053 19.422 45.185 ;
     RECT  6.444 45.185 7.038 45.221 ;
     RECT  9.324 45.149 9.342 45.221 ;
     RECT  20.52 45.149 20.538 45.245 ;
     RECT  7.815 45.185 8.586 45.293 ;
     RECT  17.676 45.185 19.422 45.329 ;
     RECT  1.656 45.149 3.978 45.377 ;
     RECT  5.115 44.951 5.598 45.377 ;
     RECT  7.815 45.293 8.406 45.377 ;
     RECT  10.515 45.149 10.818 45.377 ;
     RECT  13.215 45.107 13.305 45.377 ;
     RECT  14.904 45.185 16.83 45.377 ;
     RECT  0.144 45.259 0.162 45.389 ;
     RECT  21.492 44.419 21.51 45.389 ;
     RECT  5.58 45.377 5.598 45.419 ;
     RECT  6.768 45.221 7.038 45.419 ;
     RECT  10.8 45.377 10.818 45.419 ;
     RECT  14.904 45.377 15.354 45.419 ;
     RECT  6.768 45.419 6.858 45.491 ;
     RECT  8.388 45.377 8.406 45.491 ;
     RECT  2.736 45.377 3.978 45.533 ;
     RECT  16.524 45.377 16.83 45.533 ;
     RECT  2.736 45.533 2.826 45.677 ;
     RECT  16.524 45.533 16.578 45.677 ;
     RECT  3.96 45.533 3.978 45.869 ;
     RECT  18.216 45.329 19.422 45.869 ;
     RECT  2.736 45.677 2.79 46.013 ;
     RECT  18.828 45.869 19.422 46.013 ;
     RECT  2.772 46.013 2.79 46.157 ;
     RECT  15.336 45.419 15.354 46.157 ;
     RECT  1.656 45.377 1.71 46.301 ;
     RECT  16.56 45.677 16.578 46.301 ;
     RECT  1.656 46.301 1.674 46.445 ;
     RECT  19.404 46.013 19.422 46.445 ;
    LAYER M4 ;
     RECT  0.06 1.056 1.685 46.44 ;
     RECT  1.685 1.056 1.721 46.296 ;
     RECT  1.721 1.056 1.757 46.152 ;
     RECT  1.757 1.2 1.793 46.152 ;
     RECT  1.793 1.392 2.704 46.152 ;
     RECT  2.704 23.04 2.729 23.688 ;
     RECT  2.704 11.664 2.765 14.184 ;
     RECT  2.704 15.504 2.765 18.456 ;
     RECT  2.729 23.04 2.765 23.064 ;
     RECT  2.704 33.552 2.765 33.672 ;
     RECT  2.704 38.64 2.801 46.152 ;
     RECT  2.704 1.392 2.837 3.048 ;
     RECT  2.765 16.896 2.837 17.64 ;
     RECT  2.837 2.832 2.873 3.048 ;
     RECT  2.704 21.216 2.873 21.24 ;
     RECT  2.704 30.144 2.873 30.168 ;
     RECT  2.873 3.024 2.909 3.048 ;
     RECT  2.704 31.152 2.909 31.704 ;
     RECT  2.704 5.904 3.017 7.416 ;
     RECT  2.704 28.272 3.017 29.064 ;
     RECT  2.909 31.152 3.017 31.176 ;
     RECT  2.704 19.776 3.089 19.944 ;
     RECT  2.837 17.616 3.125 17.64 ;
     RECT  2.704 9.36 3.269 10.68 ;
     RECT  2.837 1.392 3.305 1.704 ;
     RECT  2.704 35.904 3.305 36.36 ;
     RECT  2.704 25.44 3.341 25.464 ;
     RECT  2.704 26.544 3.377 27.192 ;
     RECT  3.269 9.36 3.413 10.152 ;
     RECT  2.801 42.72 3.413 45.864 ;
     RECT  3.305 1.68 3.485 1.704 ;
     RECT  2.801 38.64 3.629 41.256 ;
     RECT  3.629 39.264 3.635 41.256 ;
     RECT  2.765 33.552 3.697 33.576 ;
     RECT  3.413 42.72 3.773 44.76 ;
     RECT  2.704 4.368 3.877 4.776 ;
     RECT  3.017 5.904 3.877 6.84 ;
     RECT  2.765 13.056 3.913 14.184 ;
     RECT  3.089 19.92 3.973 19.944 ;
     RECT  3.913 13.056 3.98 14.28 ;
     RECT  3.877 4.368 3.985 6.84 ;
     RECT  3.413 45.84 3.989 45.864 ;
     RECT  3.973 19.92 4.019 20.568 ;
     RECT  3.697 32.736 4.021 33.576 ;
     RECT  2.704 34.8 4.021 34.824 ;
     RECT  3.98 12.96 4.025 14.28 ;
     RECT  3.805 29.088 4.025 29.64 ;
     RECT  4.021 32.736 4.057 34.824 ;
     RECT  4.021 11.376 4.129 11.4 ;
     RECT  4.025 14.256 4.165 14.28 ;
     RECT  3.913 15.456 4.165 15.48 ;
     RECT  3.413 9.36 4.201 9.384 ;
     RECT  3.377 26.784 4.261 27.192 ;
     RECT  3.773 42.72 4.273 44.472 ;
     RECT  4.273 42.576 4.309 44.472 ;
     RECT  3.635 39.744 4.453 41.256 ;
     RECT  4.309 42.432 4.453 44.472 ;
     RECT  3.985 21.552 4.489 21.576 ;
     RECT  4.201 23.376 4.489 23.4 ;
     RECT  4.093 7.92 4.525 7.944 ;
     RECT  4.201 9.072 4.525 9.384 ;
     RECT  3.949 31.296 4.525 31.32 ;
     RECT  3.985 3.936 4.597 6.84 ;
     RECT  4.525 7.92 4.597 9.384 ;
     RECT  3.949 37.056 4.633 37.08 ;
     RECT  3.805 38.16 4.633 38.232 ;
     RECT  4.453 39.744 4.633 44.472 ;
     RECT  4.025 12.96 4.669 13.08 ;
     RECT  4.261 24.48 4.669 24.504 ;
     RECT  3.805 25.584 4.669 25.608 ;
     RECT  4.261 26.784 4.693 27.624 ;
     RECT  4.453 2.784 4.705 2.808 ;
     RECT  3.949 18.192 4.849 18.216 ;
     RECT  4.057 32.736 4.849 34.92 ;
     RECT  3.305 35.904 4.849 35.928 ;
     RECT  4.489 21.552 4.885 23.4 ;
     RECT  4.669 24.48 4.885 25.608 ;
     RECT  4.705 2.256 5.108 2.808 ;
     RECT  4.597 3.936 5.108 9.384 ;
     RECT  4.129 11.376 5.108 11.448 ;
     RECT  4.669 12.864 5.108 13.08 ;
     RECT  4.165 14.256 5.108 15.48 ;
     RECT  5.065 16.608 5.108 16.632 ;
     RECT  4.849 17.616 5.108 18.216 ;
     RECT  4.741 19.44 5.108 19.464 ;
     RECT  4.019 20.544 5.108 20.568 ;
     RECT  4.885 21.552 5.108 25.608 ;
     RECT  4.693 26.784 5.108 27.96 ;
     RECT  4.025 29.088 5.108 29.112 ;
     RECT  4.525 30.192 5.108 31.32 ;
     RECT  4.849 32.736 5.108 35.928 ;
     RECT  4.633 37.056 5.108 44.472 ;
     RECT  5.108 2.148 5.212 45.372 ;
     RECT  5.212 2.256 5.404 45.102 ;
     RECT  5.404 4.656 5.465 4.872 ;
     RECT  5.404 23.136 5.501 25.032 ;
     RECT  5.404 18.72 5.555 20.616 ;
     RECT  5.501 23.376 5.573 25.032 ;
     RECT  5.404 7.728 5.651 9.768 ;
     RECT  5.404 31.872 5.681 34.92 ;
     RECT  5.651 7.728 5.717 9.096 ;
     RECT  5.681 31.872 5.747 34.488 ;
     RECT  5.747 31.872 5.753 33.816 ;
     RECT  5.555 19.2 5.789 20.616 ;
     RECT  5.404 2.256 5.825 2.808 ;
     RECT  5.404 36.384 5.825 39.096 ;
     RECT  5.404 12.528 5.843 16.632 ;
     RECT  5.404 17.664 5.843 17.688 ;
     RECT  5.404 29.664 5.861 29.688 ;
     RECT  5.753 33.216 5.932 33.816 ;
     RECT  5.717 7.92 5.933 9.096 ;
     RECT  5.404 10.848 5.933 11.448 ;
     RECT  5.404 30.816 5.977 30.84 ;
     RECT  5.933 11.424 6.005 11.448 ;
     RECT  5.404 26.784 6.035 27.624 ;
     RECT  5.404 28.656 6.035 28.68 ;
     RECT  5.933 8.496 6.041 9.096 ;
     RECT  5.573 23.376 6.113 24.504 ;
     RECT  5.465 4.848 6.293 4.872 ;
     RECT  6.035 27.6 6.365 27.624 ;
     RECT  5.404 40.656 6.371 44.664 ;
     RECT  5.843 12.528 6.541 13.08 ;
     RECT  5.789 19.776 6.581 20.616 ;
     RECT  5.843 14.16 6.653 16.632 ;
     RECT  6.469 4.656 6.685 4.68 ;
     RECT  6.581 20.448 6.721 20.616 ;
     RECT  5.404 21.648 6.721 21.672 ;
     RECT  5.825 2.736 6.829 2.808 ;
     RECT  6.371 40.656 6.829 42.168 ;
     RECT  6.541 11.952 6.853 13.08 ;
     RECT  6.653 14.16 6.853 15.768 ;
     RECT  5.825 36.384 6.853 38.568 ;
     RECT  6.829 39.84 6.853 42.168 ;
     RECT  6.113 23.376 6.901 23.976 ;
     RECT  6.829 2.592 6.94 2.808 ;
     RECT  5.404 6.096 7.081 6.696 ;
     RECT  7.189 17.664 7.381 17.688 ;
     RECT  6.613 25.056 7.388 25.08 ;
     RECT  5.753 31.872 7.436 31.896 ;
     RECT  6.937 29.52 7.477 29.544 ;
     RECT  7.436 31.536 7.477 31.896 ;
     RECT  7.117 10.176 7.549 10.2 ;
     RECT  6.853 11.952 7.649 15.768 ;
     RECT  7.381 17.088 7.649 17.688 ;
     RECT  6.94 2.592 7.808 2.856 ;
     RECT  6.685 4.368 7.808 4.68 ;
     RECT  7.081 6.096 7.808 6.888 ;
     RECT  6.041 8.496 7.808 8.52 ;
     RECT  7.549 10.176 7.808 10.968 ;
     RECT  7.649 11.952 7.808 17.688 ;
     RECT  6.86 19.152 7.808 19.176 ;
     RECT  6.721 20.448 7.808 21.672 ;
     RECT  6.901 22.752 7.808 23.976 ;
     RECT  7.388 25.056 7.808 25.848 ;
     RECT  7.477 29.52 7.808 30.168 ;
     RECT  7.477 31.536 7.808 32.52 ;
     RECT  5.932 33.792 7.808 33.816 ;
     RECT  6.853 36.384 7.808 42.168 ;
     RECT  6.371 43.536 7.808 44.664 ;
     RECT  7.808 2.148 7.912 45.372 ;
     RECT  7.912 2.418 8.104 45.144 ;
     RECT  8.104 13.056 8.129 13.08 ;
     RECT  8.104 25.2 8.129 25.224 ;
     RECT  8.104 4.128 8.165 6.888 ;
     RECT  8.104 30.144 8.165 30.792 ;
     RECT  8.165 4.128 8.201 6.168 ;
     RECT  8.104 15.84 8.201 15.864 ;
     RECT  8.104 43.536 8.291 45.144 ;
     RECT  8.104 10.176 8.381 10.968 ;
     RECT  8.165 30.768 8.381 30.792 ;
     RECT  8.104 32.976 8.387 33 ;
     RECT  8.104 34.368 8.387 34.92 ;
     RECT  8.104 37.536 8.387 37.56 ;
     RECT  8.104 39.744 8.417 39.768 ;
     RECT  8.387 34.896 8.428 34.92 ;
     RECT  8.104 22.752 8.489 22.776 ;
     RECT  8.104 40.944 8.597 41.976 ;
     RECT  8.597 41.904 9.565 41.976 ;
     RECT  8.291 43.536 9.565 44.664 ;
     RECT  9.565 41.904 10.141 44.664 ;
     RECT  6.085 0.048 10.249 0.072 ;
     RECT  10.249 0.048 10.289 0.168 ;
     RECT  8.104 2.496 10.508 2.856 ;
     RECT  8.201 4.128 10.508 4.488 ;
     RECT  8.201 6.144 10.508 6.168 ;
     RECT  8.381 10.944 10.508 10.968 ;
     RECT  8.104 14.16 10.508 14.184 ;
     RECT  10.141 41.904 10.508 44.904 ;
     RECT  10.508 2.148 10.612 45.372 ;
     RECT  10.612 2.418 10.804 45.102 ;
     RECT  10.289 0.144 10.829 0.168 ;
     RECT  10.804 10.848 10.829 10.968 ;
     RECT  10.804 41.904 10.829 44.904 ;
     RECT  10.804 2.496 13.208 2.76 ;
     RECT  10.804 4.128 13.208 4.392 ;
     RECT  10.804 6.144 13.208 6.168 ;
     RECT  10.829 10.848 13.208 10.872 ;
     RECT  10.804 14.16 13.208 14.184 ;
     RECT  10.829 41.904 13.208 44.664 ;
     RECT  13.208 2.148 13.312 45.372 ;
     RECT  13.312 2.418 13.504 45.102 ;
     RECT  13.504 2.496 14.821 2.76 ;
     RECT  13.504 4.128 14.821 4.392 ;
     RECT  13.504 10.848 14.821 10.872 ;
     RECT  14.821 10.848 14.861 10.968 ;
     RECT  14.821 2.496 15.908 2.856 ;
     RECT  14.821 4.128 15.908 4.488 ;
     RECT  13.504 6.144 15.908 6.168 ;
     RECT  14.861 10.944 15.908 10.968 ;
     RECT  13.504 14.16 15.908 14.184 ;
     RECT  13.504 41.904 15.908 44.664 ;
     RECT  15.325 46.128 15.908 46.152 ;
     RECT  15.908 2.148 16.204 46.152 ;
     RECT  16.204 41.904 16.549 46.152 ;
     RECT  16.204 6.816 16.841 6.84 ;
     RECT  16.204 2.148 16.909 2.856 ;
     RECT  16.204 37.584 17.093 38.424 ;
     RECT  16.204 4.128 17.269 4.488 ;
     RECT  16.204 17.04 17.345 17.064 ;
     RECT  16.204 23.28 17.453 23.352 ;
     RECT  16.549 41.904 17.485 46.296 ;
     RECT  16.204 14.16 17.665 14.952 ;
     RECT  17.701 35.664 17.773 35.688 ;
     RECT  17.557 6.768 17.809 6.792 ;
     RECT  17.093 37.584 17.809 37.608 ;
     RECT  17.809 6.768 17.845 7.656 ;
     RECT  17.845 6.768 18.133 7.944 ;
     RECT  17.485 25.488 18.133 25.512 ;
     RECT  17.809 37.296 18.133 37.608 ;
     RECT  18.025 38.736 18.133 38.76 ;
     RECT  16.909 1.536 18.421 2.856 ;
     RECT  17.269 3.84 18.421 4.488 ;
     RECT  18.421 1.536 18.529 4.488 ;
     RECT  17.269 30.672 18.529 30.696 ;
     RECT  18.529 1.536 18.565 4.68 ;
     RECT  18.133 13.056 18.565 13.08 ;
     RECT  18.565 1.2 18.608 4.68 ;
     RECT  18.025 5.76 18.608 5.784 ;
     RECT  18.133 6.768 18.608 8.472 ;
     RECT  16.204 10.944 18.608 11.208 ;
     RECT  18.565 12.288 18.608 13.08 ;
     RECT  17.665 14.16 18.608 15 ;
     RECT  17.989 16.08 18.608 16.104 ;
     RECT  18.025 17.616 18.608 17.64 ;
     RECT  17.453 23.28 18.608 23.304 ;
     RECT  18.133 25.488 18.608 25.56 ;
     RECT  17.773 27.072 18.608 27.096 ;
     RECT  18.529 30.672 18.608 30.888 ;
     RECT  16.204 33.072 18.608 33.096 ;
     RECT  17.773 35.664 18.608 36.264 ;
     RECT  18.133 37.296 18.608 38.76 ;
     RECT  16.204 40.56 18.608 40.584 ;
     RECT  17.485 41.712 18.608 46.296 ;
     RECT  18.608 1.2 18.904 46.296 ;
     RECT  18.904 5.76 18.929 13.224 ;
     RECT  18.929 6.144 18.965 13.224 ;
     RECT  18.904 38.112 18.965 46.296 ;
     RECT  18.965 41.808 19.393 46.296 ;
     RECT  18.904 1.2 19.897 3.384 ;
     RECT  18.904 4.464 19.897 4.632 ;
     RECT  18.965 6.144 19.897 10.488 ;
     RECT  18.965 11.52 19.933 13.224 ;
     RECT  18.904 14.304 19.933 36.744 ;
     RECT  18.965 38.112 19.933 40.776 ;
     RECT  19.393 41.808 19.933 46.44 ;
     RECT  19.897 1.2 20.437 4.632 ;
     RECT  19.897 5.664 20.437 10.488 ;
     RECT  20.437 1.2 20.473 10.488 ;
     RECT  19.933 11.52 20.473 36.744 ;
     RECT  19.933 38.112 20.473 46.44 ;
     RECT  20.473 1.056 20.509 36.744 ;
     RECT  20.473 37.824 20.509 46.44 ;
     RECT  20.509 1.056 21.564 46.44 ;
    LAYER M5 ;
     RECT  6.096 0.037 6.12 2.137 ;
     RECT  2.4 2.137 2.52 2.151 ;
     RECT  7.8 2.137 7.92 2.151 ;
     RECT  10.5 2.137 10.62 2.151 ;
     RECT  13.2 2.137 13.32 2.151 ;
     RECT  15.9 2.137 16.02 2.151 ;
     RECT  18.6 2.137 18.72 2.151 ;
     RECT  3.888 5.893 3.912 6.805 ;
     RECT  5.1 2.137 6.12 6.805 ;
     RECT  3.888 6.805 6.12 6.851 ;
     RECT  4.608 6.851 6.12 7.619 ;
     RECT  5.1 7.619 6.12 11.941 ;
     RECT  7.8 2.151 8.112 11.941 ;
     RECT  4.032 11.365 4.056 12.995 ;
     RECT  0.144 12.949 0.168 13.091 ;
     RECT  5.1 11.941 8.112 13.859 ;
     RECT  5.1 13.859 6.12 14.245 ;
     RECT  7.8 13.859 8.112 15.349 ;
     RECT  4.176 14.245 6.12 15.491 ;
     RECT  7.68 15.349 8.112 17.077 ;
     RECT  5.1 15.491 6.12 17.605 ;
     RECT  4.992 17.605 6.12 17.653 ;
     RECT  7.392 17.077 8.112 17.699 ;
     RECT  4.896 17.653 6.12 19.141 ;
     RECT  7.8 17.699 8.112 19.141 ;
     RECT  4.896 19.141 8.112 19.909 ;
     RECT  3.984 19.909 8.112 20.579 ;
     RECT  4.896 20.579 8.112 21.541 ;
     RECT  4.272 21.541 8.112 23.315 ;
     RECT  4.272 23.315 6.12 23.411 ;
     RECT  5.1 23.411 5.928 24.469 ;
     RECT  7.8 23.315 8.112 25.045 ;
     RECT  7.44 25.045 8.112 25.859 ;
     RECT  4.272 24.469 6.024 27.635 ;
     RECT  4.704 27.635 6.024 27.971 ;
     RECT  5.1 27.971 6.024 28.691 ;
     RECT  7.8 25.859 8.112 29.509 ;
     RECT  7.488 29.509 8.112 30.757 ;
     RECT  5.1 28.691 5.928 30.851 ;
     RECT  5.1 30.851 5.412 31.861 ;
     RECT  7.488 30.757 8.232 32.531 ;
     RECT  7.8 32.531 8.232 32.965 ;
     RECT  5.1 31.861 5.88 33.251 ;
     RECT  5.1 33.251 5.736 34.501 ;
     RECT  2.4 2.151 2.712 35.893 ;
     RECT  4.512 34.501 5.736 35.939 ;
     RECT  7.8 32.965 8.376 36.373 ;
     RECT  6.864 36.373 8.376 37.571 ;
     RECT  2.4 35.893 3.48 39.253 ;
     RECT  6.864 37.571 8.112 39.395 ;
     RECT  7.68 39.395 8.112 39.779 ;
     RECT  2.4 39.253 3.624 40.499 ;
     RECT  7.8 39.779 8.112 40.933 ;
     RECT  5.1 35.939 5.736 41.221 ;
     RECT  7.8 40.933 8.376 41.891 ;
     RECT  2.4 40.499 3.432 42.851 ;
     RECT  5.1 41.221 6.36 43.811 ;
     RECT  7.8 41.891 8.112 44.437 ;
     RECT  7.8 44.437 8.28 45.155 ;
     RECT  2.4 42.851 2.712 45.369 ;
     RECT  5.1 43.811 5.412 45.369 ;
     RECT  7.8 45.155 8.112 45.369 ;
     RECT  10.5 2.151 10.812 45.369 ;
     RECT  13.2 2.151 13.512 45.369 ;
     RECT  15.9 2.151 16.212 45.369 ;
     RECT  18.6 2.151 18.912 45.369 ;
     RECT  2.4 45.369 2.52 45.383 ;
     RECT  5.1 45.369 5.22 45.383 ;
     RECT  7.8 45.369 7.92 45.383 ;
     RECT  10.5 45.369 10.62 45.383 ;
     RECT  13.2 45.369 13.32 45.383 ;
     RECT  15.9 45.369 16.02 45.383 ;
     RECT  18.6 45.369 18.72 45.383 ;
  END
END qkd_rlys_296
END LIBRARY
